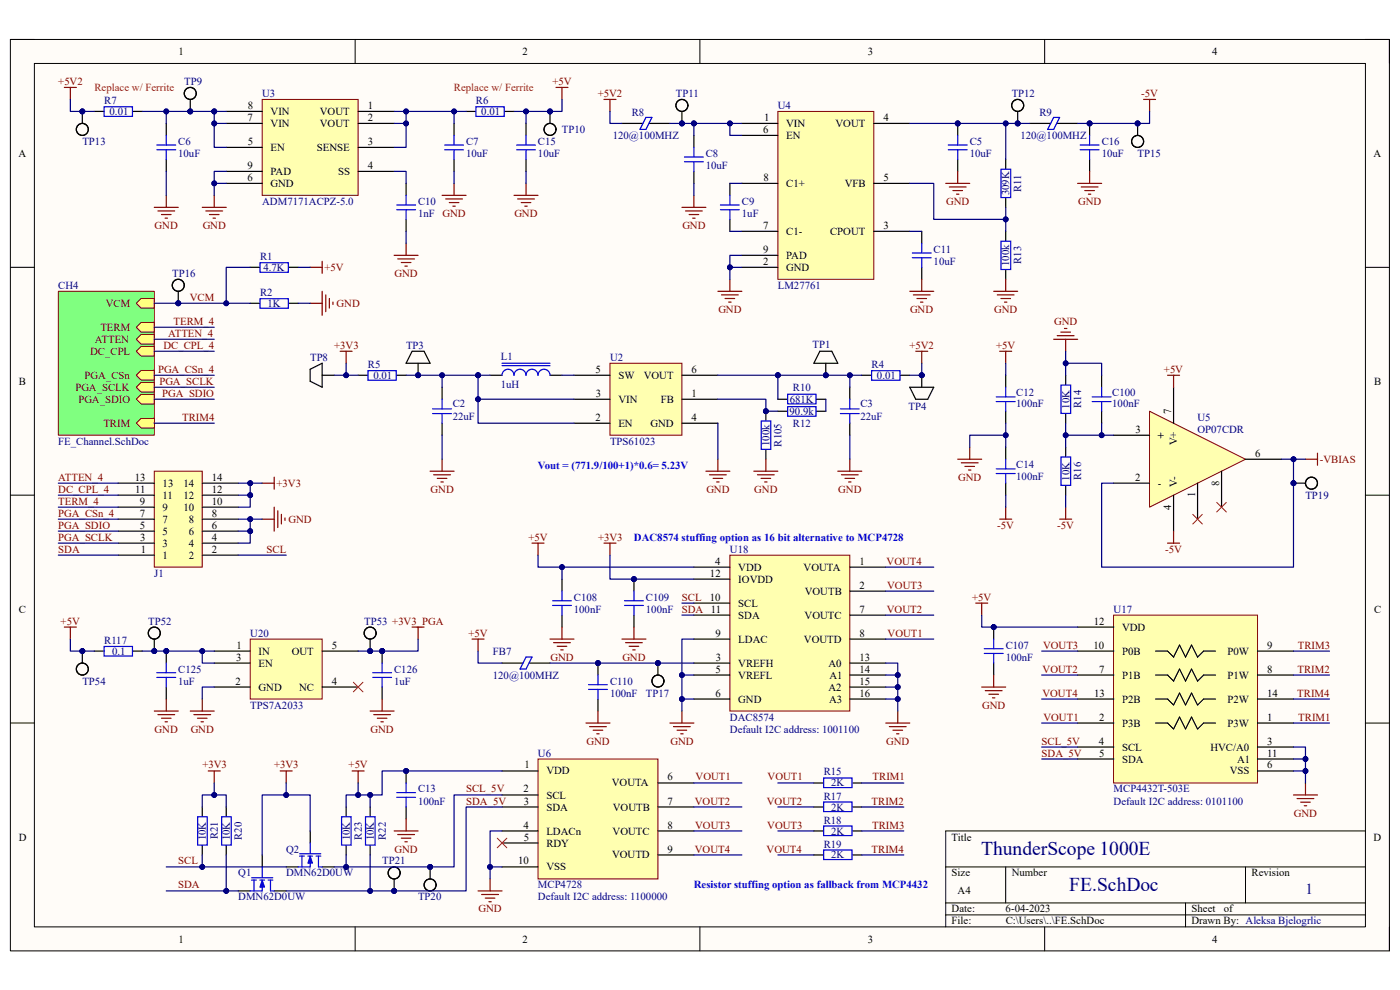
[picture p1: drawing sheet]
<svg xmlns="http://www.w3.org/2000/svg" width="297mm" height="210mm" viewBox="0 0 297 210" stroke-linecap="round" stroke-linejoin="round" font-family="sans-serif">
<defs><g id="words">
<g font-size="4.1" fill="#000080">
<text x="208.2" y="181.5">ThunderScope 1000E</text>
<text x="226.8" y="189.1">FE.SchDoc</text>
</g>
<text font-size="3.2" fill="#000080" x="276.9" y="189.6">1</text>
<g font-size="2.3">
<text x="37.9" y="11.7">1</text>
<text x="110.9" y="11.7">2</text>
<text x="184.1" y="11.7">3</text>
<text x="257.1" y="11.7">4</text>
<text x="52.6" y="23.1">8</text>
<text x="78" y="23.1">1</text>
<text x="52.5" y="25.7">7</text>
<text x="57.4" y="24.4">VIN</text>
<text x="57.4" y="26.9">VIN</text>
<text x="67.9" y="24.4">VOUT</text>
<text x="67.9" y="26.9">VOUT</text>
<text x="78" y="25.7">2</text>
<text x="161.9" y="28.2">6</text>
<text x="162.1" y="25.7">1</text>
<text x="166.8" y="26.9">VIN</text>
<text x="166.8" y="29.5">EN</text>
<text x="177.2" y="26.9">VOUT</text>
<text x="187.4" y="25.7">4</text>
<text x="3.9" y="33.3">A</text>
<text x="52.5" y="35.9">9</text>
<text x="52.6" y="30.7">5</text>
<text x="57.4" y="32">EN</text>
<text x="67.2" y="32">SENSE</text>
<text x="78" y="30.7">3</text>
<text x="78" y="35.9">4</text>
<text x="291.4" y="33.3">A</text>
<text x="52.5" y="38.4">6</text>
<text x="57.4" y="39.7">GND</text>
<text x="57.4" y="37.1">PAD</text>
<text x="71.8" y="37.1">SS</text>
<text x="162" y="38.4">8</text>
<text x="166.8" y="39.7">C1+</text>
<text x="179.2" y="39.7">VFB</text>
<text x="187.4" y="38.4">5</text>
<text x="161.9" y="48.6">7</text>
<text x="161.9" y="53.6">9</text>
<text x="166.8" y="49.8">C1-</text>
<text x="176.1" y="49.8">CPOUT</text>
<text x="187.4" y="48.6">3</text>
<text x="161.9" y="56.2">2</text>
<text x="166.8" y="57.4">GND</text>
<text x="166.8" y="54.9">PAD</text>
<text x="4" y="81.6">B</text>
<text x="126.4" y="79.1">5</text>
<text x="131.2" y="80.3">SW</text>
<text x="136.6" y="80.3">VOUT</text>
<text x="146.7" y="79.1">6</text>
<text x="291.5" y="81.6">B</text>
<text x="126.3" y="89.3">2</text>
<text x="126.4" y="84.2">3</text>
<text x="131.2" y="85.4">VIN</text>
<text x="140.2" y="85.4">FB</text>
<text x="146.7" y="89.3">4</text>
<text x="146.7" y="84.2">1</text>
<text x="248.5" y="87.8" transform="rotate(-90 248.5 87.8)">7</text>
<text x="131.2" y="90.6">EN</text>
<text x="138" y="90.6">GND</text>
<text x="240.9" y="91.8">3</text>
<text x="245.7" y="93.1">+</text>
<text x="249.7" y="94.5" transform="rotate(-90 249.7 94.5)">V+</text>
<text x="28.6" y="102">13</text>
<text x="45" y="102">14</text>
<text x="240.8" y="102">2</text>
<text x="266.3" y="96.9">6</text>
<text x="28.7" y="104.5">11</text>
<text x="29.6" y="107.1">9</text>
<text x="34.5" y="105.8">11</text>
<text x="34.5" y="103.3">13</text>
<text x="38.9" y="105.8">12</text>
<text x="38.9" y="103.3">14</text>
<text x="45" y="107.1">10</text>
<text x="45" y="104.5">12</text>
<text x="245.7" y="103.3">-</text>
<text x="249.7" y="103.3" transform="rotate(-90 249.7 103.3)">V-</text>
<text x="253.6" y="105.4" transform="rotate(-90 253.6 105.4)">1</text>
<text x="258.7" y="103" transform="rotate(-90 258.7 103)">8</text>
<text x="29.6" y="109.6">7</text>
<text x="29.7" y="112.1">5</text>
<text x="34.5" y="113.4">5</text>
<text x="34.5" y="110.9">7</text>
<text x="34.5" y="108.3">9</text>
<text x="38.9" y="108.3">10</text>
<text x="40" y="113.4">6</text>
<text x="40.1" y="110.9">8</text>
<text x="45" y="112.1">6</text>
<text x="45" y="109.6">8</text>
<text x="248.5" y="108.2" transform="rotate(-90 248.5 108.2)">4</text>
<text x="29.7" y="114.7">3</text>
<text x="29.8" y="117.3">1</text>
<text x="34.5" y="118.5">1</text>
<text x="34.5" y="116">3</text>
<text x="40" y="116">4</text>
<text x="40.1" y="118.5">2</text>
<text x="45" y="117.3">2</text>
<text x="45" y="114.7">4</text>
<text x="151.7" y="119.8">4</text>
<text x="182.3" y="119.8">1</text>
<text x="150.6" y="122.3">12</text>
<text x="156.6" y="121.1">VDD</text>
<text x="156.6" y="123.6">IOVDD</text>
<text x="170.5" y="121.1">VOUTA</text>
<text x="182.3" y="124.9">2</text>
<text x="4" y="130">C</text>
<text x="150.6" y="127.4">10</text>
<text x="156.6" y="128.7">SCL</text>
<text x="156.6" y="131.2">SDA</text>
<text x="170.7" y="131.2">VOUTC</text>
<text x="170.7" y="126.2">VOUTB</text>
<text x="182.3" y="130">7</text>
<text x="291.5" y="130">C</text>
<text x="50.2" y="137.6">1</text>
<text x="70.4" y="137.6">5</text>
<text x="151.8" y="135">9</text>
<text x="156.6" y="136.3">LDAC</text>
<text x="170.6" y="136.3">VOUTD</text>
<text x="182.3" y="135">8</text>
<text x="232" y="137.6">10</text>
<text x="232" y="132.5">12</text>
<text x="238" y="133.8">VDD</text>
<text x="268.8" y="137.6">9</text>
<text x="50.1" y="140.1">3</text>
<text x="54.9" y="138.9">IN</text>
<text x="54.9" y="141.4">EN</text>
<text x="61.9" y="138.9">OUT</text>
<text x="151.8" y="142.7">5</text>
<text x="151.8" y="140.1">3</text>
<text x="156.6" y="141.4">VREFH</text>
<text x="156.6" y="144">VREFL</text>
<text x="175.8" y="141.4">A0</text>
<text x="176" y="144">A1</text>
<text x="182.3" y="140.1">13</text>
<text x="182.3" y="142.7">14</text>
<text x="233.2" y="142.7">7</text>
<text x="238" y="138.9">P0B</text>
<text x="238" y="144">P1B</text>
<text x="260.4" y="138.9">P0W</text>
<text x="260.4" y="144">P1W</text>
<text x="268.8" y="142.7">8</text>
<text x="50" y="145.2">2</text>
<text x="54.9" y="146.5">GND</text>
<text x="63.5" y="146.5">NC</text>
<text x="70.4" y="145.2">4</text>
<text x="151.8" y="147.8">6</text>
<text x="156.6" y="149.1">GND</text>
<text x="175.8" y="146.5">A2</text>
<text x="175.9" y="149.1">A3</text>
<text x="182.3" y="145.2">15</text>
<text x="182.3" y="147.8">16</text>
<text x="232.1" y="147.8">13</text>
<text x="238" y="149.1">P2B</text>
<text x="260.4" y="149.1">P2W</text>
<text x="268.8" y="147.8">14</text>
<text x="233.2" y="152.9">2</text>
<text x="238" y="154.1">P3B</text>
<text x="260.4" y="154.1">P3W</text>
<text x="268.8" y="152.9">1</text>
<text x="233.1" y="157.9">4</text>
<text x="233.2" y="160.5">5</text>
<text x="238" y="159.2">SCL</text>
<text x="238" y="161.8">SDA</text>
<text x="256.8" y="159.2">HVC/A0</text>
<text x="262.5" y="161.8">A1</text>
<text x="268.8" y="157.9">3</text>
<text x="268.8" y="160.5">11</text>
<text x="111.3" y="163">1</text>
<text x="115.9" y="164.3">VDD</text>
<text x="129.8" y="166.8">VOUTA</text>
<text x="141.6" y="165.6">6</text>
<text x="260.9" y="164.3">VSS</text>
<text x="268.8" y="163">6</text>
<text x="111" y="168.1">2</text>
<text x="111.1" y="170.7">3</text>
<text x="115.9" y="169.4">SCL</text>
<text x="115.9" y="172">SDA</text>
<text x="130" y="172">VOUTB</text>
<text x="141.6" y="170.7">7</text>
<text x="4" y="178.3">D</text>
<text x="111" y="175.8">4</text>
<text x="111.1" y="178.3">5</text>
<text x="115.9" y="177">LDACn</text>
<text x="115.9" y="179.6">RDY</text>
<text x="130" y="177">VOUTC</text>
<text x="141.6" y="175.8">8</text>
<text x="201.9" y="178.3">Title</text>
<text x="291.4" y="178.3">D</text>
<text x="109.9" y="183.4">10</text>
<text x="115.9" y="184.7">VSS</text>
<text x="129.8" y="182.1">VOUTD</text>
<text x="141.6" y="180.8">9</text>
<text x="201.9" y="185.9">Size</text>
<text x="214.6" y="185.9">Number</text>
<text x="265.5" y="185.9">Revision</text>
<text x="203.2" y="189.7">A4</text>
<text x="201.9" y="193.5">Date:</text>
<text x="201.9" y="196.1">File:</text>
<text x="213.3" y="193.5">6-04-2023</text>
<text x="213.4" y="196.1">C:\Users\..\FE.SchDoc</text>
<text x="252.8" y="196.1">Drawn By: Aleksa Bjelogrlic</text>
<text x="252.8" y="193.5">Sheet</text>
<text x="259.6" y="193.5">of</text>
<text x="37.9" y="199.9">1</text>
<text x="110.9" y="199.9">2</text>
<text x="184.1" y="199.9">3</text>
<text x="257.1" y="199.9">4</text>
</g>
<g font-size="2.3" fill="#800000">
<text x="12.4" y="18">+5V2</text>
<text x="117.2" y="18">+5V</text>
<text x="126.8" y="20.6">+5V2</text>
<text x="242.1" y="20.6">-5V</text>
<text x="93.9" y="46">GND</text>
<text x="109.1" y="46">GND</text>
<text x="200.7" y="43.5">GND</text>
<text x="228.7" y="43.5">GND</text>
<text x="32.8" y="48.6">GND</text>
<text x="43" y="48.6">GND</text>
<text x="144.8" y="48.6">GND</text>
<text x="68.8" y="57.4">+5V</text>
<text x="83.7" y="58.7">GND</text>
<text x="22.4" y="65.1">VCM</text>
<text x="40.3" y="63.8">VCM</text>
<text x="71.4" y="65.1">GND</text>
<text x="21.3" y="70.2">TERM</text>
<text x="35.7" y="71.5">ATTEN_4</text>
<text x="36.8" y="68.9">TERM_4</text>
<text x="152.4" y="66.4">GND</text>
<text x="193.1" y="66.4">GND</text>
<text x="210.9" y="66.4">GND</text>
<text x="223.6" y="68.9">GND</text>
<text x="19.1" y="75.3">DC_CPL</text>
<text x="20.2" y="72.7">ATTEN</text>
<text x="34.7" y="74">DC_CPL_4</text>
<text x="70.9" y="74">+3V3</text>
<text x="193" y="74">+5V2</text>
<text x="211.3" y="74">+5V</text>
<text x="16" y="82.9">PGA_SCLK</text>
<text x="17.9" y="80.3">PGA_CSn</text>
<text x="33.5" y="79.1">PGA_CSn_4</text>
<text x="33.8" y="81.6">PGA_SCLK</text>
<text x="246.9" y="79.1">+5V</text>
<text x="16.6" y="85.4">PGA_SDIO</text>
<text x="34.4" y="84.2">PGA_SDIO</text>
<text x="38.7" y="89.3">TRIM4</text>
<text x="21.9" y="90.6">TRIM</text>
<text x="12.4" y="102">ATTEN_4</text>
<text x="203.3" y="102">GND</text>
<text x="280" y="98.2">-VBIAS</text>
<text x="12.4" y="104.5">DC_CPL_4</text>
<text x="12.4" y="107.1">TERM_4</text>
<text x="58.7" y="103.3">+3V3</text>
<text x="91.4" y="104.5">GND</text>
<text x="149.9" y="104.5">GND</text>
<text x="160" y="104.5">GND</text>
<text x="177.8" y="104.5">GND</text>
<text x="12.4" y="112.1">PGA_SDIO</text>
<text x="12.4" y="109.6">PGA_CSn_4</text>
<text x="61.2" y="110.9">GND</text>
<text x="211.6" y="112.1">-5V</text>
<text x="224.3" y="112.1">-5V</text>
<text x="12.4" y="117.3">SDA</text>
<text x="12.4" y="114.7">PGA_SCLK</text>
<text x="56.6" y="117.3">SCL</text>
<text x="112.1" y="114.7">+5V</text>
<text x="126.9" y="114.7">+3V3</text>
<text x="188.1" y="119.8">VOUT4</text>
<text x="247.2" y="117.3">-5V</text>
<text x="188.2" y="124.9">VOUT3</text>
<text x="144.7" y="127.4">SCL</text>
<text x="144.7" y="130">SDA 11</text>
<text x="188.1" y="130">VOUT2</text>
<text x="206.2" y="127.4">+5V</text>
<text x="12.9" y="132.5">+5V</text>
<text x="99.4" y="135">+5V</text>
<text x="188.3" y="135">VOUT1</text>
<text x="221.3" y="137.6">VOUT3</text>
<text x="275.3" y="137.6">TRIM3</text>
<text x="116.8" y="140.1">GND</text>
<text x="132" y="140.1">GND</text>
<text x="221.2" y="142.7">VOUT2</text>
<text x="275.3" y="142.7">TRIM2</text>
<text x="221.1" y="147.8">VOUT4</text>
<text x="275.2" y="147.8">TRIM4</text>
<text x="32.8" y="155.4">GND</text>
<text x="40.5" y="155.4">GND</text>
<text x="78.6" y="155.4">GND</text>
<text x="208.4" y="150.3">GND</text>
<text x="221.4" y="152.9">VOUT1</text>
<text x="275.4" y="152.9">TRIM1</text>
<text x="124.4" y="157.9">GND</text>
<text x="142.2" y="157.9">GND</text>
<text x="188" y="157.9">GND</text>
<text x="221" y="157.9">SCL_5V</text>
<text x="221" y="160.5">SDA_5V</text>
<text x="42.9" y="163">+3V3</text>
<text x="58.2" y="163">+3V3</text>
<text x="74" y="163">+5V</text>
<text x="147.6" y="165.6">VOUT1</text>
<text x="162.9" y="165.6">VOUT1</text>
<text x="185.1" y="165.6">TRIM1</text>
<text x="98.9" y="168.1">SCL_5V</text>
<text x="98.9" y="170.7">SDA_5V</text>
<text x="147.4" y="170.7">VOUT2</text>
<text x="162.7" y="170.7">VOUT2</text>
<text x="184.9" y="170.7">TRIM2</text>
<text x="274.5" y="173.2">GND</text>
<text x="147.5" y="175.8">VOUT3</text>
<text x="162.8" y="175.8">VOUT3</text>
<text x="185" y="175.8">TRIM3</text>
<text x="37.8" y="183.4">SCL</text>
<text x="83.7" y="180.8">GND</text>
<text x="147.4" y="180.8">VOUT4</text>
<text x="162.6" y="180.8">VOUT4</text>
<text x="184.9" y="180.8">TRIM4</text>
<text x="37.8" y="188.5">SDA</text>
<text x="101.5" y="193.5">GND</text>
</g>
<g font-size="2.3" fill="#f00">
<text x="20" y="19.3">Replace w/ Ferrite</text>
<text x="96.3" y="19.3">Replace w/ Ferrite</text>
</g>
<g font-size="2.3" fill="#000080">
<text x="22.1" y="22.1">R7</text>
<text x="39.1" y="18">TP9</text>
<text x="55.6" y="20.6">U3</text>
<text x="101" y="22.1">R6</text>
<text x="143.4" y="20.6">TP11</text>
<text x="165" y="23.1">U4</text>
<text x="214.6" y="20.6">TP12</text>
<text x="23.2" y="24.4">0.01</text>
<text x="102.1" y="24.4">0.01</text>
<text x="119.2" y="28.2">TP10</text>
<text x="130" y="29.5">120@100MHZ</text>
<text x="134" y="24.7">R8</text>
<text x="216.5" y="29.5">120@100MHZ</text>
<text x="220.5" y="24.7">R9</text>
<text x="17.5" y="30.7">TP13</text>
<text x="37.8" y="30.7">C6</text>
<text x="37.8" y="33.3">10uF</text>
<text x="98.9" y="30.7">C7</text>
<text x="98.9" y="33.3">10uF</text>
<text x="114.1" y="30.7">C15</text>
<text x="114.1" y="33.3">10uF</text>
<text x="149.7" y="33.3">C8</text>
<text x="149.7" y="35.9">10uF</text>
<text x="205.7" y="30.7">C5</text>
<text x="205.7" y="33.3">10uF</text>
<text x="233.7" y="30.7">C16</text>
<text x="233.7" y="33.3">10uF</text>
<text x="241.3" y="33.3">TP15</text>
<text x="214.1" y="41.4" transform="rotate(-90 214.1 41.4)">309K</text>
<text x="216.7" y="40.7" transform="rotate(-90 216.7 40.7)">R11</text>
<text x="55.6" y="43.5">ADM7171ACPZ-5.0</text>
<text x="88.7" y="43.5">C10</text>
<text x="88.7" y="46">1nF</text>
<text x="157.4" y="43.5">C9</text>
<text x="157.4" y="46">1uF</text>
<text x="198.1" y="53.6">C11</text>
<text x="36.5" y="58.7">TP16</text>
<text x="55.2" y="55.2">R1</text>
<text x="55.9" y="57.4">4.7K</text>
<text x="198.1" y="56.2">10uF</text>
<text x="214.1" y="56.5" transform="rotate(-90 214.1 56.5)">100k</text>
<text x="216.7" y="56" transform="rotate(-90 216.7 56)">R13</text>
<text x="12.4" y="61.3">CH4</text>
<text x="55.2" y="62.9">R2</text>
<text x="56.8" y="65.1">1K</text>
<text x="165" y="61.3">LM27761</text>
<text x="65.8" y="76.5">TP8</text>
<text x="86.1" y="74">TP3</text>
<text x="106.3" y="76.3">L1</text>
<text x="129.4" y="76.5">U2</text>
<text x="172.4" y="73.7">TP1</text>
<text x="78.1" y="78.1">R5</text>
<text x="79.2" y="80.3">0.01</text>
<text x="106.3" y="82.4">1uH</text>
<text x="168.2" y="82.9">R10</text>
<text x="184.9" y="78.1">R4</text>
<text x="186.1" y="80.3">0.01</text>
<text x="215.6" y="83.9">C12</text>
<text x="236" y="83.9">C100</text>
<text x="96.1" y="86.4">C2</text>
<text x="96.1" y="89">22uF</text>
<text x="167.5" y="88">90.9k</text>
<text x="167.6" y="85.4">681K</text>
<text x="182.5" y="86.4">C3</text>
<text x="182.5" y="89">22uF</text>
<text x="192.7" y="87">TP4</text>
<text x="215.6" y="86.4">100nF</text>
<text x="226.9" y="86.7" transform="rotate(-90 226.9 86.7)">10K</text>
<text x="229.4" y="86.6" transform="rotate(-90 229.4 86.6)">R14</text>
<text x="236" y="86.4">100nF</text>
<text x="254" y="89.3">U5</text>
<text x="12.4" y="94.4">FE_Channel.SchDoc</text>
<text x="129.4" y="94.4">TPS61023</text>
<text x="163.2" y="94.6" transform="rotate(-90 163.2 94.6)">100k</text>
<text x="165.8" y="94.7" transform="rotate(-90 165.8 94.7)">R105</text>
<text x="168.2" y="90.6">R12</text>
<text x="254" y="91.8">OP07CDR</text>
<text x="215.6" y="99.2">C14</text>
<text x="215.6" y="101.7">100nF</text>
<text x="226.9" y="101.9" transform="rotate(-90 226.9 101.9)">10K</text>
<text x="229.4" y="101.8" transform="rotate(-90 229.4 101.8)">R16</text>
<text x="276.9" y="105.8">TP19</text>
<text x="154.9" y="117.3">U18</text>
<text x="32.7" y="122.3">J1</text>
<text x="121.8" y="127.4">C108</text>
<text x="121.8" y="130">100nF</text>
<text x="137" y="127.4">C109</text>
<text x="137" y="130">100nF</text>
<text x="236.3" y="130">U17</text>
<text x="22.1" y="136.6">R117</text>
<text x="31.5" y="132.5">TP52</text>
<text x="53.1" y="135">U20</text>
<text x="77.3" y="132.5">TP53 +3V3_PGA</text>
<text x="213.4" y="137.6">C107</text>
<text x="23.8" y="138.9">0.1</text>
<text x="37.8" y="142.7">C125</text>
<text x="83.6" y="142.7">C126</text>
<text x="104.6" y="138.9">FB7</text>
<text x="104.6" y="144">120@100MHZ</text>
<text x="213.4" y="140.1">100nF</text>
<text x="17.5" y="145.2">TP54</text>
<text x="37.8" y="145.2">1uF</text>
<text x="83.6" y="145.2">1uF</text>
<text x="129.4" y="145.2">C110</text>
<text x="129.4" y="147.8">100nF</text>
<text x="137" y="147.8">TP17</text>
<text x="53.1" y="150.3">TPS7A2033</text>
<text x="154.9" y="152.9">DAC8574</text>
<text x="154.9" y="155.4">Default I2C address: 1001100</text>
<text x="114.1" y="160.5">U6</text>
<text x="174.8" y="164.5">R15</text>
<text x="176.3" y="166.8">2K</text>
<text x="88.7" y="168.1">C13</text>
<text x="88.7" y="170.7">100nF</text>
<text x="174.8" y="169.6">R17</text>
<text x="176.3" y="172">2K</text>
<text x="236.3" y="168.1">MCP4432T-503E</text>
<text x="236.3" y="170.7">Default I2C address: 0101100</text>
<text x="43.7" y="178.3" transform="rotate(-90 43.7 178.3)">10K</text>
<text x="46.2" y="178.1" transform="rotate(-90 46.2 178.1)">R21</text>
<text x="48.8" y="178.3" transform="rotate(-90 48.8 178.3)">10K</text>
<text x="51.3" y="178.1" transform="rotate(-90 51.3 178.1)">R20</text>
<text x="74.2" y="178.3" transform="rotate(-90 74.2 178.3)">10K</text>
<text x="76.8" y="178.1" transform="rotate(-90 76.8 178.1)">R23</text>
<text x="79.3" y="178.3" transform="rotate(-90 79.3 178.3)">10K</text>
<text x="81.8" y="178.1" transform="rotate(-90 81.8 178.1)">R22</text>
<text x="174.8" y="174.7">R18</text>
<text x="174.8" y="179.8">R19</text>
<text x="176.3" y="177">2K</text>
<text x="50.5" y="185.9">Q1</text>
<text x="60.7" y="180.8">Q2</text>
<text x="60.7" y="185.9">DMN62D0UW</text>
<text x="81.1" y="183.4">TP21</text>
<text x="176.3" y="182.1">2K</text>
<text x="50.5" y="191">DMN62D0UW</text>
<text x="88.7" y="191">TP20</text>
<text x="114.1" y="188.5">MCP4728</text>
<text x="114.1" y="191">Default I2C address: 1100000</text>
</g>
<g font-size="2.3" fill="#00f">
<text x="114.1" y="99.4">Vout = (771.9/100+1)*0.6= 5.23V</text>
<text x="134.5" y="114.7">DAC8574 stuffing option as 16 bit alternative to MCP4728</text>
<text x="147.2" y="188.5">Resistor stuffing option as fallback from MCP4432</text>
</g>
</g></defs>
<path d="M2.2 8.4h292.6v193.3h-292.6z" fill-rule="evenodd" fill="#fffcf8"/>
<path d="M2.2 8.4h292.6v193.3h-292.6z" fill="none" stroke="#000" stroke-width=".21"/>
<path d="M7.3 13.5h282.4v183.1h-282.4z" fill-rule="evenodd" fill="#fffcf8"/>
<g fill="none" stroke="#000" stroke-width=".21">
<path d="M2.2 8.4h5.1M7.3 13.5h282.4v183.1h-282.4zM75.3 8.4v5.1M148.5 8.4v5.1M221.6 8.4v5.1M289.7 8.4h5.1v5.1M2.2 56.7h5.1M289.7 56.7h5.1M2.2 105h5.1M289.7 105.1h5.1M2.2 153.4h5.1M289.7 153.4h5.1"/>
<path d="M289.7 176.3h-89.1v20.3M75.3 196.6v5.1M148.5 196.6v5.1M200.6 183.9h89.1M200.6 191.5h89.1M200.6 194.1h89.1M213.4 183.9v7.6M221.6 196.6v5.1M251.5 191.5v5.1M264.2 183.9v7.6M294.8 196.6v5.1"/>
</g>
<circle cx="86.2" cy="163.6" r=".51" fill="#000080"/>
<circle cx="86.2" cy="163.6" r=".51" fill="none" stroke="#000080" stroke-width=".21"/>
<path d="M86.2 163.6v2.5M86.2 171.2v2.5" fill="none" stroke="#000" stroke-width=".25"/>
<circle cx="86.2" cy="163.6" r=".51" fill="#000080"/>
<circle cx="86.2" cy="163.6" r=".51" fill="none" stroke="#000080" stroke-width=".21"/>
<path d="M84.2 169.1h4M84.2 168.1h4M86.2 166.1v2M86.2 169.1v2.1" fill="none" stroke="#00f" stroke-width=".25"/>
<g fill="none" stroke="#800000" stroke-width=".25">
<path d="M44.2 163.6h2.5M45.5 163.6v2.5M59.4 163.6h2.6M60.7 163.6v2.5M83.6 176.3h5.1M84.4 177h3.5M85.1 177.8h2.1M85.9 178.6h.5M86.2 173.7v2.6M101.4 189h5.1M102.2 189.8h3.5M102.9 190.5h2.1"/>
<path d="M103.7 191.3h.5M104 186.5v2.5"/>
</g>
<path d="M243.9 87.2l20.3 10.2-20.3 10.2z" fill="#ffffb0"/>
<path d="M243.9 87.2l20.3 10.2-20.3 10.2z" fill="none" stroke="#800000" stroke-width=".21"/>
<path d="M226.1 79.6v2M226.1 87.8v2M226.1 94.9v2M236.3 92.3h7.6M249 82.1v7.7M259.2 100v7.6M264.2 97.4h7.7M226.1 103v2.1M236.3 102.5h7.6M249 105.1v7.6M254.1 102.5v7.6" fill="none" stroke="#000" stroke-width=".25"/>
<path d="M253 109.1l2.1 2.1M255.1 109.1l-2.1 2.1M258.1 106.6l2.1 2M260.2 106.6l-2.1 2" fill="none" stroke="#f00" stroke-width=".21"/>
<path d="M225.1 81.7h2v6h-2zM225.1 97h2v6h-2z" fill="none" stroke="#00f" stroke-width=".25"/>
<path d="M277 97.4h2.5M279.5 96.1v2.6" fill="none" stroke="#800000" stroke-width=".25"/>
<path d="M114.1 161h25.5v25.5h-25.5z" fill-rule="evenodd" fill="#ffffb0"/>
<path d="M114.1 161h25.5v25.5h-25.5z" fill="none" stroke="#800000" stroke-width=".21"/>
<path d="M106.5 163.6h7.6M106.5 168.6h7.6M106.5 171.2h7.6M106.5 176.3h7.6M106.5 178.8h7.6M139.6 171.2h7.6M139.6 166.1h7.6M139.6 176.3h7.6M106.5 183.9h7.6M139.6 181.4h7.6" fill="none" stroke="#000" stroke-width=".25"/>
<path d="M105.5 177.8l2 2M107.5 177.8l-2 2" fill="none" stroke="#f00" stroke-width=".21"/>
<path d="M165 23.6h20.4v35.7h-20.4z" fill-rule="evenodd" fill="#ffffb0"/>
<path d="M165 23.6h20.4v35.7h-20.4z" fill="none" stroke="#800000" stroke-width=".21"/>
<g fill="none" stroke="#000" stroke-width=".25">
<path d="M147.2 28.7v2.6M147.2 36.4v2.5M154.8 38.9v2.5M157.4 26.2h7.6M157.4 28.7h7.6M157.4 38.9h7.6M185.4 26.2h7.6M185.4 38.9h7.6M213.4 33.8v2M154.8 46.5v2.6M157.4 56.7h7.6M157.4 49.1h7.6"/>
<path d="M157.4 54.2h7.6M185.4 49.1h7.6M195.5 49.1v2.5M195.5 56.7v2.6M213.4 42v2M213.4 49.1v2M213.4 57.3v2"/>
</g>
<g fill="none" stroke="#00f" stroke-width=".25">
<path d="M145.2 34.3h4M145.2 33.3h4M147.2 31.3v2M147.2 34.3v2.1M212.4 35.9h2v6h-2zM152.8 44.5h4M152.8 43.5h4M154.8 41.4v2.1M154.8 44.5v2M193.5 54.7h4M193.5 53.7h4M195.5 51.6v2.1"/>
<path d="M195.5 54.7v2M212.4 51.2h2v6h-2z"/>
</g>
<g fill="none" stroke="#800000" stroke-width=".25">
<path d="M128.1 21.1h2.6M129.4 21.1v2.5M144.7 44h5.1M145.4 44.8h3.6M146.2 45.5h2M147 46.3h.5M147.2 41.4v2.6M154.8 59.3v2.5M195.5 59.3v2.5M213.4 59.3v2.5M152.3 61.8h5.1M153.1 62.6h3.5"/>
<path d="M153.8 63.3h2.1M154.6 64.1h.5M193 61.8h5.1M193.8 62.6h3.5M194.5 63.3h2.1M195.3 64.1h.5M210.8 61.8h5.1M211.6 62.6h3.5M212.3 63.3h2.1M213.1 64.1h.5"/>
</g>
<circle cx="203.2" cy="26.2" r=".51" fill="#000080"/>
<circle cx="203.2" cy="26.2" r=".51" fill="none" stroke="#000080" stroke-width=".21"/>
<path d="M203.2 26.2v2.5M203.2 33.8v2.6" fill="none" stroke="#000" stroke-width=".25"/>
<circle cx="203.2" cy="26.2" r=".51" fill="#000080"/>
<circle cx="203.2" cy="26.2" r=".51" fill="none" stroke="#000080" stroke-width=".21"/>
<path d="M201.2 31.8h4M201.2 30.8h4M203.2 28.7v2.1M203.2 31.8v2M223.5 24.9h1.3l-1.3 2.6h-1.2z" fill="none" stroke="#00f" stroke-width=".25"/>
<path d="M200.6 38.9h5.1M201.4 39.7h3.6M203.2 36.4v2.5M242.6 21.1h2.6M243.9 21.1v2.5M202.2 40.4h2M202.9 41.2h.5" fill="none" stroke="#800000" stroke-width=".25"/>
<path d="M218.5 26.2h4.4M224.2 26.2h4.4" fill="none" stroke="#000" stroke-width=".25"/>
<path d="M55.6 21.1h20.4v20.3h-20.4z" fill-rule="evenodd" fill="#ffffb0"/>
<path d="M55.6 21.1h20.4v20.3h-20.4z" fill="none" stroke="#800000" stroke-width=".21"/>
<g fill="none" stroke="#000" stroke-width=".25">
<path d="M20 23.6h2M28.2 23.6h2M35.3 26.2v2.5M35.3 33.8v2.6M48 23.6h7.6M48 26.2h7.6M48 31.3h7.6M48 38.9h7.6M48 36.4h7.6M76 23.6h7.6M76 26.2h7.6M76 31.3h7.6"/>
<path d="M76 36.4h7.6M86.2 38.9v2.5M96.3 26.2v2.5M96.3 33.8v2.6M131.9 26.2h4.5M137.7 26.2h4.4M86.2 46.5v2.6"/>
</g>
<g fill="none" stroke="#800000" stroke-width=".25">
<path d="M13.6 18.5h2.6M14.9 18.5v2.6M118 18.5h2.5M119.2 18.5v2.6M96.3 38.9v2.5M32.7 44h5.1M33.5 44.8h3.6M34.3 45.5h2M35 46.3h.5M35.3 41.4v2.6M42.9 44h5.1M43.7 44.8h3.5"/>
<path d="M44.4 45.5h2.1M45.2 46.3h.5M45.5 41.4v2.6M83.6 54.2h5.1M84.4 54.9h3.5M85.1 55.7h2.1M85.9 56.5h.5M86.2 51.6v2.6M93.8 41.4h5.1M94.6 42.2h3.5M95.3 43h2.1M96.1 43.7h.5"/>
</g>
<g fill="none" stroke="#00f" stroke-width=".25">
<path d="M22.1 22.7h6v2h-6zM33.3 31.8h4M33.3 30.8h4M35.3 28.7v2.1M35.3 31.8v2M94.3 31.8h4M94.3 30.8h4M96.3 28.7v2.1M96.3 31.8v2M137 24.9h1.3l-1.3 2.6h-1.2zM84.2 44.5h4M84.2 43.5h4"/>
<path d="M86.2 41.4v2.1M86.2 44.5v2"/>
</g>
<circle cx="17.5" cy="23.6" r=".51" fill="#000080"/>
<circle cx="17.5" cy="23.6" r=".51" fill="none" stroke="#000080" stroke-width=".21"/>
<path d="M17.5 23.6v2.6" fill="none" stroke="#000" stroke-width=".25"/>
<circle cx="17.5" cy="23.6" r=".51" fill="#000080"/>
<circle cx="17.5" cy="23.6" r=".51" fill="none" stroke="#000080" stroke-width=".21"/>
<circle cx="17.5" cy="27.5" r="1.27" fill="none" stroke="#000" stroke-width=".25"/>
<circle cx="40.4" cy="23.6" r=".51" fill="#000080"/>
<circle cx="40.4" cy="23.6" r=".51" fill="none" stroke="#000080" stroke-width=".21"/>
<path d="M40.4 21.1v2.5" fill="none" stroke="#000" stroke-width=".25"/>
<circle cx="40.4" cy="23.6" r=".51" fill="#000080"/>
<circle cx="40.4" cy="23.6" r=".51" fill="none" stroke="#000080" stroke-width=".21"/>
<circle cx="40.4" cy="19.8" r="1.27" fill="none" stroke="#000" stroke-width=".25"/>
<circle cx="144.7" cy="26.2" r=".51" fill="#000080"/>
<circle cx="144.7" cy="26.2" r=".51" fill="none" stroke="#000080" stroke-width=".21"/>
<path d="M144.7 23.6v2.6" fill="none" stroke="#000" stroke-width=".25"/>
<circle cx="144.7" cy="26.2" r=".51" fill="#000080"/>
<circle cx="144.7" cy="26.2" r=".51" fill="none" stroke="#000080" stroke-width=".21"/>
<circle cx="144.7" cy="22.4" r="1.27" fill="none" stroke="#000" stroke-width=".25"/>
<circle cx="215.9" cy="26.2" r=".51" fill="#000080"/>
<circle cx="215.9" cy="26.2" r=".51" fill="none" stroke="#000080" stroke-width=".21"/>
<path d="M215.9 23.6v2.6" fill="none" stroke="#000" stroke-width=".25"/>
<circle cx="215.9" cy="26.2" r=".51" fill="#000080"/>
<circle cx="215.9" cy="26.2" r=".51" fill="none" stroke="#000080" stroke-width=".21"/>
<circle cx="215.9" cy="22.4" r="1.27" fill="none" stroke="#000" stroke-width=".25"/>
<circle cx="241.3" cy="26.2" r=".51" fill="#000080"/>
<circle cx="241.3" cy="26.2" r=".51" fill="none" stroke="#000080" stroke-width=".21"/>
<path d="M241.3 26.2v2.5" fill="none" stroke="#000" stroke-width=".25"/>
<circle cx="241.3" cy="26.2" r=".51" fill="#000080"/>
<circle cx="241.3" cy="26.2" r=".51" fill="none" stroke="#000080" stroke-width=".21"/>
<circle cx="241.3" cy="30" r="1.27" fill="none" stroke="#000" stroke-width=".25"/>
<circle cx="274.4" cy="102.5" r=".51" fill="#000080"/>
<circle cx="274.4" cy="102.5" r=".51" fill="none" stroke="#000080" stroke-width=".21"/>
<path d="M274.4 102.5h2.6" fill="none" stroke="#000" stroke-width=".25"/>
<circle cx="274.4" cy="102.5" r=".51" fill="#000080"/>
<circle cx="274.4" cy="102.5" r=".51" fill="none" stroke="#000080" stroke-width=".21"/>
<circle cx="278.2" cy="102.5" r="1.27" fill="none" stroke="#000" stroke-width=".25"/>
<circle cx="37.8" cy="64.3" r=".51" fill="#000080"/>
<circle cx="37.8" cy="64.3" r=".51" fill="none" stroke="#000080" stroke-width=".21"/>
<path d="M37.8 61.8v2.5" fill="none" stroke="#000" stroke-width=".25"/>
<circle cx="37.8" cy="64.3" r=".51" fill="#000080"/>
<circle cx="37.8" cy="64.3" r=".51" fill="none" stroke="#000080" stroke-width=".21"/>
<circle cx="37.8" cy="60.5" r="1.27" fill="none" stroke="#000" stroke-width=".25"/>
<circle cx="91.2" cy="183.9" r=".51" fill="#000080"/>
<circle cx="91.2" cy="183.9" r=".51" fill="none" stroke="#000080" stroke-width=".21"/>
<path d="M91.2 183.9v2.6" fill="none" stroke="#000" stroke-width=".25"/>
<circle cx="91.2" cy="183.9" r=".51" fill="#000080"/>
<circle cx="91.2" cy="183.9" r=".51" fill="none" stroke="#000080" stroke-width=".21"/>
<circle cx="91.2" cy="187.7" r="1.27" fill="none" stroke="#000" stroke-width=".25"/>
<circle cx="83.6" cy="189" r=".51" fill="#000080"/>
<circle cx="83.6" cy="189" r=".51" fill="none" stroke="#000080" stroke-width=".21"/>
<path d="M83.6 186.5v2.5" fill="none" stroke="#000" stroke-width=".25"/>
<circle cx="83.6" cy="189" r=".51" fill="#000080"/>
<circle cx="83.6" cy="189" r=".51" fill="none" stroke="#000080" stroke-width=".21"/>
<circle cx="83.6" cy="185.2" r="1.27" fill="none" stroke="#000" stroke-width=".25"/>
<circle cx="116.7" cy="23.6" r=".51" fill="#000080"/>
<circle cx="116.7" cy="23.6" r=".51" fill="none" stroke="#000080" stroke-width=".21"/>
<path d="M116.7 23.6v2.6" fill="none" stroke="#000" stroke-width=".25"/>
<circle cx="116.7" cy="23.6" r=".51" fill="#000080"/>
<circle cx="116.7" cy="23.6" r=".51" fill="none" stroke="#000080" stroke-width=".21"/>
<g fill="none" stroke="#000" stroke-width=".25">
<path d="M213.4 79.6v2.5M213.4 87.2v2.6M213.4 94.9v2.5M213.4 102.5v2.6"/>
<circle cx="116.7" cy="27.5" r="1.27"/>
</g>
<path d="M211.3 99.5h4.1M211.3 84.2h4.1M211.3 85.2h4.1M213.4 82.1v2.1M213.4 85.2v2M213.4 97.4v2.1M211.3 100.5h4.1M213.4 100.5v2" fill="none" stroke="#00f" stroke-width=".25"/>
<g fill="none" stroke="#800000" stroke-width=".25">
<path d="M212.1 74.5h2.5M213.4 74.5v2.6M247.7 79.6h2.5M249 79.6v2.5M203.2 97.4h5.1M203.9 98.2h3.6M204.7 98.9h2M205.5 99.7h.5M205.7 94.9v2.5M212.1 110.1h2.5M213.4 107.6v2.5M224.8 110.1h2.6"/>
<path d="M226.1 107.6v2.5M247.7 115.2h2.5M249 112.7v2.5M74.7 163.6h2.6M76 163.6v2.5"/>
</g>
<path d="M12.4 61.8h20.3v30.5h-20.3z" fill-rule="evenodd" fill="#80ff80"/>
<path d="M12.4 61.8h20.3v30.5h-20.3z" fill="none" stroke="#800000" stroke-width=".21"/>
<path d="M28.9 64.3l1-1h2.8v2.1h-2.8z" fill-rule="evenodd" fill="#ffff80"/>
<path d="M28.9 64.3l1-1h2.8v2.1h-2.8z" fill="none" stroke="#800000" stroke-width=".21"/>
<path d="M28.9 89.8l1-1h2.8v2h-2.8z" fill-rule="evenodd" fill="#ffff80"/>
<path d="M28.9 89.8l1-1h2.8v2h-2.8z" fill="none" stroke="#800000" stroke-width=".21"/>
<path d="M28.9 72l1-1h2.8v2h-2.8z" fill-rule="evenodd" fill="#ffff80"/>
<path d="M28.9 72l1-1h2.8v2h-2.8z" fill="none" stroke="#800000" stroke-width=".21"/>
<path d="M28.9 74.5l1-1h2.8v2h-2.8z" fill-rule="evenodd" fill="#ffff80"/>
<path d="M28.9 74.5l1-1h2.8v2h-2.8z" fill="none" stroke="#800000" stroke-width=".21"/>
<path d="M28.9 79.6l1-1h2.8v2h-2.8z" fill-rule="evenodd" fill="#ffff80"/>
<path d="M28.9 79.6l1-1h2.8v2h-2.8z" fill="none" stroke="#800000" stroke-width=".21"/>
<path d="M29.9 81.1h2.8v2.1h-2.8l-1-1.1z" fill-rule="evenodd" fill="#ffff80"/>
<path d="M29.9 81.1h2.8v2.1h-2.8l-1-1.1z" fill="none" stroke="#800000" stroke-width=".21"/>
<path d="M28.9 84.7l1-1h2.8v2h-2.8z" fill-rule="evenodd" fill="#ffff80"/>
<path d="M28.9 84.7l1-1h2.8v2h-2.8z" fill="none" stroke="#800000" stroke-width=".21"/>
<path d="M28.9 69.4l1-1h2.8v2h-2.8z" fill-rule="evenodd" fill="#ffff80"/>
<path d="M28.9 69.4l1-1h2.8v2h-2.8z" fill="none" stroke="#800000" stroke-width=".21"/>
<path d="M223.5 72h5.1M224.3 71.2h3.6M225.1 70.5h2M225.8 69.7h.5M226.1 72v2.5" fill="none" stroke="#800000" stroke-width=".25"/>
<path d="M233.7 79.6v2.5M233.7 87.2v2.6" fill="none" stroke="#000" stroke-width=".25"/>
<path d="M231.7 84.2h4M231.7 85.2h4M233.7 82.1v2.1M233.7 85.2v2" fill="none" stroke="#00f" stroke-width=".25"/>
<path d="M236.3 130.5h30.5v35.6h-30.5z" fill-rule="evenodd" fill="#ffffb0"/>
<path d="M236.3 130.5h30.5v35.6h-30.5z" fill="none" stroke="#800000" stroke-width=".21"/>
<g fill="none" stroke="#000" stroke-width=".25">
<path d="M228.6 133h7.7M228.6 138.1h7.7M245.2 138.1h2.5l1.3 1.3 1.2-2.6 1.3 2.6 1.3-2.6 1.3 2.6 1.2-1.3h2.6M266.8 138.1h7.6M228.6 158.5h7.7M228.6 143.2h7.7M228.6 148.3h7.7M228.6 153.4h7.7M245.2 143.2h2.5l1.3 1.3 1.2-2.6 1.3 2.6 1.3-2.6 1.3 2.6 1.2-1.3h2.6M245.2 148.3h2.5l1.3 1.3 1.2-2.6 1.3 2.6 1.3-2.6 1.3 2.6 1.2-1.3h2.6M245.2 153.4h2.5l1.3 1.3 1.2-2.6 1.3 2.6 1.3-2.6 1.3 2.6 1.2-1.3h2.6M266.8 158.5h7.6"/>
<path d="M266.8 143.2h7.6M266.8 148.3h7.6M266.8 153.4h7.6M172.7 166.1h2M172.7 171.2h2M172.7 176.3h2M180.8 166.1h2M180.8 171.2h2M180.8 176.3h2M228.6 161h7.7M266.8 161h7.6M266.8 163.6h7.6"/>
<path d="M172.7 181.4h2M180.8 181.4h2"/>
</g>
<path d="M174.7 165h6v2.1h-6zM174.7 170.1h6v2.1h-6zM174.7 175.2h6v2.1h-6zM174.7 180.3h6v2h-6z" fill="none" stroke="#00f" stroke-width=".25"/>
<path d="M274.4 168.6h5.1M275.2 169.4h3.5M275.9 170.2h2.1M276.7 170.9h.5M277 166.1v2.5" fill="none" stroke="#800000" stroke-width=".25"/>
<circle cx="210.8" cy="133" r=".51" fill="#000080"/>
<circle cx="210.8" cy="133" r=".51" fill="none" stroke="#000080" stroke-width=".21"/>
<path d="M210.8 133v2.6M210.8 140.7v2.5" fill="none" stroke="#000" stroke-width=".25"/>
<circle cx="210.8" cy="133" r=".51" fill="#000080"/>
<circle cx="210.8" cy="133" r=".51" fill="none" stroke="#000080" stroke-width=".21"/>
<path d="M208.8 138.6h4M208.8 137.6h4M210.8 135.6v2M210.8 138.6v2.1" fill="none" stroke="#00f" stroke-width=".25"/>
<path d="M207 127.9h2.5M208.3 127.9v2.6M208.3 145.8h5.1M209 146.5h3.6M209.8 147.3h2M210.6 148h.5M210.8 143.2v2.6" fill="none" stroke="#800000" stroke-width=".25"/>
<path d="M154.8 117.8h25.5v33h-25.5z" fill-rule="evenodd" fill="#ffffb0"/>
<path d="M154.8 117.8h25.5v33h-25.5z" fill="none" stroke="#800000" stroke-width=".21"/>
<g fill="none" stroke="#000" stroke-width=".25">
<path d="M147.2 120.3h7.6M147.2 127.9h7.6M147.2 130.5h7.6M147.2 135.6h7.6M147.2 122.9h7.6M180.3 120.3h7.6M180.3 130.5h7.6M180.3 135.6h7.6M180.3 125.4h7.6M106.5 140.7h4.5M112.2 140.7h4.5M147.2 148.3h7.6"/>
<path d="M147.2 140.7h7.6M147.2 143.2h7.6M180.3 148.3h7.6M180.3 140.7h7.6M180.3 143.2h7.6M180.3 145.8h7.6"/>
</g>
<path d="M128.1 115.2h2.6M129.4 115.2v2.6M142.1 153.4h5.1M142.9 154.1h3.5M143.6 154.9h2.1M144.4 155.7h.5M144.7 150.8v2.6M187.9 153.4h5.1M188.7 154.1h3.5M189.4 154.9h2.1M190.2 155.7h.5M190.5 150.8v2.6" fill="none" stroke="#800000" stroke-width=".25"/>
<path d="M111.6 139.4h1.3l-1.3 2.5h-1.3z" fill="none" stroke="#00f" stroke-width=".25"/>
<circle cx="126.9" cy="140.7" r=".51" fill="#000080"/>
<circle cx="126.9" cy="140.7" r=".51" fill="none" stroke="#000080" stroke-width=".21"/>
<path d="M126.9 140.7v2.5M126.9 148.3v2.5" fill="none" stroke="#000" stroke-width=".25"/>
<circle cx="126.9" cy="140.7" r=".51" fill="#000080"/>
<circle cx="126.9" cy="140.7" r=".51" fill="none" stroke="#000080" stroke-width=".21"/>
<path d="M124.9 146.3h4M124.9 145.2h4M126.9 143.2v2M126.9 146.3v2" fill="none" stroke="#00f" stroke-width=".25"/>
<path d="M124.3 153.4h5.1M125.1 154.1h3.5M125.8 154.9h2.1M126.6 155.7h.5M126.9 150.8v2.6" fill="none" stroke="#800000" stroke-width=".25"/>
<circle cx="134.5" cy="122.9" r=".51" fill="#000080"/>
<circle cx="134.5" cy="122.9" r=".51" fill="none" stroke="#000080" stroke-width=".21"/>
<path d="M134.5 122.9v2.5M134.5 130.5v2.5" fill="none" stroke="#000" stroke-width=".25"/>
<circle cx="134.5" cy="122.9" r=".51" fill="#000080"/>
<circle cx="134.5" cy="122.9" r=".51" fill="none" stroke="#000080" stroke-width=".21"/>
<path d="M117.2 128.4h4M117.2 127.4h4M119.2 125.4v2M119.2 128.4v2.1M132.5 128.4h4M132.5 127.4h4M134.5 125.4v2M134.5 128.4v2.1" fill="none" stroke="#00f" stroke-width=".25"/>
<g fill="none" stroke="#800000" stroke-width=".25">
<path d="M112.9 115.2h2.5M114.1 115.2v2.6M100.1 135.6h2.6M101.4 135.6v2.5M116.7 135.6h5.1M117.4 136.3h3.6M118.2 137.1h2M119 137.9h.5M119.2 133v2.6M131.9 135.6h5.1M132.7 136.3h3.6M133.5 137.1h2"/>
<path d="M134.2 137.9h.5M134.5 133v2.6"/>
</g>
<path d="M119.2 122.9v2.5M119.2 130.5v2.5" fill="none" stroke="#000" stroke-width=".25"/>
<circle cx="139.6" cy="140.7" r=".51" fill="#000080"/>
<circle cx="139.6" cy="140.7" r=".51" fill="none" stroke="#000080" stroke-width=".21"/>
<path d="M139.6 140.7v2.5" fill="none" stroke="#000" stroke-width=".25"/>
<circle cx="139.6" cy="140.7" r=".51" fill="#000080"/>
<circle cx="139.6" cy="140.7" r=".51" fill="none" stroke="#000080" stroke-width=".21"/>
<g fill="none" stroke="#000" stroke-width=".25">
<path d="M42.9 171.2v2M42.9 179.4v2M48 171.2v2M48 179.4v2M73.4 171.2v2M73.4 179.4v2M78.5 171.2v2M78.5 179.4v2M50.5 189h2.6M55.6 181.4v2.5M58.2 189h2.5"/>
<circle cx="139.6" cy="144.5" r="1.27"/>
</g>
<path d="M41.9 173.3h2.1v6h-2.1zM47 173.3h2.1v6h-2.1zM72.5 173.3h2v6h-2zM77.5 173.3h2.1v6h-2.1zM53.4 186.2h4.5M53.4 186.7h1M53.9 186.7v2.3M55.1 186.7h1M55.6 183.9v2.3M55.6 186.7v2.3h-2.5M56.9 186.7h1M57.4 186.7v2.3" fill="none" stroke="#00f" stroke-width=".25"/>
<path d="M55.6 186.7l.5 1.5h-1z" fill="#00f"/>
<path d="M55.6 186.7l.5 1.5h-1z" fill="none" stroke="#00f" stroke-width=".21"/>
<path d="M65.8 178.8v2.3M57.4 189h.8M63.6 181.1h4.5M63.6 181.6h1M64.1 181.6v2.3M65.3 181.6h1M65.8 181.6v2.3h-2.5M67.1 181.6h1M67.6 181.6v2.3" fill="none" stroke="#00f" stroke-width=".25"/>
<path d="M65.8 176.3v2.5M60.7 183.9h2.6M68.3 183.9h2.6" fill="none" stroke="#000" stroke-width=".25"/>
<path d="M65.8 181.6l.5 1.5h-1z" fill="#00f"/>
<path d="M65.8 181.6l.5 1.5h-1z" fill="none" stroke="#00f" stroke-width=".21"/>
<path d="M67.6 183.9h.7" fill="none" stroke="#00f" stroke-width=".25"/>
<path d="M53.1 135.6h15.2v12.7h-15.2z" fill-rule="evenodd" fill="#ffffb0"/>
<path d="M53.1 135.6h15.2v12.7h-15.2z" fill="none" stroke="#800000" stroke-width=".21"/>
<path d="M45.5 138.1h7.6M68.3 138.1h7.7M45.5 145.7h7.6M45.5 140.7h7.6M68.3 145.7h7.7" fill="none" stroke="#000" stroke-width=".25"/>
<circle cx="35.3" cy="138.1" r=".51" fill="#000080"/>
<circle cx="35.3" cy="138.1" r=".51" fill="none" stroke="#000080" stroke-width=".21"/>
<path d="M35.3 138.1v2.6M35.3 145.7v2.6" fill="none" stroke="#000" stroke-width=".25"/>
<circle cx="35.3" cy="138.1" r=".51" fill="#000080"/>
<circle cx="35.3" cy="138.1" r=".51" fill="none" stroke="#000080" stroke-width=".21"/>
<path d="M33.3 143.7h4M33.3 142.7h4M35.3 140.7v2M35.3 143.7v2" fill="none" stroke="#00f" stroke-width=".25"/>
<path d="M32.7 150.8h5.1M33.5 151.6h3.6M34.3 152.4h2M35 153.1h.5M35.3 148.3v2.5M40.4 150.8h5.1M41.1 151.6h3.6M41.9 152.4h2M42.7 153.1h.5M42.9 148.3v2.5" fill="none" stroke="#800000" stroke-width=".25"/>
<path d="M75 144.7l2 2.1M77 144.7l-2 2.1" fill="none" stroke="#f00" stroke-width=".21"/>
<circle cx="81.1" cy="138.1" r=".51" fill="#000080"/>
<circle cx="81.1" cy="138.1" r=".51" fill="none" stroke="#000080" stroke-width=".21"/>
<path d="M81.1 138.1v2.6M81.1 145.7v2.6" fill="none" stroke="#000" stroke-width=".25"/>
<circle cx="81.1" cy="138.1" r=".51" fill="#000080"/>
<circle cx="81.1" cy="138.1" r=".51" fill="none" stroke="#000080" stroke-width=".21"/>
<path d="M22.1 137.1h6v2.1h-6zM79.1 143.7h4M79.1 142.7h4M81.1 140.7v2M81.1 143.7v2" fill="none" stroke="#00f" stroke-width=".25"/>
<path d="M78.5 150.8h5.1M79.3 151.6h3.5M80.1 152.4h2M80.8 153.1h.5M81.1 148.3v2.5" fill="none" stroke="#800000" stroke-width=".25"/>
<path d="M20 138.1h2M28.2 138.1h2" fill="none" stroke="#000" stroke-width=".25"/>
<circle cx="17.5" cy="138.1" r=".51" fill="#000080"/>
<circle cx="17.5" cy="138.1" r=".51" fill="none" stroke="#000080" stroke-width=".21"/>
<path d="M17.5 138.1v2.6" fill="none" stroke="#000" stroke-width=".25"/>
<circle cx="17.5" cy="138.1" r=".51" fill="#000080"/>
<circle cx="17.5" cy="138.1" r=".51" fill="none" stroke="#000080" stroke-width=".21"/>
<circle cx="17.5" cy="141.9" r="1.27" fill="none" stroke="#000" stroke-width=".25"/>
<circle cx="32.7" cy="138.1" r=".51" fill="#000080"/>
<circle cx="32.7" cy="138.1" r=".51" fill="none" stroke="#000080" stroke-width=".21"/>
<path d="M32.7 135.6v2.5" fill="none" stroke="#000" stroke-width=".25"/>
<circle cx="32.7" cy="138.1" r=".51" fill="#000080"/>
<circle cx="32.7" cy="138.1" r=".51" fill="none" stroke="#000080" stroke-width=".21"/>
<circle cx="32.7" cy="134.3" r="1.27" fill="none" stroke="#000" stroke-width=".25"/>
<circle cx="78.5" cy="138.1" r=".51" fill="#000080"/>
<circle cx="78.5" cy="138.1" r=".51" fill="none" stroke="#000080" stroke-width=".21"/>
<path d="M78.5 135.6v2.5" fill="none" stroke="#000" stroke-width=".25"/>
<circle cx="78.5" cy="138.1" r=".51" fill="#000080"/>
<circle cx="78.5" cy="138.1" r=".51" fill="none" stroke="#000080" stroke-width=".21"/>
<g fill="none" stroke="#000" stroke-width=".25">
<path d="M182.8 79.6h2M191 79.6h2M93.8 82.1v2.6M93.8 89.8v2.5M180.3 82.1v2.6M180.3 89.8v2.5"/>
<circle cx="78.5" cy="134.3" r="1.27"/>
</g>
<g fill="none" stroke="#800000" stroke-width=".25">
<path d="M194.3 74.5h2.5M195.5 74.5v2.6M91.2 100h5.1M93.8 97.4v2.6M177.7 100h5.1M180.3 97.4v2.6M92 100.7h3.6M92.8 101.5h2M93.5 102.2h.5M178.5 100.7h3.6M179.3 101.5h2M180 102.2h.5"/>
<path d="M13.7 133h2.5M14.9 133v2.6M87.4 133h2.6M88.7 133v2.6"/>
</g>
<path d="M184.9 78.6h6v2.1h-6zM91.8 87.7h4M91.8 86.7h4M93.8 84.7v2M93.8 87.7v2.1M178.3 87.7h4M178.3 86.7h4M180.3 84.7v2M180.3 87.7v2.1" fill="none" stroke="#00f" stroke-width=".25"/>
<circle cx="175.2" cy="79.6" r=".51" fill="#000080"/>
<circle cx="175.2" cy="79.6" r=".51" fill="none" stroke="#000080" stroke-width=".21"/>
<path d="M175.2 77.1v2.5" fill="none" stroke="#000" stroke-width=".25"/>
<circle cx="175.2" cy="79.6" r=".51" fill="#000080"/>
<circle cx="175.2" cy="79.6" r=".51" fill="none" stroke="#000080" stroke-width=".21"/>
<path d="M173.9 74.5h2.6l1.2 2.6h-5z" fill="none" stroke="#000" stroke-width=".25"/>
<circle cx="195.5" cy="79.6" r=".51" fill="#000080"/>
<circle cx="195.5" cy="79.6" r=".51" fill="none" stroke="#000080" stroke-width=".21"/>
<path d="M195.5 79.6v2.5" fill="none" stroke="#000" stroke-width=".25"/>
<circle cx="195.5" cy="79.6" r=".51" fill="#000080"/>
<circle cx="195.5" cy="79.6" r=".51" fill="none" stroke="#000080" stroke-width=".21"/>
<path d="M193 82.1h5.1l-1.3 2.6h-2.5z" fill="none" stroke="#000" stroke-width=".25"/>
<path d="M129.4 77.1h15.3v15.2h-15.3z" fill-rule="evenodd" fill="#ffffb0"/>
<path d="M129.4 77.1h15.3v15.2h-15.3z" fill="none" stroke="#800000" stroke-width=".21"/>
<path d="M104 79.6h2.5M116.7 79.6h2.5M121.8 79.6h7.6M144.7 79.6h7.6M121.8 84.7h7.6M121.8 89.8h7.6M144.7 84.7h7.6M144.7 89.8h7.6" fill="none" stroke="#000" stroke-width=".25"/>
<path d="M149.8 100h5M152.3 97.4v2.6M150.5 100.7h3.6M151.3 101.5h2M152 102.2h.6" fill="none" stroke="#800000" stroke-width=".25"/>
<path d="M106.5 79.6a1.27 1.27 0 0 1 1.3-1.3 1.27 1.27 0 0 1 1.3 1.3 1.27 1.27 0 0 1 1.2-1.3 1.27 1.27 0 0 1 1.3 1.3 1.27 1.27 0 0 1 1.3-1.3 1.27 1.27 0 0 1 1.2 1.3 1.27 1.27 0 0 1 1.3-1.3 1.27 1.27 0 0 1 1.3 1.3M106.5 77.6h10.2M106.5 77.1h10.2" fill="none" stroke="#00f" stroke-width=".25"/>
<circle cx="88.7" cy="79.6" r=".51" fill="#000080"/>
<circle cx="88.7" cy="79.6" r=".51" fill="none" stroke="#000080" stroke-width=".21"/>
<path d="M88.7 77.1v2.5" fill="none" stroke="#000" stroke-width=".25"/>
<circle cx="88.7" cy="79.6" r=".51" fill="#000080"/>
<circle cx="88.7" cy="79.6" r=".51" fill="none" stroke="#000080" stroke-width=".21"/>
<path d="M65.8 78.3l2.5-1.2v5l-2.5-1.2zM68.3 79.6h2.6M76 79.6h2M84.2 79.6h2M87.4 74.5h2.6l1.2 2.6h-5z" fill="none" stroke="#000" stroke-width=".25"/>
<path d="M72.2 74.5h2.5M73.4 74.5v2.6" fill="none" stroke="#800000" stroke-width=".25"/>
<path d="M78.1 78.6h6v2.1h-6z" fill="none" stroke="#00f" stroke-width=".25"/>
<circle cx="162.5" cy="87.2" r=".51" fill="#000080"/>
<circle cx="162.5" cy="87.2" r=".51" fill="none" stroke="#000080" stroke-width=".21"/>
<path d="M162.5 87.2v2" fill="none" stroke="#000" stroke-width=".25"/>
<circle cx="162.5" cy="87.2" r=".51" fill="#000080"/>
<circle cx="162.5" cy="87.2" r=".51" fill="none" stroke="#000080" stroke-width=".21"/>
<path d="M53.1 56.7h2M61.3 56.7h2M53.1 64.3h2M61.3 64.3h2M162.5 95.4v2M165 87.2h2M165 84.7h2M173.2 87.2h2M173.2 84.7h2" fill="none" stroke="#000" stroke-width=".25"/>
<path d="M55.2 55.7h6v2.1h-6zM55.2 63.4h6v2h-6zM161.5 89.3h2v6h-2zM167.1 86.3h6v2h-6zM167.1 83.6h6v2.1h-6z" fill="none" stroke="#00f" stroke-width=".25"/>
<g fill="none" stroke="#800000" stroke-width=".25">
<path d="M65.8 56.7h2.5M68.3 55.4v2.6M65.8 64.3h2.5M68.3 61.8v5.1M69.1 62.6v3.5M69.9 63.3v2.1M70.6 64.1v.5M159.9 100h5.1M162.5 97.4v2.6M55.6 102.5h2.6M55.6 110.1h2.6M58.2 101.2v2.6"/>
<path d="M58.2 107.6v5.1M58.9 108.4v3.5M59.7 109.1v2.1M60.5 109.9v.5M160.7 100.7h3.6M161.5 101.5h2M162.2 102.2h.5"/>
</g>
<path d="M32.7 100h10.2v20.3h-10.2z" fill-rule="evenodd" fill="#ffffb0"/>
<path d="M32.7 100h10.2v20.3h-10.2z" fill="none" stroke="#800000" stroke-width=".21"/>
<g fill="none" stroke="#000" stroke-width=".25">
<path d="M25.1 117.8h7.6M25.1 115.2h7.6M25.1 112.7h7.6M25.1 110.1h7.6M25.1 107.6h7.6M25.1 105h7.6M25.1 102.5h7.6M42.9 117.8h7.6M42.9 115.2h7.6M42.9 112.7h7.6M42.9 110.1h7.6M42.9 107.6h7.6"/>
<path d="M42.9 105h7.6M42.9 102.5h7.6"/>
</g>
<circle cx="231.2" cy="26.2" r=".51" fill="#000080"/>
<circle cx="231.2" cy="26.2" r=".51" fill="none" stroke="#000080" stroke-width=".21"/>
<path d="M231.2 26.2v2.5M231.2 33.8v2.6" fill="none" stroke="#000" stroke-width=".25"/>
<circle cx="231.2" cy="26.2" r=".51" fill="#000080"/>
<circle cx="231.2" cy="26.2" r=".51" fill="none" stroke="#000080" stroke-width=".21"/>
<path d="M101 22.7h6v2h-6zM109.6 31.8h4M109.6 30.8h4M111.6 28.7v2.1M111.6 31.8v2M229.2 31.8h4M229.2 30.8h4M231.2 28.7v2.1M231.2 31.8v2" fill="none" stroke="#00f" stroke-width=".25"/>
<path d="M111.6 38.9v2.5M228.6 38.9h5.1M229.4 39.7h3.5M231.2 36.4v2.5M109.1 41.4h5M109.8 42.2h3.6M110.6 43h2M111.3 43.7h.5M230.1 40.4h2.1M230.9 41.2h.5" fill="none" stroke="#800000" stroke-width=".25"/>
<path d="M98.9 23.6h2M107.1 23.6h2M111.6 26.2v2.5M111.6 33.8v2.6" fill="none" stroke="#000" stroke-width=".25"/>
<path d="M226.1 74.5v5.1" fill="none" stroke="#000080" stroke-width=".25"/>
<circle cx="226.1" cy="77.1" r=".51" fill="#000080"/>
<circle cx="226.1" cy="77.1" r=".51" fill="none" stroke="#000080" stroke-width=".21"/>
<path d="M45.5 168.6h-2.6v2.6" fill="none" stroke="#000080" stroke-width=".25"/>
<circle cx="45.5" cy="168.6" r=".51" fill="#000080"/>
<circle cx="45.5" cy="168.6" r=".51" fill="none" stroke="#000080" stroke-width=".21"/>
<path d="M45.5 166.1v2.5h2.5v2.6" fill="none" stroke="#000080" stroke-width=".25"/>
<circle cx="45.5" cy="168.6" r=".51" fill="#000080"/>
<circle cx="45.5" cy="168.6" r=".51" fill="none" stroke="#000080" stroke-width=".21"/>
<path d="M76 168.6h-2.6v2.6" fill="none" stroke="#000080" stroke-width=".25"/>
<circle cx="76" cy="168.6" r=".51" fill="#000080"/>
<circle cx="76" cy="168.6" r=".51" fill="none" stroke="#000080" stroke-width=".21"/>
<path d="M106.5 183.9h-2.5v2.6" fill="none" stroke="#000080" stroke-width=".25"/>
<circle cx="104" cy="183.9" r=".51" fill="#000080"/>
<circle cx="104" cy="183.9" r=".51" fill="none" stroke="#000080" stroke-width=".21"/>
<path d="M226.1 92.3h10.2" fill="none" stroke="#000080" stroke-width=".25"/>
<circle cx="226.1" cy="92.3" r=".51" fill="#000080"/>
<circle cx="226.1" cy="92.3" r=".51" fill="none" stroke="#000080" stroke-width=".21"/>
<circle cx="233.7" cy="92.3" r=".51" fill="#000080"/>
<circle cx="233.7" cy="92.3" r=".51" fill="none" stroke="#000080" stroke-width=".21"/>
<path d="M271.9 97.4h2.5v22.9h-40.7v-17.8h2.6" fill="none" stroke="#000080" stroke-width=".25"/>
<circle cx="274.4" cy="97.4" r=".51" fill="#000080"/>
<circle cx="274.4" cy="97.4" r=".51" fill="none" stroke="#000080" stroke-width=".21"/>
<circle cx="274.4" cy="102.5" r=".51" fill="#000080"/>
<circle cx="274.4" cy="102.5" r=".51" fill="none" stroke="#000080" stroke-width=".21"/>
<path d="M226.1 105.1v2.5M106.5 176.3h-2.5v7.6" fill="none" stroke="#000080" stroke-width=".25"/>
<circle cx="104" cy="183.9" r=".51" fill="#000080"/>
<circle cx="104" cy="183.9" r=".51" fill="none" stroke="#000080" stroke-width=".21"/>
<path d="M226.1 89.8v5.1" fill="none" stroke="#000080" stroke-width=".25"/>
<circle cx="226.1" cy="92.3" r=".51" fill="#000080"/>
<circle cx="226.1" cy="92.3" r=".51" fill="none" stroke="#000080" stroke-width=".21"/>
<path d="M157.4 54.2h-2.6v2.5h2.6" fill="none" stroke="#000080" stroke-width=".25"/>
<circle cx="154.8" cy="56.7" r=".51" fill="#000080"/>
<circle cx="154.8" cy="56.7" r=".51" fill="none" stroke="#000080" stroke-width=".21"/>
<path d="M154.8 38.9h2.6M193 38.9h5.1v7.6h15.3v2.6M154.8 49.1h2.6M193 49.1h2.5" fill="none" stroke="#000080" stroke-width=".25"/>
<circle cx="213.4" cy="46.5" r=".51" fill="#000080"/>
<circle cx="213.4" cy="46.5" r=".51" fill="none" stroke="#000080" stroke-width=".21"/>
<path d="M147.2 26.2v2.5M147.2 38.9v2.5" fill="none" stroke="#000080" stroke-width=".25"/>
<circle cx="147.2" cy="26.2" r=".51" fill="#000080"/>
<circle cx="147.2" cy="26.2" r=".51" fill="none" stroke="#000080" stroke-width=".21"/>
<path d="M154.8 56.7v2.6" fill="none" stroke="#000080" stroke-width=".25"/>
<circle cx="154.8" cy="56.7" r=".51" fill="#000080"/>
<circle cx="154.8" cy="56.7" r=".51" fill="none" stroke="#000080" stroke-width=".21"/>
<path d="M213.4 44v2.5" fill="none" stroke="#000080" stroke-width=".25"/>
<circle cx="213.4" cy="46.5" r=".51" fill="#000080"/>
<circle cx="213.4" cy="46.5" r=".51" fill="none" stroke="#000080" stroke-width=".21"/>
<path d="M213.4 26.2v7.6" fill="none" stroke="#000080" stroke-width=".25"/>
<circle cx="213.4" cy="26.2" r=".51" fill="#000080"/>
<circle cx="213.4" cy="26.2" r=".51" fill="none" stroke="#000080" stroke-width=".21"/>
<path d="M193 26.2h25.5" fill="none" stroke="#000080" stroke-width=".25"/>
<circle cx="203.2" cy="26.2" r=".51" fill="#000080"/>
<circle cx="203.2" cy="26.2" r=".51" fill="none" stroke="#000080" stroke-width=".21"/>
<circle cx="213.4" cy="26.2" r=".51" fill="#000080"/>
<circle cx="213.4" cy="26.2" r=".51" fill="none" stroke="#000080" stroke-width=".21"/>
<circle cx="215.9" cy="26.2" r=".51" fill="#000080"/>
<circle cx="215.9" cy="26.2" r=".51" fill="none" stroke="#000080" stroke-width=".21"/>
<path d="M45.5 23.6v2.6h2.5" fill="none" stroke="#000080" stroke-width=".25"/>
<circle cx="45.5" cy="26.2" r=".51" fill="#000080"/>
<circle cx="45.5" cy="26.2" r=".51" fill="none" stroke="#000080" stroke-width=".21"/>
<circle cx="45.5" cy="23.6" r=".51" fill="#000080"/>
<circle cx="45.5" cy="23.6" r=".51" fill="none" stroke="#000080" stroke-width=".21"/>
<path d="M83.6 23.6h2.6v2.6h-2.6M86.2 49.1v2.5" fill="none" stroke="#000080" stroke-width=".25"/>
<circle cx="86.2" cy="26.2" r=".51" fill="#000080"/>
<circle cx="86.2" cy="26.2" r=".51" fill="none" stroke="#000080" stroke-width=".21"/>
<circle cx="86.2" cy="23.6" r=".51" fill="#000080"/>
<circle cx="86.2" cy="23.6" r=".51" fill="none" stroke="#000080" stroke-width=".21"/>
<path d="M96.3 36.4v2.5M76 166.1v2.5h2.5v2.6" fill="none" stroke="#000080" stroke-width=".25"/>
<circle cx="76" cy="168.6" r=".51" fill="#000080"/>
<circle cx="76" cy="168.6" r=".51" fill="none" stroke="#000080" stroke-width=".21"/>
<circle cx="78.5" cy="168.6" r=".51" fill="#000080"/>
<circle cx="78.5" cy="168.6" r=".51" fill="none" stroke="#000080" stroke-width=".21"/>
<path d="M129.4 23.6v2.6h2.5M147.2 26.2h10.2" fill="none" stroke="#000080" stroke-width=".25"/>
<circle cx="154.8" cy="26.2" r=".51" fill="#000080"/>
<circle cx="154.8" cy="26.2" r=".51" fill="none" stroke="#000080" stroke-width=".21"/>
<circle cx="147.2" cy="26.2" r=".51" fill="#000080"/>
<circle cx="147.2" cy="26.2" r=".51" fill="none" stroke="#000080" stroke-width=".21"/>
<path d="M45.5 23.6h2.5" fill="none" stroke="#000080" stroke-width=".25"/>
<circle cx="45.5" cy="23.6" r=".51" fill="#000080"/>
<circle cx="45.5" cy="23.6" r=".51" fill="none" stroke="#000080" stroke-width=".21"/>
<path d="M14.9 21.1v2.5h5.1" fill="none" stroke="#000080" stroke-width=".25"/>
<circle cx="17.5" cy="23.6" r=".51" fill="#000080"/>
<circle cx="17.5" cy="23.6" r=".51" fill="none" stroke="#000080" stroke-width=".21"/>
<path d="M35.3 23.6v2.6M35.3 36.4v5" fill="none" stroke="#000080" stroke-width=".25"/>
<circle cx="35.3" cy="23.6" r=".51" fill="#000080"/>
<circle cx="35.3" cy="23.6" r=".51" fill="none" stroke="#000080" stroke-width=".21"/>
<path d="M142.1 26.2h5.1" fill="none" stroke="#000080" stroke-width=".25"/>
<circle cx="147.2" cy="26.2" r=".51" fill="#000080"/>
<circle cx="147.2" cy="26.2" r=".51" fill="none" stroke="#000080" stroke-width=".21"/>
<circle cx="144.7" cy="26.2" r=".51" fill="#000080"/>
<circle cx="144.7" cy="26.2" r=".51" fill="none" stroke="#000080" stroke-width=".21"/>
<path d="M213.4 77.1v2.5M213.4 92.3h-7.7v2.6M213.4 105.1v2.5" fill="none" stroke="#000080" stroke-width=".25"/>
<circle cx="213.4" cy="92.3" r=".51" fill="#000080"/>
<circle cx="213.4" cy="92.3" r=".51" fill="none" stroke="#000080" stroke-width=".21"/>
<path d="M45.5 26.2v5.1h2.5" fill="none" stroke="#000080" stroke-width=".25"/>
<circle cx="45.5" cy="26.2" r=".51" fill="#000080"/>
<circle cx="45.5" cy="26.2" r=".51" fill="none" stroke="#000080" stroke-width=".21"/>
<path d="M45.5 38.9h2.5" fill="none" stroke="#000080" stroke-width=".25"/>
<circle cx="45.5" cy="38.9" r=".51" fill="#000080"/>
<circle cx="45.5" cy="38.9" r=".51" fill="none" stroke="#000080" stroke-width=".21"/>
<path d="M154.8 26.2v2.5h2.6" fill="none" stroke="#000080" stroke-width=".25"/>
<circle cx="154.8" cy="26.2" r=".51" fill="#000080"/>
<circle cx="154.8" cy="26.2" r=".51" fill="none" stroke="#000080" stroke-width=".21"/>
<path d="M83.6 36.4h2.6v2.5M32.7 79.6h12.8M32.7 72h12.8M32.7 74.5h12.8M32.7 69.4h12.8M32.7 82.1h12.8M32.7 84.7h12.8M32.7 89.8h12.8M213.4 89.8v5.1" fill="none" stroke="#000080" stroke-width=".25"/>
<circle cx="213.4" cy="92.3" r=".51" fill="#000080"/>
<circle cx="213.4" cy="92.3" r=".51" fill="none" stroke="#000080" stroke-width=".21"/>
<path d="M226.1 77.1h7.6v2.5" fill="none" stroke="#000080" stroke-width=".25"/>
<circle cx="226.1" cy="77.1" r=".51" fill="#000080"/>
<circle cx="226.1" cy="77.1" r=".51" fill="none" stroke="#000080" stroke-width=".21"/>
<path d="M233.7 89.8v2.5" fill="none" stroke="#000080" stroke-width=".25"/>
<circle cx="233.7" cy="92.3" r=".51" fill="#000080"/>
<circle cx="233.7" cy="92.3" r=".51" fill="none" stroke="#000080" stroke-width=".21"/>
<path d="M106.5 163.6h-25.4v5h-2.6" fill="none" stroke="#000080" stroke-width=".25"/>
<circle cx="86.2" cy="163.6" r=".51" fill="#000080"/>
<circle cx="86.2" cy="163.6" r=".51" fill="none" stroke="#000080" stroke-width=".21"/>
<circle cx="78.5" cy="168.6" r=".51" fill="#000080"/>
<circle cx="78.5" cy="168.6" r=".51" fill="none" stroke="#000080" stroke-width=".21"/>
<path d="M73.4 181.4v2.5" fill="none" stroke="#000080" stroke-width=".25"/>
<circle cx="73.4" cy="183.9" r=".51" fill="#000080"/>
<circle cx="73.4" cy="183.9" r=".51" fill="none" stroke="#000080" stroke-width=".21"/>
<path d="M42.9 181.4v2.5" fill="none" stroke="#000080" stroke-width=".25"/>
<circle cx="42.9" cy="183.9" r=".51" fill="#000080"/>
<circle cx="42.9" cy="183.9" r=".51" fill="none" stroke="#000080" stroke-width=".21"/>
<path d="M60.7 166.1v2.5" fill="none" stroke="#000080" stroke-width=".25"/>
<circle cx="60.7" cy="168.6" r=".51" fill="#000080"/>
<circle cx="60.7" cy="168.6" r=".51" fill="none" stroke="#000080" stroke-width=".21"/>
<path d="M48 181.4v7.6h-12.7" fill="none" stroke="#000080" stroke-width=".25"/>
<circle cx="48" cy="189" r=".51" fill="#000080"/>
<circle cx="48" cy="189" r=".51" fill="none" stroke="#000080" stroke-width=".21"/>
<path d="M48 189h2.5" fill="none" stroke="#000080" stroke-width=".25"/>
<circle cx="48" cy="189" r=".51" fill="#000080"/>
<circle cx="48" cy="189" r=".51" fill="none" stroke="#000080" stroke-width=".21"/>
<path d="M106.5 171.2h-7.6v17.8h-20.4v-7.6" fill="none" stroke="#000080" stroke-width=".25"/>
<circle cx="83.6" cy="189" r=".51" fill="#000080"/>
<circle cx="83.6" cy="189" r=".51" fill="none" stroke="#000080" stroke-width=".21"/>
<circle cx="78.5" cy="189" r=".51" fill="#000080"/>
<circle cx="78.5" cy="189" r=".51" fill="none" stroke="#000080" stroke-width=".21"/>
<path d="M60.7 189h17.8" fill="none" stroke="#000080" stroke-width=".25"/>
<circle cx="78.5" cy="189" r=".51" fill="#000080"/>
<circle cx="78.5" cy="189" r=".51" fill="none" stroke="#000080" stroke-width=".21"/>
<path d="M274.4 97.4h2.6" fill="none" stroke="#000080" stroke-width=".25"/>
<circle cx="274.4" cy="97.4" r=".51" fill="#000080"/>
<circle cx="274.4" cy="97.4" r=".51" fill="none" stroke="#000080" stroke-width=".21"/>
<path d="M106.5 168.6h-10.2v15.3h-25.4" fill="none" stroke="#000080" stroke-width=".25"/>
<circle cx="73.4" cy="183.9" r=".51" fill="#000080"/>
<circle cx="73.4" cy="183.9" r=".51" fill="none" stroke="#000080" stroke-width=".21"/>
<circle cx="91.2" cy="183.9" r=".51" fill="#000080"/>
<circle cx="91.2" cy="183.9" r=".51" fill="none" stroke="#000080" stroke-width=".21"/>
<path d="M65.8 176.3v-7.7h-10.2v12.8" fill="none" stroke="#000080" stroke-width=".25"/>
<circle cx="60.7" cy="168.6" r=".51" fill="#000080"/>
<circle cx="60.7" cy="168.6" r=".51" fill="none" stroke="#000080" stroke-width=".21"/>
<path d="M48 36.4h-2.5v5" fill="none" stroke="#000080" stroke-width=".25"/>
<circle cx="45.5" cy="38.9" r=".51" fill="#000080"/>
<circle cx="45.5" cy="38.9" r=".51" fill="none" stroke="#000080" stroke-width=".21"/>
<path d="M274.4 143.2h7.6M165 171.2h7.7M165 166.1h7.7M165 176.3h7.7M182.8 176.3h8.9M182.8 171.2h8.9M182.8 166.1h8.9M274.4 163.6h2.6v2.5M165 181.4h7.7M182.8 181.4h8.9" fill="none" stroke="#000080" stroke-width=".25"/>
<circle cx="277" cy="163.6" r=".51" fill="#000080"/>
<circle cx="277" cy="163.6" r=".51" fill="none" stroke="#000080" stroke-width=".21"/>
<path d="M274.4 158.5h2.6v5.1" fill="none" stroke="#000080" stroke-width=".25"/>
<circle cx="277" cy="161" r=".51" fill="#000080"/>
<circle cx="277" cy="161" r=".51" fill="none" stroke="#000080" stroke-width=".21"/>
<circle cx="277" cy="163.6" r=".51" fill="#000080"/>
<circle cx="277" cy="163.6" r=".51" fill="none" stroke="#000080" stroke-width=".21"/>
<path d="M274.4 161h2.6" fill="none" stroke="#000080" stroke-width=".25"/>
<circle cx="277" cy="161" r=".51" fill="#000080"/>
<circle cx="277" cy="161" r=".51" fill="none" stroke="#000080" stroke-width=".21"/>
<path d="M208.3 130.5v2.5h20.3M221 158.5h7.6M221 161h7.6" fill="none" stroke="#000080" stroke-width=".25"/>
<circle cx="210.8" cy="133" r=".51" fill="#000080"/>
<circle cx="210.8" cy="133" r=".51" fill="none" stroke="#000080" stroke-width=".21"/>
<path d="M147.2 148.3h-2.5v2.5M221 143.2h7.6M147.2 171.2h10.2M147.2 166.1h10.2M147.2 176.3h10.2M147.2 181.4h10.2" fill="none" stroke="#000080" stroke-width=".25"/>
<circle cx="144.7" cy="148.3" r=".51" fill="#000080"/>
<circle cx="144.7" cy="148.3" r=".51" fill="none" stroke="#000080" stroke-width=".21"/>
<path d="M147.2 135.6h-2.5v12.7" fill="none" stroke="#000080" stroke-width=".25"/>
<circle cx="144.7" cy="143.2" r=".51" fill="#000080"/>
<circle cx="144.7" cy="143.2" r=".51" fill="none" stroke="#000080" stroke-width=".21"/>
<circle cx="144.7" cy="148.3" r=".51" fill="#000080"/>
<circle cx="144.7" cy="148.3" r=".51" fill="none" stroke="#000080" stroke-width=".21"/>
<path d="M35.3 183.9h25.4" fill="none" stroke="#000080" stroke-width=".25"/>
<circle cx="42.9" cy="183.9" r=".51" fill="#000080"/>
<circle cx="42.9" cy="183.9" r=".51" fill="none" stroke="#000080" stroke-width=".21"/>
<path d="M144.7 127.9h2.5M144.7 130.5h2.5M144.7 143.2h2.5" fill="none" stroke="#000080" stroke-width=".25"/>
<circle cx="144.7" cy="143.2" r=".51" fill="#000080"/>
<circle cx="144.7" cy="143.2" r=".51" fill="none" stroke="#000080" stroke-width=".21"/>
<path d="M187.9 143.2h2.6" fill="none" stroke="#000080" stroke-width=".25"/>
<circle cx="190.5" cy="143.2" r=".51" fill="#000080"/>
<circle cx="190.5" cy="143.2" r=".51" fill="none" stroke="#000080" stroke-width=".21"/>
<path d="M187.9 145.8h2.6" fill="none" stroke="#000080" stroke-width=".25"/>
<circle cx="190.5" cy="145.8" r=".51" fill="#000080"/>
<circle cx="190.5" cy="145.8" r=".51" fill="none" stroke="#000080" stroke-width=".21"/>
<path d="M187.9 148.3h2.6" fill="none" stroke="#000080" stroke-width=".25"/>
<circle cx="190.5" cy="148.3" r=".51" fill="#000080"/>
<circle cx="190.5" cy="148.3" r=".51" fill="none" stroke="#000080" stroke-width=".21"/>
<path d="M187.9 140.7h2.6v10.1" fill="none" stroke="#000080" stroke-width=".25"/>
<circle cx="190.5" cy="143.2" r=".51" fill="#000080"/>
<circle cx="190.5" cy="143.2" r=".51" fill="none" stroke="#000080" stroke-width=".21"/>
<circle cx="190.5" cy="145.8" r=".51" fill="#000080"/>
<circle cx="190.5" cy="145.8" r=".51" fill="none" stroke="#000080" stroke-width=".21"/>
<circle cx="190.5" cy="148.3" r=".51" fill="#000080"/>
<circle cx="190.5" cy="148.3" r=".51" fill="none" stroke="#000080" stroke-width=".21"/>
<path d="M116.7 140.7h30.5" fill="none" stroke="#000080" stroke-width=".25"/>
<circle cx="126.9" cy="140.7" r=".51" fill="#000080"/>
<circle cx="126.9" cy="140.7" r=".51" fill="none" stroke="#000080" stroke-width=".21"/>
<circle cx="139.6" cy="140.7" r=".51" fill="#000080"/>
<circle cx="139.6" cy="140.7" r=".51" fill="none" stroke="#000080" stroke-width=".21"/>
<path d="M129.4 117.8v5.1h17.8" fill="none" stroke="#000080" stroke-width=".25"/>
<circle cx="134.5" cy="122.9" r=".51" fill="#000080"/>
<circle cx="134.5" cy="122.9" r=".51" fill="none" stroke="#000080" stroke-width=".21"/>
<path d="M101.4 138.1v2.6h5.1M147.2 120.3h-28v2.6" fill="none" stroke="#000080" stroke-width=".25"/>
<circle cx="119.2" cy="120.3" r=".51" fill="#000080"/>
<circle cx="119.2" cy="120.3" r=".51" fill="none" stroke="#000080" stroke-width=".21"/>
<path d="M114.1 117.8v2.5h5.1" fill="none" stroke="#000080" stroke-width=".25"/>
<circle cx="119.2" cy="120.3" r=".51" fill="#000080"/>
<circle cx="119.2" cy="120.3" r=".51" fill="none" stroke="#000080" stroke-width=".21"/>
<path d="M86.2 26.2v5.1h-2.6" fill="none" stroke="#000080" stroke-width=".25"/>
<circle cx="86.2" cy="26.2" r=".51" fill="#000080"/>
<circle cx="86.2" cy="26.2" r=".51" fill="none" stroke="#000080" stroke-width=".21"/>
<path d="M76 138.1h5.1M187.9 120.3h10.2M187.9 125.4h10.2M187.9 130.5h10.2M187.9 135.6h10.2M221 138.1h7.6M274.4 138.1h7.6M45.5 145.7h-2.6v2.6M221 153.4h7.6M221 148.3h7.6M274.4 153.4h7.6M274.4 148.3h7.6" fill="none" stroke="#000080" stroke-width=".25"/>
<circle cx="81.1" cy="138.1" r=".51" fill="#000080"/>
<circle cx="81.1" cy="138.1" r=".51" fill="none" stroke="#000080" stroke-width=".21"/>
<circle cx="78.5" cy="138.1" r=".51" fill="#000080"/>
<circle cx="78.5" cy="138.1" r=".51" fill="none" stroke="#000080" stroke-width=".21"/>
<path d="M88.7 135.6v2.5h-7.6" fill="none" stroke="#000080" stroke-width=".25"/>
<circle cx="81.1" cy="138.1" r=".51" fill="#000080"/>
<circle cx="81.1" cy="138.1" r=".51" fill="none" stroke="#000080" stroke-width=".21"/>
<path d="M14.9 135.6v2.5h5.1" fill="none" stroke="#000080" stroke-width=".25"/>
<circle cx="17.5" cy="138.1" r=".51" fill="#000080"/>
<circle cx="17.5" cy="138.1" r=".51" fill="none" stroke="#000080" stroke-width=".21"/>
<path d="M42.9 138.1v2.6h2.6" fill="none" stroke="#000080" stroke-width=".25"/>
<circle cx="42.9" cy="138.1" r=".51" fill="#000080"/>
<circle cx="42.9" cy="138.1" r=".51" fill="none" stroke="#000080" stroke-width=".21"/>
<path d="M195.5 77.1v2.5h-2.5M93.8 92.3v5.1M180.3 92.3v5.1" fill="none" stroke="#000080" stroke-width=".25"/>
<circle cx="195.5" cy="79.6" r=".51" fill="#000080"/>
<circle cx="195.5" cy="79.6" r=".51" fill="none" stroke="#000080" stroke-width=".21"/>
<path d="M101.4 79.6h2.6" fill="none" stroke="#000080" stroke-width=".25"/>
<circle cx="101.4" cy="79.6" r=".51" fill="#000080"/>
<circle cx="101.4" cy="79.6" r=".51" fill="none" stroke="#000080" stroke-width=".21"/>
<path d="M73.4 77.1v2.5M119.2 79.6h2.6M152.3 89.8v7.6" fill="none" stroke="#000080" stroke-width=".25"/>
<circle cx="73.4" cy="79.6" r=".51" fill="#000080"/>
<circle cx="73.4" cy="79.6" r=".51" fill="none" stroke="#000080" stroke-width=".21"/>
<path d="M180.3 79.6v2.5" fill="none" stroke="#000080" stroke-width=".25"/>
<circle cx="180.3" cy="79.6" r=".51" fill="#000080"/>
<circle cx="180.3" cy="79.6" r=".51" fill="none" stroke="#000080" stroke-width=".21"/>
<path d="M165 79.6v5.1M175.2 84.7v2.5" fill="none" stroke="#000080" stroke-width=".25"/>
<circle cx="165" cy="79.6" r=".51" fill="#000080"/>
<circle cx="165" cy="79.6" r=".51" fill="none" stroke="#000080" stroke-width=".21"/>
<path d="M152.3 79.6h12.7" fill="none" stroke="#000080" stroke-width=".25"/>
<circle cx="165" cy="79.6" r=".51" fill="#000080"/>
<circle cx="165" cy="79.6" r=".51" fill="none" stroke="#000080" stroke-width=".21"/>
<path d="M152.3 84.7h10.2v2.5h2.5" fill="none" stroke="#000080" stroke-width=".25"/>
<circle cx="162.5" cy="87.2" r=".51" fill="#000080"/>
<circle cx="162.5" cy="87.2" r=".51" fill="none" stroke="#000080" stroke-width=".21"/>
<path d="M165 79.6h17.8" fill="none" stroke="#000080" stroke-width=".25"/>
<circle cx="180.3" cy="79.6" r=".51" fill="#000080"/>
<circle cx="180.3" cy="79.6" r=".51" fill="none" stroke="#000080" stroke-width=".21"/>
<circle cx="175.2" cy="79.6" r=".51" fill="#000080"/>
<circle cx="175.2" cy="79.6" r=".51" fill="none" stroke="#000080" stroke-width=".21"/>
<circle cx="165" cy="79.6" r=".51" fill="#000080"/>
<circle cx="165" cy="79.6" r=".51" fill="none" stroke="#000080" stroke-width=".21"/>
<path d="M53.1 56.7h-5.1v7.6h-15.3M63.3 56.7h2.5M63.3 64.3h2.5" fill="none" stroke="#000080" stroke-width=".25"/>
<circle cx="37.8" cy="64.3" r=".51" fill="#000080"/>
<circle cx="37.8" cy="64.3" r=".51" fill="none" stroke="#000080" stroke-width=".21"/>
<circle cx="48" cy="64.3" r=".51" fill="#000080"/>
<circle cx="48" cy="64.3" r=".51" fill="none" stroke="#000080" stroke-width=".21"/>
<path d="M48 64.3h5.1" fill="none" stroke="#000080" stroke-width=".25"/>
<circle cx="48" cy="64.3" r=".51" fill="#000080"/>
<circle cx="48" cy="64.3" r=".51" fill="none" stroke="#000080" stroke-width=".21"/>
<path d="M12.4 105h12.7M12.4 107.6h12.7M12.4 102.5h12.7M12.4 112.7h12.7M12.4 115.2h12.7M12.4 110.1h12.7M50.5 105h2.6" fill="none" stroke="#000080" stroke-width=".25"/>
<circle cx="53.1" cy="105" r=".51" fill="#000080"/>
<circle cx="53.1" cy="105" r=".51" fill="none" stroke="#000080" stroke-width=".21"/>
<path d="M50.5 112.7h2.6" fill="none" stroke="#000080" stroke-width=".25"/>
<circle cx="53.1" cy="112.7" r=".51" fill="#000080"/>
<circle cx="53.1" cy="112.7" r=".51" fill="none" stroke="#000080" stroke-width=".21"/>
<path d="M101.4 84.7v5.1h20.4M12.4 117.8h12.7M50.5 117.8h10.2" fill="none" stroke="#000080" stroke-width=".25"/>
<circle cx="101.4" cy="84.7" r=".51" fill="#000080"/>
<circle cx="101.4" cy="84.7" r=".51" fill="none" stroke="#000080" stroke-width=".21"/>
<path d="M53.1 110.1v5.1h-2.6" fill="none" stroke="#000080" stroke-width=".25"/>
<circle cx="53.1" cy="110.1" r=".51" fill="#000080"/>
<circle cx="53.1" cy="110.1" r=".51" fill="none" stroke="#000080" stroke-width=".21"/>
<circle cx="53.1" cy="112.7" r=".51" fill="#000080"/>
<circle cx="53.1" cy="112.7" r=".51" fill="none" stroke="#000080" stroke-width=".21"/>
<path d="M50.5 110.1h5.1" fill="none" stroke="#000080" stroke-width=".25"/>
<circle cx="53.1" cy="110.1" r=".51" fill="#000080"/>
<circle cx="53.1" cy="110.1" r=".51" fill="none" stroke="#000080" stroke-width=".21"/>
<path d="M53.1 102.5v5.1h-2.6" fill="none" stroke="#000080" stroke-width=".25"/>
<circle cx="53.1" cy="105" r=".51" fill="#000080"/>
<circle cx="53.1" cy="105" r=".51" fill="none" stroke="#000080" stroke-width=".21"/>
<circle cx="53.1" cy="102.5" r=".51" fill="#000080"/>
<circle cx="53.1" cy="102.5" r=".51" fill="none" stroke="#000080" stroke-width=".21"/>
<path d="M50.5 102.5h5.1" fill="none" stroke="#000080" stroke-width=".25"/>
<circle cx="53.1" cy="102.5" r=".51" fill="#000080"/>
<circle cx="53.1" cy="102.5" r=".51" fill="none" stroke="#000080" stroke-width=".21"/>
<path d="M30.2 138.1h15.3" fill="none" stroke="#000080" stroke-width=".25"/>
<circle cx="32.7" cy="138.1" r=".51" fill="#000080"/>
<circle cx="32.7" cy="138.1" r=".51" fill="none" stroke="#000080" stroke-width=".21"/>
<circle cx="35.3" cy="138.1" r=".51" fill="#000080"/>
<circle cx="35.3" cy="138.1" r=".51" fill="none" stroke="#000080" stroke-width=".21"/>
<circle cx="42.9" cy="138.1" r=".51" fill="#000080"/>
<circle cx="42.9" cy="138.1" r=".51" fill="none" stroke="#000080" stroke-width=".21"/>
<path d="M70.9 79.6h5.1" fill="none" stroke="#000080" stroke-width=".25"/>
<circle cx="73.4" cy="79.6" r=".51" fill="#000080"/>
<circle cx="73.4" cy="79.6" r=".51" fill="none" stroke="#000080" stroke-width=".21"/>
<path d="M101.4 79.6v5.1h20.4" fill="none" stroke="#000080" stroke-width=".25"/>
<circle cx="101.4" cy="79.6" r=".51" fill="#000080"/>
<circle cx="101.4" cy="79.6" r=".51" fill="none" stroke="#000080" stroke-width=".21"/>
<circle cx="101.4" cy="84.7" r=".51" fill="#000080"/>
<circle cx="101.4" cy="84.7" r=".51" fill="none" stroke="#000080" stroke-width=".21"/>
<path d="M93.8 79.6v2.5" fill="none" stroke="#000080" stroke-width=".25"/>
<circle cx="93.8" cy="79.6" r=".51" fill="#000080"/>
<circle cx="93.8" cy="79.6" r=".51" fill="none" stroke="#000080" stroke-width=".21"/>
<path d="M86.2 79.6h15.2" fill="none" stroke="#000080" stroke-width=".25"/>
<circle cx="88.7" cy="79.6" r=".51" fill="#000080"/>
<circle cx="88.7" cy="79.6" r=".51" fill="none" stroke="#000080" stroke-width=".21"/>
<circle cx="93.8" cy="79.6" r=".51" fill="#000080"/>
<circle cx="93.8" cy="79.6" r=".51" fill="none" stroke="#000080" stroke-width=".21"/>
<circle cx="101.4" cy="79.6" r=".51" fill="#000080"/>
<circle cx="101.4" cy="79.6" r=".51" fill="none" stroke="#000080" stroke-width=".21"/>
<path d="M243.9 23.6v2.6h-15.3" fill="none" stroke="#000080" stroke-width=".25"/>
<circle cx="241.3" cy="26.2" r=".51" fill="#000080"/>
<circle cx="241.3" cy="26.2" r=".51" fill="none" stroke="#000080" stroke-width=".21"/>
<circle cx="231.2" cy="26.2" r=".51" fill="#000080"/>
<circle cx="231.2" cy="26.2" r=".51" fill="none" stroke="#000080" stroke-width=".21"/>
<path d="M111.6 23.6v2.6M111.6 36.4v2.5" fill="none" stroke="#000080" stroke-width=".25"/>
<circle cx="111.6" cy="23.6" r=".51" fill="#000080"/>
<circle cx="111.6" cy="23.6" r=".51" fill="none" stroke="#000080" stroke-width=".21"/>
<path d="M30.2 23.6h15.3" fill="none" stroke="#000080" stroke-width=".25"/>
<circle cx="35.3" cy="23.6" r=".51" fill="#000080"/>
<circle cx="35.3" cy="23.6" r=".51" fill="none" stroke="#000080" stroke-width=".21"/>
<circle cx="40.4" cy="23.6" r=".51" fill="#000080"/>
<circle cx="40.4" cy="23.6" r=".51" fill="none" stroke="#000080" stroke-width=".21"/>
<circle cx="45.5" cy="23.6" r=".51" fill="#000080"/>
<circle cx="45.5" cy="23.6" r=".51" fill="none" stroke="#000080" stroke-width=".21"/>
<path d="M86.2 23.6h12.7" fill="none" stroke="#000080" stroke-width=".25"/>
<circle cx="86.2" cy="23.6" r=".51" fill="#000080"/>
<circle cx="86.2" cy="23.6" r=".51" fill="none" stroke="#000080" stroke-width=".21"/>
<circle cx="96.3" cy="23.6" r=".51" fill="#000080"/>
<circle cx="96.3" cy="23.6" r=".51" fill="none" stroke="#000080" stroke-width=".21"/>
<path d="M96.3 23.6v2.6" fill="none" stroke="#000080" stroke-width=".25"/>
<circle cx="96.3" cy="23.6" r=".51" fill="#000080"/>
<circle cx="96.3" cy="23.6" r=".51" fill="none" stroke="#000080" stroke-width=".21"/>
<path d="M119.2 21.1v2.5h-10.1" fill="none" stroke="#000080" stroke-width=".25"/>
<circle cx="116.7" cy="23.6" r=".51" fill="#000080"/>
<circle cx="116.7" cy="23.6" r=".51" fill="none" stroke="#000080" stroke-width=".21"/>
<circle cx="111.6" cy="23.6" r=".51" fill="#000080"/>
<circle cx="111.6" cy="23.6" r=".51" fill="none" stroke="#000080" stroke-width=".21"/>
<use href="#words"/>
</svg>
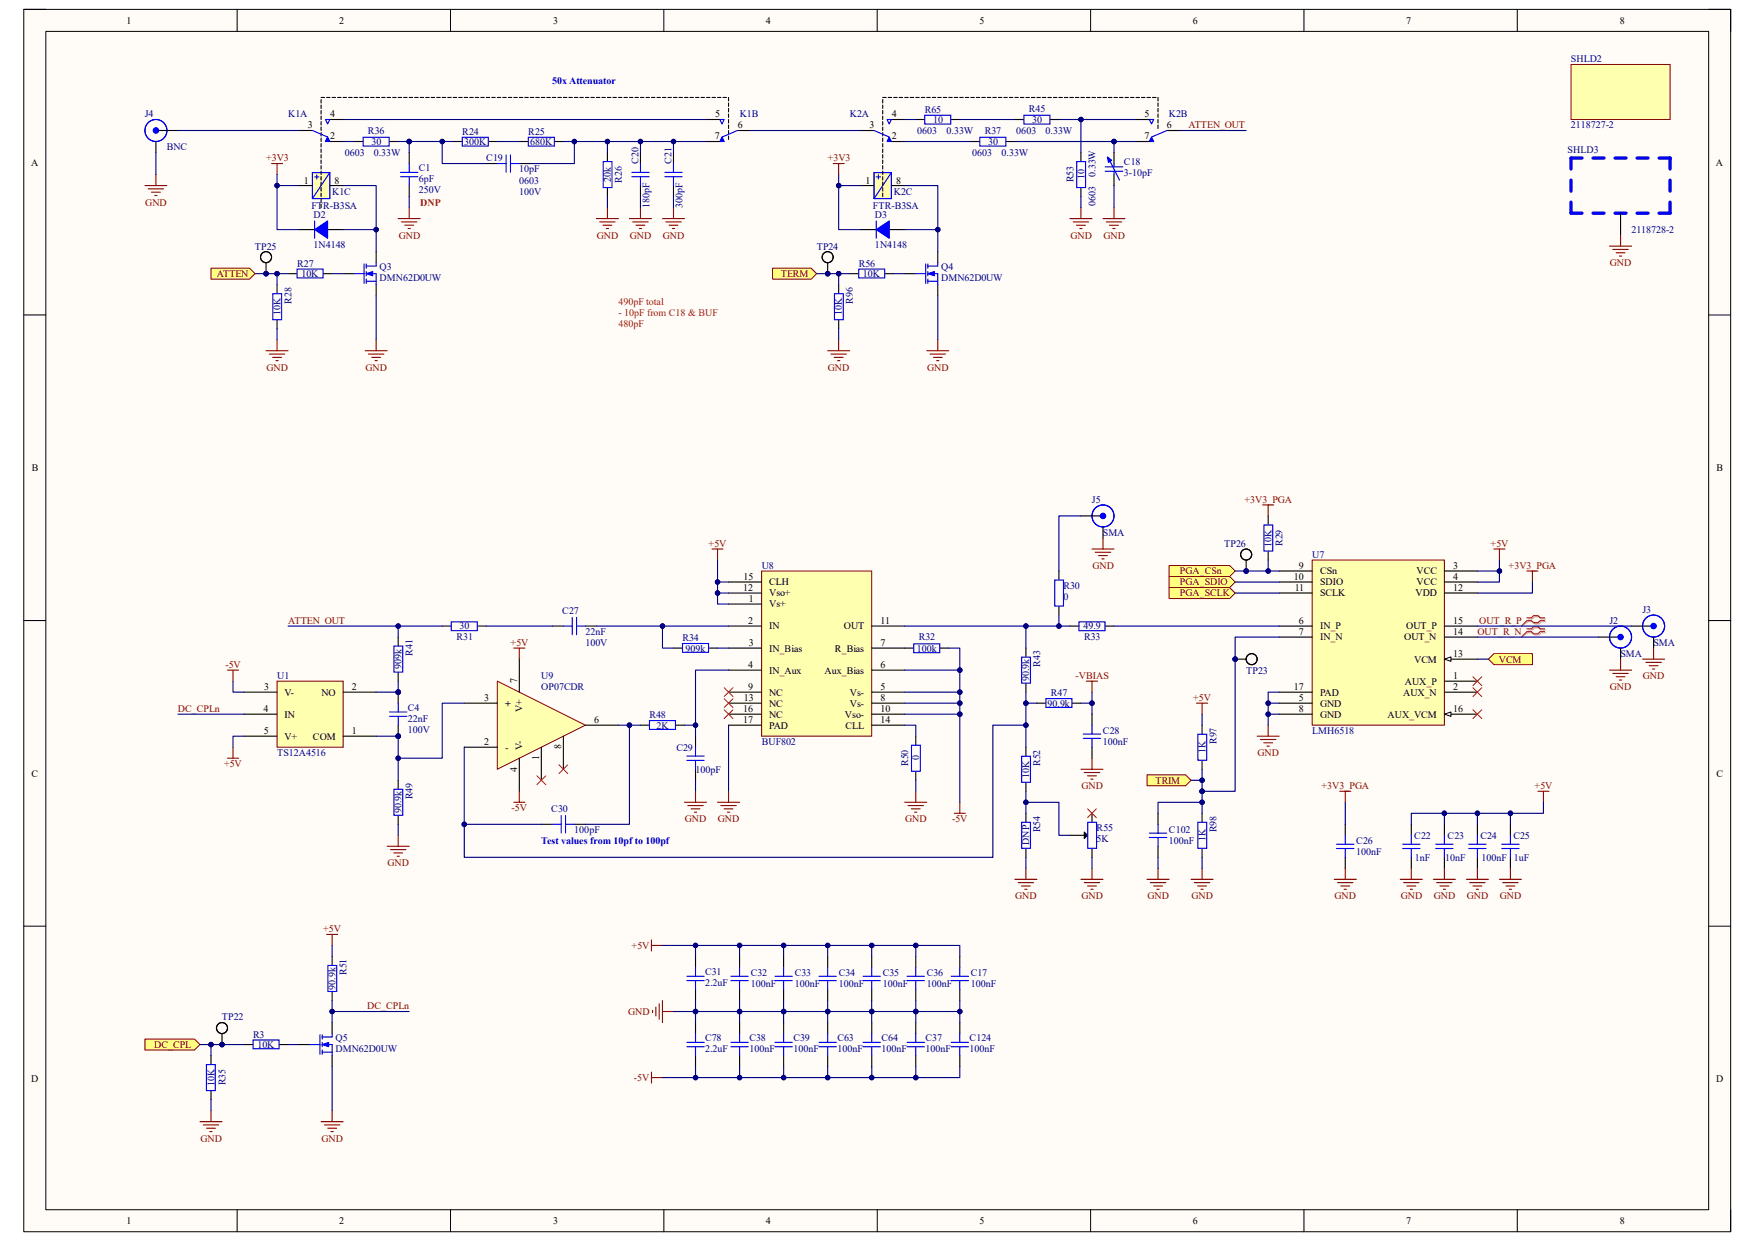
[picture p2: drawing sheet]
<svg xmlns="http://www.w3.org/2000/svg" width="297mm" height="210mm" viewBox="0 0 297 210" stroke-linecap="round" stroke-linejoin="round" font-family="sans-serif">
<defs><g id="words">
<g font-size="1.7">
<text x="21.4" y="4">1</text>
<text x="57.4" y="4">2</text>
<text x="93.6" y="4">3</text>
<text x="129.6" y="4">4</text>
<text x="165.8" y="4">5</text>
<text x="201.8" y="4">6</text>
<text x="238" y="4">7</text>
<text x="274.1" y="4">8</text>
<text x="52.1" y="21.7">3</text>
<text x="55.9" y="23.6">2</text>
<text x="55.9" y="19.9">4</text>
<text x="121" y="23.6">7</text>
<text x="121" y="19.9">5</text>
<text x="124.8" y="21.7">6</text>
<text x="147.2" y="21.7">3</text>
<text x="150.9" y="23.6">2</text>
<text x="150.9" y="19.9">4</text>
<text x="193.7" y="23.6">7</text>
<text x="193.7" y="19.9">5</text>
<text x="197.5" y="21.7">6</text>
<text x="5.3" y="28">A</text>
<text x="290.4" y="28">A</text>
<text x="51.4" y="31.1">1</text>
<text x="56.6" y="31.1">8</text>
<text x="146.5" y="31.1">1</text>
<text x="151.6" y="31.1">8</text>
<text x="5.4" y="79.8">B</text>
<text x="290.5" y="79.8">B</text>
<text x="125.8" y="100">12</text>
<text x="125.8" y="98.1">15</text>
<text x="126.7" y="101.9">1</text>
<text x="130.2" y="100.9">Vso+</text>
<text x="130.2" y="99.1">CLH</text>
<text x="218.9" y="98.1">10</text>
<text x="219.1" y="100">11</text>
<text x="219.8" y="96.3">9</text>
<text x="223.4" y="97.2">CSn</text>
<text x="223.4" y="99.1">SDIO</text>
<text x="223.4" y="100.9">SCLK</text>
<text x="239.6" y="100.9">VDD</text>
<text x="239.7" y="97.2">VCC</text>
<text x="239.7" y="99.1">VCC</text>
<text x="245.9" y="100">12</text>
<text x="245.9" y="96.3">3</text>
<text x="245.9" y="98.1">4</text>
<text x="126.6" y="105.6">2</text>
<text x="130.2" y="102.8">Vs+</text>
<text x="130.2" y="106.5">IN</text>
<text x="142.8" y="106.5">OUT</text>
<text x="149" y="105.6">11</text>
<text x="219.8" y="105.6">6</text>
<text x="219.8" y="107.4">7</text>
<text x="223.4" y="106.5">IN_P</text>
<text x="238" y="106.5">OUT_P</text>
<text x="245.9" y="107.4">14</text>
<text x="245.9" y="105.6">15</text>
<text x="126.6" y="113.1">4</text>
<text x="126.7" y="109.3">3</text>
<text x="130.2" y="110.3">IN_Bias</text>
<text x="141.3" y="110.3">R_Bias</text>
<text x="149" y="113.1">6</text>
<text x="149" y="109.3">7</text>
<text x="223.4" y="108.4">IN_N</text>
<text x="237.6" y="108.4">OUT_N</text>
<text x="239.3" y="112.1">VCM</text>
<text x="245.9" y="111.2">13</text>
<text x="44.7" y="116.8">3</text>
<text x="48.2" y="117.7">V-</text>
<text x="54.4" y="117.7">NO</text>
<text x="59.6" y="116.8">2</text>
<text x="82" y="118.7">3</text>
<text x="85.5" y="119.6">+</text>
<text x="87.5" y="115.7" transform="rotate(-90 87.5 115.7)">7</text>
<text x="125.9" y="118.7">13</text>
<text x="126.6" y="116.8">9</text>
<text x="130.2" y="114">IN_Aux</text>
<text x="130.2" y="117.7">NC</text>
<text x="130.2" y="119.6">NC</text>
<text x="139.5" y="114">Aux_Bias</text>
<text x="143.8" y="117.7">Vs-</text>
<text x="143.8" y="119.6">Vs-</text>
<text x="149" y="116.8">5</text>
<text x="149" y="118.7">8</text>
<text x="219" y="116.8">17</text>
<text x="219.8" y="118.7">5</text>
<text x="223.4" y="119.6">GND</text>
<text x="223.4" y="117.7">PAD</text>
<text x="237.4" y="117.7">AUX_N</text>
<text x="237.7" y="115.9">AUX_P</text>
<text x="245.9" y="114.9">1</text>
<text x="245.9" y="116.8">2</text>
<text x="44.6" y="120.5">4</text>
<text x="44.7" y="124.2">5</text>
<text x="48.2" y="125.2">V+</text>
<text x="48.2" y="121.5">IN</text>
<text x="53" y="125.2">COM</text>
<text x="59.6" y="124.2">1</text>
<text x="88.4" y="120.6" transform="rotate(-90 88.4 120.6)">V+</text>
<text x="100.5" y="122.4">6</text>
<text x="125.8" y="120.5">16</text>
<text x="125.8" y="122.4">17</text>
<text x="130.2" y="121.5">NC</text>
<text x="130.2" y="123.3">PAD</text>
<text x="143" y="121.5">Vso-</text>
<text x="143.1" y="123.3">CLL</text>
<text x="149" y="120.5">10</text>
<text x="149" y="122.4">14</text>
<text x="219.8" y="120.5">8</text>
<text x="223.4" y="121.5">GND</text>
<text x="234.8" y="121.5">AUX_VCM</text>
<text x="245.9" y="120.5">16</text>
<text x="5.3" y="131.4">C</text>
<text x="81.9" y="126.1">2</text>
<text x="85.5" y="127">-</text>
<text x="87.5" y="130.6" transform="rotate(-90 87.5 130.6)">4</text>
<text x="88.4" y="127" transform="rotate(-90 88.4 127)">V-</text>
<text x="91.2" y="128.6" transform="rotate(-90 91.2 128.6)">1</text>
<text x="95" y="126.8" transform="rotate(-90 95 126.8)">8</text>
<text x="290.5" y="131.4">C</text>
<text x="5.3" y="183.2">D</text>
<text x="290.4" y="183.2">D</text>
<text x="21.4" y="207.2">1</text>
<text x="57.4" y="207.2">2</text>
<text x="93.6" y="207.2">3</text>
<text x="129.6" y="207.2">4</text>
<text x="165.8" y="207.2">5</text>
<text x="201.8" y="207.2">6</text>
<text x="238" y="207.2">7</text>
<text x="274.1" y="207.2">8</text>
</g>
<g font-size="1.7" fill="#000080">
<text x="265.9" y="10.5">SHLD2</text>
<text x="24.5" y="19.9">J4</text>
<text x="48.8" y="19.9">K1A</text>
<text x="62.3" y="22.6">R36</text>
<text x="78.2" y="22.9">R24</text>
<text x="89.4" y="22.9">R25</text>
<text x="125.2" y="19.9">K1B</text>
<text x="143.8" y="19.9">K2A</text>
<text x="155.2" y="22.6">0603</text>
<text x="156.5" y="19.1">R65</text>
<text x="157.9" y="20.8">10</text>
<text x="160.2" y="22.6">0.33W</text>
<text x="166.7" y="22.6">R37</text>
<text x="172" y="22.6">0603</text>
<text x="174.1" y="18.9">R45</text>
<text x="174.7" y="20.8">30</text>
<text x="177" y="22.6">0.33W</text>
<text x="197.8" y="19.9">K2B</text>
<text x="265.9" y="21.7">2118727-2</text>
<text x="28.2" y="25.4">BNC</text>
<text x="58.3" y="26.4">0603</text>
<text x="62.9" y="24.5">30</text>
<text x="63.2" y="26.4">0.33W</text>
<text x="70.9" y="29">C1</text>
<text x="78.6" y="24.5">300K</text>
<text x="82.3" y="27.3">C19</text>
<text x="87.9" y="29.2">10pF</text>
<text x="89.7" y="24.5">680K</text>
<text x="108" y="27.7" transform="rotate(-90 108 27.7)">C20</text>
<text x="113.6" y="27.7" transform="rotate(-90 113.6 27.7)">C21</text>
<text x="164.5" y="26.4">0603</text>
<text x="167.2" y="24.5">30</text>
<text x="169.5" y="26.4">0.33W</text>
<text x="185.4" y="29.9" transform="rotate(-90 185.4 29.9)">0.33W</text>
<text x="190.2" y="27.9">C18</text>
<text x="190.2" y="29.8">3-10pF</text>
<text x="265.3" y="25.8">SHLD3</text>
<text x="52.7" y="35.3">FTR-B3SA</text>
<text x="56.2" y="32.9">K1C</text>
<text x="70.9" y="32.7">250V</text>
<text x="70.9" y="30.9">6pF</text>
<text x="87.9" y="31.1">0603</text>
<text x="87.9" y="32.9">100V</text>
<text x="103.4" y="30.8" transform="rotate(-90 103.4 30.8)">20k</text>
<text x="105.2" y="30.9" transform="rotate(-90 105.2 30.9)">R26</text>
<text x="109.9" y="35.1" transform="rotate(-90 109.9 35.1)">180pF</text>
<text x="115.5" y="35.1" transform="rotate(-90 115.5 35.1)">300pF</text>
<text x="147.7" y="35.3">FTR-B3SA</text>
<text x="151.3" y="32.9">K2C</text>
<text x="181.6" y="30.9" transform="rotate(-90 181.6 30.9)">R53</text>
<text x="183.5" y="30.4" transform="rotate(-90 183.5 30.4)">10</text>
<text x="185.4" y="34.9" transform="rotate(-90 185.4 34.9)">0603</text>
<text x="53" y="36.9">D2</text>
<text x="148.1" y="36.9">D3</text>
<text x="276.1" y="39.5">2118728-2</text>
<text x="43.1" y="42.2">TP25</text>
<text x="50.3" y="45.2">R27</text>
<text x="51" y="46.9">10K</text>
<text x="53" y="42">1N4148</text>
<text x="64.2" y="45.8">Q3</text>
<text x="64.2" y="47.6">DMN62D0UW</text>
<text x="138.2" y="42.2">TP24</text>
<text x="145.3" y="45.2">R56</text>
<text x="146" y="46.9">10K</text>
<text x="148.1" y="42">1N4148</text>
<text x="159.3" y="45.8">Q4</text>
<text x="159.3" y="47.6">DMN62D0UW</text>
<text x="47.5" y="53.3" transform="rotate(-90 47.5 53.3)">10K</text>
<text x="49.3" y="51.4" transform="rotate(-90 49.3 51.4)">R28</text>
<text x="142.5" y="53.3" transform="rotate(-90 142.5 53.3)">10K</text>
<text x="144.4" y="51.4" transform="rotate(-90 144.4 51.4)">R96</text>
<text x="184.8" y="85.1">J5</text>
<text x="186.6" y="90.7">SMA</text>
<text x="207.2" y="92.5">TP26</text>
<text x="215.2" y="92.5" transform="rotate(-90 215.2 92.5)">10K</text>
<text x="217" y="92.4" transform="rotate(-90 217 92.4)">R29</text>
<text x="222.1" y="94.4">U7</text>
<text x="128.9" y="96.3">U8</text>
<text x="180" y="99.7">R30</text>
<text x="180" y="101.5">0</text>
<text x="77.8" y="106.5">30</text>
<text x="95.2" y="103.9">C27</text>
<text x="99.1" y="107.4">22nF</text>
<text x="183.3" y="106.5">49.9</text>
<text x="272.4" y="105.6">J2</text>
<text x="278" y="103.7">J3</text>
<text x="67.9" y="113.2" transform="rotate(-90 67.9 113.2)">909k</text>
<text x="69.8" y="111" transform="rotate(-90 69.8 111)">R41</text>
<text x="77.3" y="108.4">R31</text>
<text x="99.1" y="109.3">100V</text>
<text x="115.5" y="108.5">R34</text>
<text x="116" y="110.3">909k</text>
<text x="155.2" y="110.3">100k</text>
<text x="155.5" y="108.4">R32</text>
<text x="176.1" y="112.9" transform="rotate(-90 176.1 112.9)">R43</text>
<text x="183.5" y="108.4">R33</text>
<text x="274.2" y="111.2">SMA</text>
<text x="279.8" y="109.3">SMA</text>
<text x="46.9" y="114.9">U1</text>
<text x="91.6" y="114.9">U9</text>
<text x="91.6" y="116.8">OP07CDR</text>
<text x="174.2" y="115.3" transform="rotate(-90 174.2 115.3)">90.9k</text>
<text x="177.3" y="119.6">90.9k</text>
<text x="177.8" y="117.7">R47</text>
<text x="210.9" y="114">TP23</text>
<text x="69" y="124">100V</text>
<text x="69" y="120.3">C4</text>
<text x="69" y="122.2">22nF</text>
<text x="109.9" y="121.6">R48</text>
<text x="111.1" y="123.3">2K</text>
<text x="186.6" y="124.2">C28</text>
<text x="205.9" y="125.9" transform="rotate(-90 205.9 125.9)">R97</text>
<text x="222.1" y="124.2">LMH6518</text>
<text x="46.9" y="128">TS12A4516</text>
<text x="114.5" y="127">C29</text>
<text x="117.7" y="130.8">100pF</text>
<text x="128.9" y="126.1">BUF802</text>
<text x="153.7" y="129.7" transform="rotate(-90 153.7 129.7)">R50</text>
<text x="155.5" y="128.7" transform="rotate(-90 155.5 128.7)">0</text>
<text x="174.2" y="131.6" transform="rotate(-90 174.2 131.6)">10K</text>
<text x="176.1" y="129.7" transform="rotate(-90 176.1 129.7)">R52</text>
<text x="186.6" y="126.1">100nF</text>
<text x="204" y="127.5" transform="rotate(-90 204 127.5)">1K</text>
<text x="67.9" y="137.7" transform="rotate(-90 67.9 137.7)">90.9k</text>
<text x="69.8" y="135.3" transform="rotate(-90 69.8 135.3)">R49</text>
<text x="93.3" y="137.5">C30</text>
<text x="97.2" y="141">100pF</text>
<text x="174.2" y="143" transform="rotate(-90 174.2 143)">DNP</text>
<text x="176.1" y="140.9" transform="rotate(-90 176.1 140.9)">R54</text>
<text x="185.6" y="140.7">R55</text>
<text x="185.6" y="142.5">5K</text>
<text x="197.8" y="141">C102</text>
<text x="197.8" y="142.9">100nF</text>
<text x="204" y="142.4" transform="rotate(-90 204 142.4)">1K</text>
<text x="205.9" y="140.8" transform="rotate(-90 205.9 140.8)">R98</text>
<text x="229.5" y="142.9">C26</text>
<text x="239.4" y="141.9">C22</text>
<text x="245" y="141.9">C23</text>
<text x="250.5" y="141.9">C24</text>
<text x="256.1" y="141.9">C25</text>
<text x="229.5" y="144.7">100nF</text>
<text x="239.4" y="145.7">1nF</text>
<text x="244.6" y="145.7">10nF</text>
<text x="250.7" y="145.7">100nF 1uF</text>
<text x="56.8" y="167.5" transform="rotate(-90 56.8 167.5)">90.9k</text>
<text x="58.6" y="165" transform="rotate(-90 58.6 165)">R51</text>
<text x="119.3" y="165.1">C31</text>
<text x="119.3" y="166.9">2.2uF</text>
<text x="127" y="165.2">C32</text>
<text x="127" y="167.1">100nF</text>
<text x="134.5" y="165.2">C33</text>
<text x="134.5" y="167.1">100nF</text>
<text x="141.9" y="165.2">C34</text>
<text x="141.9" y="167.1">100nF</text>
<text x="149.4" y="165.2">C35</text>
<text x="149.4" y="167.1">100nF</text>
<text x="156.8" y="165.2">C36</text>
<text x="156.8" y="167.1">100nF</text>
<text x="164.3" y="165.2">C17</text>
<text x="164.3" y="167.1">100nF</text>
<text x="37.5" y="172.7">TP22</text>
<text x="42.8" y="175.6">R3</text>
<text x="43.6" y="177.3">10K</text>
<text x="56.8" y="176.2">Q5</text>
<text x="56.8" y="178.1">DMN62D0UW</text>
<text x="119.3" y="176.2">C78</text>
<text x="119.3" y="178.1">2.2uF</text>
<text x="126.8" y="176.2">C38</text>
<text x="126.8" y="178.1">100nF</text>
<text x="134.3" y="176.2">C39</text>
<text x="134.3" y="178.1">100nF</text>
<text x="141.7" y="176.2">C63</text>
<text x="141.7" y="178.1">100nF</text>
<text x="149.2" y="176.2">C64</text>
<text x="149.2" y="178.1">100nF</text>
<text x="156.6" y="176.2">C37</text>
<text x="156.6" y="178.1">100nF</text>
<text x="164.1" y="176.2">C124</text>
<text x="164.1" y="178.1">100nF</text>
<text x="36.3" y="183.8" transform="rotate(-90 36.3 183.8)">10K</text>
<text x="38.1" y="183.7" transform="rotate(-90 38.1 183.7)">R35</text>
</g>
<g font-size="1.7" fill="#00f">
<text x="93.5" y="14.3">50x Attenuator</text>
<text x="91.6" y="142.9">Test values from 10pf to 100pf</text>
</g>
<g font-size="1.7" fill="#800000">
<text x="201.1" y="21.7">ATTEN_OUT</text>
<text x="45" y="27.3">+3V3</text>
<text x="140.1" y="27.3">+3V3</text>
<text x="24.6" y="34.8">GND</text>
<text x="67.5" y="40.4">GND</text>
<text x="101" y="40.4">GND</text>
<text x="106.6" y="40.4">GND</text>
<text x="112.2" y="40.4">GND</text>
<text x="181.1" y="40.4">GND</text>
<text x="186.7" y="40.4">GND</text>
<text x="36.7" y="46.9">ATTEN</text>
<text x="132.2" y="46.9">TERM</text>
<text x="272.5" y="45">GND</text>
<text x="45.1" y="62.7">GND</text>
<text x="61.8" y="62.7">GND</text>
<text x="140.1" y="62.7">GND</text>
<text x="156.9" y="62.7">GND</text>
<text x="210.6" y="85.1">+3V3_PGA</text>
<text x="119.9" y="92.5">+5V</text>
<text x="252.3" y="92.5">+5V</text>
<text x="184.9" y="96.3">GND</text>
<text x="199.7" y="97.2">PGA_CSn</text>
<text x="199.7" y="100.9">PGA_SCLK</text>
<text x="199.7" y="99.1">PGA_SDIO</text>
<text x="255.3" y="96.3">+3V3_PGA</text>
<text x="48.8" y="105.6">ATTEN_OUT</text>
<text x="250" y="107.4">OUT_R_N</text>
<text x="250.3" y="105.6">OUT_R_P</text>
<text x="38.1" y="113.1">-5V</text>
<text x="86.4" y="109.3">+5V</text>
<text x="253.7" y="112.1">VCM</text>
<text x="182" y="114.9">-VBIAS</text>
<text x="201.9" y="118.7">+5V</text>
<text x="272.5" y="116.8">GND</text>
<text x="278" y="114.9">GND</text>
<text x="30.1" y="120.5">DC_CPLn</text>
<text x="37.9" y="129.8">+5V</text>
<text x="212.8" y="128">GND</text>
<text x="86.6" y="137.3">-5V</text>
<text x="183" y="133.6">GND</text>
<text x="195.5" y="132.6">TRIM</text>
<text x="223.6" y="133.6">+3V3_PGA</text>
<text x="259.7" y="133.6">+5V</text>
<text x="115.9" y="139.1">GND</text>
<text x="121.5" y="139.1">GND</text>
<text x="153.2" y="139.1">GND</text>
<text x="161.1" y="139.1">-5V</text>
<text x="65.6" y="146.6">GND</text>
<text x="171.8" y="152.2">GND</text>
<text x="183" y="152.2">GND</text>
<text x="194.2" y="152.2">GND</text>
<text x="201.6" y="152.2">GND</text>
<text x="225.8" y="152.2">GND</text>
<text x="237.1" y="152.2">GND</text>
<text x="242.7" y="152.2">GND</text>
<text x="248.2" y="152.2">GND</text>
<text x="253.8" y="152.2">GND</text>
<text x="54.7" y="157.8">+5V</text>
<text x="106.9" y="160.6">+5V</text>
<text x="62.1" y="170.8">DC_CPLn</text>
<text x="106.3" y="171.7">GND</text>
<text x="26.1" y="177.3">DC_CPL</text>
<text x="107.3" y="182.9">-5V</text>
<text x="33.9" y="193.2">GND</text>
<text x="54.4" y="193.2">GND</text>
</g>
<g font-size="1.7" fill="#f00">
<text x="71.1" y="34.8">DNP</text>
<text x="104.6" y="51.6">490pF total</text>
<text x="104.6" y="53.4">- 10pF from C18 &amp; BUF</text>
<text x="104.6" y="55.3">480pF</text>
</g>
</g></defs>
<path d="M4 1.6h288.9v206.8h-288.9z" fill-rule="evenodd" fill="#fffcf8"/>
<path d="M4 1.6h288.9v206.8h-288.9z" fill="none" stroke="#000" stroke-width=".17"/>
<path d="M7.8 5.3h281.4v199.4h-281.4z" fill-rule="evenodd" fill="#fffcf8"/>
<g fill="none" stroke="#000" stroke-width=".17">
<path d="M4 1.6h3.7M7.8 5.3h281.4v199.4h-281.4zM40.1 1.6v3.7M76.2 1.6v3.7M112.3 1.6v3.7M148.5 1.6v3.7M184.6 1.6v3.7M220.7 1.6v3.7M256.8 1.6v3.7M289.2 1.6h3.7v3.7M4 53.3h3.7M289.2 53.3h3.7"/>
<path d="M4 105h3.8M289.2 105h3.7M4 156.7h3.8M289.2 156.7h3.7M40.1 204.7v3.7M76.2 204.7v3.7M112.4 204.7v3.7M148.5 204.7v3.7M184.6 204.7v3.7M220.7 204.7v3.7M256.8 204.7v3.7M292.9 204.7v3.7"/>
</g>
<path d="M265.9 30.5v1.8M265.9 34.2v1.9h1.8M267.7 26.7h-1.8v1.9M269.6 36.1h1.9M269.6 26.7h1.9M273.3 36.1h1.9M273.3 26.7h1.9M277.1 36.1h1.8M277.1 26.7h1.8M280.8 26.7h1.8v1.9M282.6 34.2v1.9h-1.8M282.6 30.5v1.8" fill="none" stroke="#00f" stroke-width=".56"/>
<path d="M274.3 36.1v3.7" fill="none" stroke="#000" stroke-width=".19"/>
<path d="M274.3 39.8v1.9M272.4 41.7h3.7M273 42.2h2.6M273.5 42.8h1.5M274.1 43.3h.3" fill="none" stroke="#800000" stroke-width=".19"/>
<path d="M265.9 10.9h16.7v9.3h-16.7z" fill-rule="evenodd" fill="#ffffb0"/>
<path d="M265.9 10.9h16.7v9.3h-16.7z" fill="none" stroke="#800000" stroke-width=".17"/>
<path d="M52.9 29.2h2.9v4.4h-2.9z" fill-rule="evenodd" fill="#ffffb0"/>
<path d="M52.9 29.2h2.9v4.4h-2.9z" fill="none" stroke="#800000" stroke-width=".17"/>
<path d="M53.2 29.9h.8M53.6 29.6v.7M55.8 29.2l-2.9 4.4M55.8 29.2h-2.9v4.4M55.8 29.2v4.4h-2.9" fill="none" stroke="#00f" stroke-width=".19"/>
<path d="M50.6 31.4h2.2M50.6 38.9h2.8M55.3 38.9h2.8M55.9 31.4h2.2" fill="none" stroke="#000" stroke-width=".19"/>
<path d="M46 27.7h1.8M46.9 27.7v1.8" fill="none" stroke="#800000" stroke-width=".19"/>
<path d="M53.2 38.9l2.2-1.5v2.9z" fill="#00f"/>
<path d="M53.2 38.9l2.2-1.5v2.9zM53.2 37.4v2.9M59.9 46.3h1.7M61.6 44.7v3.3M62 45h1.7M62 46.3h1.7v1.9M62 47.6h1.7M62 44.7v.7M62 45.9v.8M62 47.2v.8" fill="none" stroke="#00f" stroke-width=".19"/>
<path d="M58.1 46.3h1.8M63.7 42.6v1.8M63.7 48.2v1.8" fill="none" stroke="#000" stroke-width=".19"/>
<path d="M62 46.3l1.1-.4v.8z" fill="#00f"/>
<path d="M62 46.3l1.1-.4v.8z" fill="none" stroke="#00f" stroke-width=".17"/>
<path d="M46.2 49.7h1.5v4.4h-1.5zM63.7 44.4v.6" fill="none" stroke="#00f" stroke-width=".19"/>
<path d="M45 59.4h3.7M45.6 59.9h2.6M46.9 57.5v1.9M61.8 59.4h3.7M62.4 59.9h2.6M63.7 57.5v1.9M46.1 60.5h1.5M46.7 61h.4M62.9 60.5h1.5M63.5 61h.3" fill="none" stroke="#800000" stroke-width=".19"/>
<path d="M46.9 48.2v1.4M46.9 54.2v1.4" fill="none" stroke="#000" stroke-width=".19"/>
<path d="M35.7 45.4h6.5l1 .9-1 .9h-6.5z" fill-rule="evenodd" fill="#ffff80"/>
<path d="M35.7 45.4h6.5l1 .9-1 .9h-6.5z" fill="none" stroke="#800000" stroke-width=".17"/>
<g fill="none" stroke="#000" stroke-width=".19">
<path d="M54.3 16.8v.6M54.3 17.8v.6M54.3 18.7v.6M54.3 19.6v.6M54.3 16.5h.6M55.3 16.5h.6M56.2 16.5h.6M57.1 16.5h.6M58.1 16.5h.6M59 16.5h.6M59.9 16.5h.6M60.9 16.5h.5"/>
<path d="M61.8 16.5h.6M62.7 16.5h.6M63.7 16.5h.5M64.6 16.5h.6M65.5 16.5h.6M66.5 16.5h.5M67.4 16.5h.6M68.3 16.5h.6M69.3 16.5h.5M70.2 16.5h.6M71.1 16.5h.6M72 16.5h.6"/>
<path d="M73 16.5h.6M73.9 16.5h.6M74.8 16.5h.6M75.8 16.5h.6M76.7 16.5h.6M77.6 16.5h.6M78.6 16.5h.6M79.5 16.5h.6M80.4 16.5h.6M81.4 16.5h.5M82.3 16.5h.6M83.2 16.5h.6"/>
<path d="M84.2 16.5h.5M85.1 16.5h.6M86 16.5h.6M87 16.5h.5M87.9 16.5h.6M88.8 16.5h.6M89.8 16.5h.5M90.7 16.5h.6M91.6 16.5h.6M92.5 16.5h.6M93.5 16.5h.6M94.4 16.5h.6"/>
<path d="M95.3 16.5h.6M96.3 16.5h.6M97.2 16.5h.6M98.1 16.5h.6M99.1 16.5h.6M100 16.5h.6M100.9 16.5h.6M101.9 16.5h.5M102.8 16.5h.6M103.7 16.5h.6M104.7 16.5h.5M105.6 16.5h.6"/>
<path d="M106.5 16.5h.6M107.5 16.5h.5M108.4 16.5h.6M109.3 16.5h.6M110.3 16.5h.5M111.2 16.5h.6M112.1 16.5h.6M113 16.5h.6M114 16.5h.6M114.9 16.5h.6M115.8 16.5h.6M116.8 16.5h.6"/>
<path d="M117.7 16.5h.6M118.6 16.5h.6M119.6 16.5h.6M120.5 16.5h.6M121.4 16.5h.6M122.4 16.5h.5M123.3 16.5v.6M123.3 17.4v.6M123.3 18.4v.5M123.3 19.3v.6M50.6 22.1h2.2M54.3 20.6v.6"/>
<path d="M54.3 21.5v.6M54.3 22.4v.6M54.3 23.4v.5M54.3 24.3v.6M54.3 25.2v.6M54.3 26.2v.5M54.3 27.1v.6M54.3 28v.6M54.3 29v.5M54.3 29.9v.6M54.3 30.8v.6M54.3 31.8v.5"/>
<path d="M54.3 32.7v.6M54.3 33.6v.6M54.3 34.5v.6M76.7 23.9h1.5M82.3 27.7h1.9M82.7 23.9h1.5M87.9 24h1.5M87.9 27.7h1.9M93.9 24h1.4M102.8 25.8v1.5M102.8 31.8v1.5M108.4 25.8v1.9"/>
<path d="M108.4 31.4v1.9M114 25.8v1.9M114 31.4v1.9M123.3 20.2v.6M123.3 21.2v.5M123.3 22.1v.6M123.3 23v.6"/>
</g>
<g fill="none" stroke="#00f" stroke-width=".19">
<path d="M52.9 22.1l2.5 1.1M78.2 23.2h4.4v1.5h-4.4zM84.2 27.7h1.5M85.7 26.2v2.9M86.4 27.7h1.5M86.4 26.2v2.9M89.4 23.2h4.4v1.5h-4.4zM102.1 27.3h1.5v4.4h-1.5zM106.9 29.9h3M106.9 29.2h3M108.4 27.7v1.5M108.4 29.9v1.5"/>
<path d="M112.5 29.9h2.9M112.5 29.2h2.9M114 27.7v1.5M114 29.9v1.5"/>
</g>
<path d="M100.9 37h3.8M101.5 37.6h2.6M102 38.1h1.5M102.6 38.7h.4M102.8 35.1v1.9M106.5 37h3.8M107.1 37.6h2.6M107.6 38.1h1.5M108.2 38.7h.4M108.4 35.1v1.9" fill="none" stroke="#800000" stroke-width=".19"/>
<path d="M55.4 23.2l.4 .7h-.7z" fill="#00f"/>
<path d="M55.1 20.2h.7l-.4 .8zM55.4 23.2l.4 .7h-.7zM121.8 20.2h.8l-.4 .8zM124.8 22.1l-2.6 1.1" fill="none" stroke="#00f" stroke-width=".19"/>
<path d="M55.9 23.9h2.2M55.9 20.2h2.2M124.8 22.1h2.2" fill="none" stroke="#000" stroke-width=".19"/>
<path d="M122.2 23.2l.4 .8h-.8z" fill="#00f"/>
<g fill="none" stroke="#00f" stroke-width=".19">
<path d="M122.2 23.2l.4 .8h-.8zM50.3 45.5h4.4v1.5h-4.4z"/>
<circle cx="26.4" cy="22.1" r="1.86"/>
</g>
<path d="M26.4 22.1h3.7M26.4 23.9v1.9M119.6 20.2h2.2M119.6 24h2.2M48.7 46.3h1.5M54.7 46.3h1.5" fill="none" stroke="#000" stroke-width=".19"/>
<path d="M24.5 31.4h3.7M25.1 32h2.6M25.6 32.5h1.5M26.2 33.1h.4M26.4 29.5v1.9" fill="none" stroke="#800000" stroke-width=".19"/>
<circle cx="26.4" cy="22.1" r=".47" fill="#00f"/>
<circle cx="26.4" cy="22.1" r=".47" fill="none" stroke="#00f" stroke-width=".17"/>
<circle cx="45" cy="46.3" r=".37" fill="#000080"/>
<circle cx="45" cy="46.3" r=".37" fill="none" stroke="#000080" stroke-width=".17"/>
<path d="M45 44.4v1.9" fill="none" stroke="#000" stroke-width=".19"/>
<circle cx="45" cy="46.3" r=".37" fill="#000080"/>
<circle cx="45" cy="46.3" r=".37" fill="none" stroke="#000080" stroke-width=".17"/>
<circle cx="45" cy="43.5" r=".93" fill="none" stroke="#000" stroke-width=".19"/>
<path d="M65.5 143.2h3.8M66.1 143.8h2.6M66.6 144.3h1.5M67.2 144.9h.4M67.4 141.4v1.8" fill="none" stroke="#800000" stroke-width=".19"/>
<path d="M84.2 115.3l14.9 7.4-14.9 7.5z" fill="#ffffb0"/>
<path d="M84.2 115.3l14.9 7.4-14.9 7.5z" fill="none" stroke="#800000" stroke-width=".17"/>
<g fill="none" stroke="#000" stroke-width=".19">
<path d="M67.4 107.8v1.5M67.4 113.8v1.5M74.8 105.9h1.5M78.6 119h5.6M80.8 105.9h1.5M87.9 111.5v5.6M93.5 105.9h1.8M99.1 105.9h1.8M173.6 109.7v1.4M173.6 115.7v1.4M175.5 119h1.5M181.5 119h1.4"/>
<path d="M67.4 132v1.5M67.4 138v1.5M78.6 126.4h5.6M87.9 128.3v5.6M91.6 126.4v5.6M91.6 139.5h1.9M95.3 124.6v5.6M97.2 139.5h1.9M99.1 122.7h5.6M108.4 122.7h1.5M114.4 122.7h1.4M173.6 126.4v1.5"/>
<path d="M173.6 132.4v1.5M173.6 137.6v1.5M184.8 120.9v1.8M184.8 126.4v1.9M173.6 143.6v1.5M125.2 161.9v1.8M125.2 167.4v1.9M132.6 161.9v1.8M132.6 167.4v1.9M140.1 161.9v1.8M140.1 167.4v1.9M147.5 161.9v1.8"/>
<path d="M147.5 167.4v1.9M155 161.9v1.8M155 167.4v1.9"/>
</g>
<path d="M90.9 131.3l1.5 1.5M92.4 131.3l-1.5 1.5M94.6 129.4l1.5 1.5M96.1 129.4l-1.5 1.5" fill="none" stroke="#f00" stroke-width=".17"/>
<g fill="none" stroke="#00f" stroke-width=".19">
<path d="M66.7 109.3h1.5v4.4h-1.5zM76.4 105.2h4.4v1.5h-4.4zM95.3 105.9h1.5M96.8 104.5v2.9M97.6 105.9h1.5M97.6 104.5v2.9M172.9 111.2h1.5v4.4h-1.5zM177 118.2h4.4v1.5h-4.4zM66.7 133.6h1.5v4.4h-1.5zM93.5 139.5h1.5M95 138v3M95.7 139.5h1.5"/>
<path d="M95.7 138v3M109.9 121.9h4.4v1.5h-4.4zM172.9 128h1.5v4.4h-1.5zM172.9 139.2h1.5v4.4h-1.5zM183.3 124.2h3M183.3 125h3M184.8 122.7v1.5M184.8 125v1.4M123.7 165.2h2.9M123.7 166h2.9M125.2 163.7v1.5M125.2 166v1.4"/>
<path d="M131.1 165.2h3M131.1 166h3M132.6 163.7v1.5M132.6 166v1.4M138.6 165.2h2.9M138.6 166h2.9M140.1 163.7v1.5M140.1 166v1.4M146.1 165.2h2.9M146.1 166h2.9M147.5 163.7v1.5M147.5 166v1.4"/>
<path d="M153.5 165.2h2.9M153.5 166h2.9M155 163.7v1.5M155 166v1.4"/>
</g>
<g fill="none" stroke="#800000" stroke-width=".19">
<path d="M87 109.7h1.8M87.9 109.7v1.8M183.9 115.3h1.8M184.8 115.3v1.8M87 135.8h1.8M87.9 133.9v1.9M182.9 130.2h3.8M183.5 130.7h2.6M184.1 131.3h1.4M184.6 131.9h.4M184.8 128.3v1.9M171.8 148.8h3.7"/>
<path d="M172.3 149.4h2.6M172.9 149.9h1.5M173.4 150.5h.4M173.6 146.9v1.9"/>
</g>
<path d="M128.9 96.6h18.6v28h-18.6z" fill-rule="evenodd" fill="#ffffb0"/>
<path d="M128.9 96.6h18.6v28h-18.6z" fill="none" stroke="#800000" stroke-width=".17"/>
<g fill="none" stroke="#000" stroke-width=".19">
<path d="M123.3 98.5h5.6M114 109.7h1.4M120 109.7h1.4M123.3 102.2h5.6M123.3 105.9h5.6M123.3 109.7h5.6M123.3 113.4h5.6M123.3 117.1h5.6M123.3 119h5.6M123.3 100.4h5.6M147.5 105.9h5.6M147.5 109.7h7.1"/>
<path d="M147.5 113.4h5.6M147.5 117.1h5.6M147.5 119h5.6M159.1 109.7h1.5M181.1 105.9h1.4M187.1 105.9h1.4M117.7 124.6v1.8M117.7 130.2v1.8M123.3 120.9h5.6M123.3 122.7h5.6M147.5 120.9h5.6M147.5 122.7h5.6"/>
<path d="M155 124.6v1.5M155 130.6v1.4M184.8 137.6v1.5M181.1 141.4h3M184.8 143.6v1.5M117.7 161.9v1.8M117.7 167.4v1.9M125.2 173v1.9M125.2 178.6v1.9M132.6 173v1.9M132.6 178.6v1.9M140.1 173v1.9"/>
<path d="M140.1 178.6v1.9M147.5 173v1.9M147.5 178.6v1.9"/>
</g>
<path d="M122.6 116.4l1.4 1.5M122.6 118.3l1.4 1.4M124 116.4l-1.4 1.5M124 118.3l-1.4 1.4M122.6 120.1l1.4 1.5M124 120.1l-1.4 1.5M184.1 136.9l1.4 1.5M185.5 136.9l-1.4 1.5" fill="none" stroke="#f00" stroke-width=".17"/>
<g fill="none" stroke="#800000" stroke-width=".19">
<path d="M120.5 92.9h1.9M121.4 92.9v1.9M115.8 135.8h3.8M116.4 136.3h2.6M117 136.9h1.5M117.5 137.4h.4M117.7 133.9v1.9M121.4 135.8h3.8M122 136.3h2.6M122.6 136.9h1.4M123.1 137.4h.4M123.3 133.9v1.9"/>
<path d="M153.1 135.8h3.7M153.7 136.3h2.6M154.2 136.9h1.5M154.8 137.4h.4M155 133.9v1.9M161.5 137.6h1.9M162.4 135.8v1.8M110.3 159.1v1.8M110.3 160h1.8M182.9 148.8h3.8M183.5 149.4h2.6M184.1 149.9h1.4"/>
<path d="M184.6 150.5h.4M184.8 146.9v1.9M110.3 181.4v1.9M110.3 182.4h1.8"/>
</g>
<g fill="none" stroke="#00f" stroke-width=".19">
<path d="M115.5 108.9h4.4v1.5h-4.4zM154.6 109h4.4v1.5h-4.4zM182.6 105.2h4.4v1.5h-4.4zM116.2 128.7h3M116.2 127.9h3M117.7 126.4v1.5M117.7 128.7v1.5M154.3 126.1h1.5v4.4h-1.5zM184.1 139.2h1.5v4.4h-1.5zM116.2 166h3M116.2 165.2h3M117.7 163.7v1.5"/>
<path d="M117.7 166v1.4M123.7 177.1h2.9M123.7 176.4h2.9M125.2 174.9v1.5M125.2 177.1v1.5M131.1 177.1h3M131.1 176.4h3M132.6 174.9v1.5M132.6 177.1v1.5M138.6 177.1h2.9M138.6 176.4h2.9M140.1 174.9v1.5"/>
<path d="M140.1 177.1v1.5M146.1 177.1h2.9M146.1 176.4h2.9M147.5 174.9v1.5M147.5 177.1v1.5"/>
</g>
<path d="M183.5 140.8l.6 .6-.6 .5z" fill="#000"/>
<path d="M183.5 140.8l.6 .6-.6 .5z" fill="none" stroke="#000" stroke-width=".17"/>
<path d="M222.1 94.8h22.3v27.9h-22.3z" fill-rule="evenodd" fill="#ffffb0"/>
<path d="M222.1 94.8h22.3v27.9h-22.3z" fill="none" stroke="#800000" stroke-width=".17"/>
<path d="M216.5 96.6h5.6M216.5 98.5h5.6M216.5 100.4h5.6M244.4 100.4h5.6M244.4 111.5h5.6" fill="none" stroke="#000" stroke-width=".19"/>
<path d="M244.4 111.5l1.2-.3v.7z" fill="#f8fcff"/>
<path d="M244.4 111.5l1.2-.3v.7z" fill="none" stroke="#000" stroke-width=".17"/>
<path d="M244.4 107.8h5.6M244.4 105.9h5.6M244.4 115.3h5.6M244.4 117.1h5.6M244.4 120.9h5.6" fill="none" stroke="#000" stroke-width=".19"/>
<path d="M244.4 120.9l1.2-.4v.7z" fill="#f8fcff"/>
<path d="M244.4 120.9l1.2-.4v.7z" fill="none" stroke="#000" stroke-width=".17"/>
<path d="M244.4 96.6h5.6M244.4 98.5h5.6M216.5 119h5.6M216.5 117.1h5.6M216.5 105.9h5.6M216.5 107.8h5.6M216.5 120.9h5.6" fill="none" stroke="#000" stroke-width=".19"/>
<path d="M197.8 95.7h10.3l.9 .9-.9 1h-10.3z" fill-rule="evenodd" fill="#ffff80"/>
<path d="M197.8 95.7h10.3l.9 .9-.9 1h-10.3z" fill="none" stroke="#800000" stroke-width=".17"/>
<path d="M214.6 87.3v1.5M214.6 93.3v1.5" fill="none" stroke="#000" stroke-width=".19"/>
<path d="M213.9 88.8h1.5v4.4h-1.5z" fill="none" stroke="#00f" stroke-width=".19"/>
<path d="M197.8 99.4h10.3l.9 1-.9 .9h-10.3z" fill-rule="evenodd" fill="#ffff80"/>
<path d="M197.8 99.4h10.3l.9 1-.9 .9h-10.3z" fill="none" stroke="#800000" stroke-width=".17"/>
<path d="M197.8 97.6h10.3l.9 .9-.9 .9h-10.3z" fill-rule="evenodd" fill="#ffff80"/>
<path d="M197.8 97.6h10.3l.9 .9-.9 .9h-10.3z" fill="none" stroke="#800000" stroke-width=".17"/>
<path d="M212.8 124.6h3.7M213.3 125.1h2.6M213.9 125.7h1.5M214.4 126.3h.4M214.6 122.7v1.9" fill="none" stroke="#800000" stroke-width=".19"/>
<path d="M251.9 111.5l.9-.9h6.5v1.9h-6.5z" fill-rule="evenodd" fill="#ffff80"/>
<path d="M251.9 111.5l.9-.9h6.5v1.9h-6.5z" fill="none" stroke="#800000" stroke-width=".17"/>
<path d="M249.3 114.5l1.5 1.5M249.3 116.4l1.5 1.5M250.8 114.5l-1.5 1.5M250.8 116.4l-1.5 1.5M249.3 120.1l1.5 1.5M250.8 120.1l-1.5 1.5" fill="none" stroke="#f00" stroke-width=".17"/>
<circle cx="274.3" cy="107.8" r="1.86" fill="none" stroke="#00f" stroke-width=".19"/>
<path d="M270.5 107.8h3.8M274.3 109.7v1.8" fill="none" stroke="#000" stroke-width=".19"/>
<circle cx="274.3" cy="107.8" r=".47" fill="#00f"/>
<circle cx="274.3" cy="107.8" r=".47" fill="none" stroke="#00f" stroke-width=".17"/>
<path d="M272.4 113.4h3.7M273 114h2.6M273.5 114.5h1.5M274.1 115.1h.3M274.3 111.5v1.9" fill="none" stroke="#800000" stroke-width=".19"/>
<circle cx="279.8" cy="105.9" r="1.86" fill="none" stroke="#00f" stroke-width=".19"/>
<path d="M276.1 105.9h3.7M279.8 107.8v1.9" fill="none" stroke="#000" stroke-width=".19"/>
<circle cx="279.8" cy="105.9" r=".47" fill="#00f"/>
<circle cx="279.8" cy="105.9" r=".47" fill="none" stroke="#00f" stroke-width=".17"/>
<path d="M278 111.5h3.7M278.5 112.1h2.7M279.1 112.7h1.5M279.7 113.2h.3M279.8 109.7v1.8" fill="none" stroke="#800000" stroke-width=".19"/>
<path d="M258.6 104.7h.7l.4-.3h.8l.3 .3h.8M258.6 105.2h.7l.4 .4h.8l.3-.4h.8" fill="none" stroke="#d0a19e" stroke-width=".19"/>
<path d="M258.6 105.2l-1.1 .7" fill="none" stroke="#d0a19e" stroke-width=".17"/>
<path d="M258.4 104.6h.8l.3-.4h.8l.4 .4h.7M258.4 105h.8l.3 .4h.8l.4-.4h.7" fill="none" stroke="#f00" stroke-width=".19"/>
<path d="M258.4 105l-.9 .9" fill="none" stroke="#f00" stroke-width=".17"/>
<circle cx="210.9" cy="96.6" r=".37" fill="#000080"/>
<circle cx="210.9" cy="96.6" r=".37" fill="none" stroke="#000080" stroke-width=".17"/>
<path d="M210.9 94.8v1.8" fill="none" stroke="#000" stroke-width=".19"/>
<circle cx="210.9" cy="96.6" r=".37" fill="#000080"/>
<circle cx="210.9" cy="96.6" r=".37" fill="none" stroke="#000080" stroke-width=".17"/>
<g fill="none" stroke="#000" stroke-width=".19">
<path d="M227.7 139.5v1.9M238.8 139.5v1.9M244.4 139.5v1.9M250 139.5v1.9M255.6 139.5v1.9M227.7 145.1v1.8M238.8 145.1v1.8M244.4 145.1v1.8M250 145.1v1.8M255.6 145.1v1.8"/>
<circle cx="210.9" cy="93.8" r=".93"/>
</g>
<g fill="none" stroke="#00f" stroke-width=".19">
<path d="M226.2 143.6h2.9M226.2 142.9h2.9M227.7 141.4v1.5M227.7 143.6v1.5M237.4 143.6h2.9M237.4 142.9h2.9M238.8 141.4v1.5M238.8 143.6v1.5M243 143.6h2.9M243 142.9h2.9M244.4 141.4v1.5M244.4 143.6v1.5"/>
<path d="M248.6 143.6h2.9M248.6 142.9h2.9M250 141.4v1.5M250 143.6v1.5M254.1 143.6h3M254.1 142.9h3M255.6 141.4v1.5M255.6 143.6v1.5"/>
</g>
<g fill="none" stroke="#800000" stroke-width=".19">
<path d="M252.8 92.9h1.9M253.8 92.9v1.9M260.3 133.9h1.8M261.2 133.9v1.9M225.8 148.8h3.7M226.4 149.4h2.6M226.9 149.9h1.5M227.5 150.5h.3M227.7 146.9v1.9M237 148.8h3.7M237.5 149.4h2.6M238.1 149.9h1.5"/>
<path d="M238.7 150.5h.3M238.8 146.9v1.9M242.6 148.8h3.7M243.1 149.4h2.6M243.7 149.9h1.5M244.3 150.5h.3M244.4 146.9v1.9M248.2 148.8h3.7M248.7 149.4h2.6M249.3 149.9h1.5M249.8 150.5h.4M250 146.9v1.9"/>
<path d="M253.8 148.8h3.7M254.3 149.4h2.6M254.9 149.9h1.5M255.4 150.5h.4M255.6 146.9v1.9M110.4 171v.4M111 170.4v1.5M111.6 169.9v2.6M112.1 169.3v3.7M112.1 171.2h1.9"/>
</g>
<path d="M258.6 106.6h.7l.4-.4h.8l.3 .4h.8M258.6 107.1h.7l.4 .3h.8l.3-.3h.8" fill="none" stroke="#d0a19e" stroke-width=".19"/>
<path d="M258.6 107.1l-1.1 .7" fill="none" stroke="#d0a19e" stroke-width=".17"/>
<path d="M258.4 106.4h.8l.3-.4h.8l.4 .4h.7M258.4 106.9h.8l.3 .4h.8l.4-.4h.7" fill="none" stroke="#f00" stroke-width=".19"/>
<path d="M258.4 106.9l-.9 .9" fill="none" stroke="#f00" stroke-width=".17"/>
<path d="M130.8 45.4h6.5l.9 .9-.9 .9h-6.5z" fill-rule="evenodd" fill="#ffff80"/>
<path d="M130.8 45.4h6.5l.9 .9-.9 .9h-6.5z" fill="none" stroke="#800000" stroke-width=".17"/>
<path d="M186.7 37h3.7M187.2 37.6h2.6M187.8 38.1h1.5M188.3 38.7h.4M188.5 35.1v1.9" fill="none" stroke="#800000" stroke-width=".19"/>
<path d="M188.5 25.8v1.9M188.5 29.5v1.9" fill="none" stroke="#000" stroke-width=".19"/>
<path d="M187.8 27.1l1.7 3.4" fill="none" stroke="#00f" stroke-width=".19"/>
<path d="M187.4 26.6l.8 .5-.6 .4z" fill="#00f"/>
<path d="M187 28.2h3M187 29h3M187.4 26.6l.8 .5-.6 .4zM188.5 27.7v.5M188.5 29v.5" fill="none" stroke="#00f" stroke-width=".19"/>
<path d="M147.9 29.2h3v4.4h-3z" fill-rule="evenodd" fill="#ffffb0"/>
<path d="M147.9 29.2h3v4.4h-3z" fill="none" stroke="#800000" stroke-width=".17"/>
<path d="M148.3 29.9h.7M148.7 29.6v.7M150.9 29.2l-3 4.4M150.9 29.2h-3v4.4M150.9 29.2v4.4h-3" fill="none" stroke="#00f" stroke-width=".19"/>
<path d="M145.7 31.4h2.2M145.7 38.9h2.8M150.3 38.9h2.8M150.9 31.4h2.2" fill="none" stroke="#000" stroke-width=".19"/>
<path d="M141 27.7h1.9M141.9 27.7v1.8" fill="none" stroke="#800000" stroke-width=".19"/>
<path d="M148.3 38.9l2.2-1.5v2.9z" fill="#00f"/>
<path d="M148.3 38.9l2.2-1.5v2.9zM148.3 37.4v2.9M155 46.3h1.7M156.7 44.7v3.3M157 45h1.7M157 46.3h1.7v1.9M157 47.6h1.7M157 44.7v.7M157 45.9v.8M157 47.2v.8" fill="none" stroke="#00f" stroke-width=".19"/>
<path d="M153.1 46.3h1.9M158.7 42.6v1.8M158.7 48.2v1.8" fill="none" stroke="#000" stroke-width=".19"/>
<path d="M157 46.3l1.1-.4v.8z" fill="#00f"/>
<path d="M157 46.3l1.1-.4v.8z" fill="none" stroke="#00f" stroke-width=".17"/>
<path d="M147.9 22.1l2.6 1.1M141.2 49.7h1.5v4.4h-1.5zM158.7 44.4v.6" fill="none" stroke="#00f" stroke-width=".19"/>
<path d="M140.1 59.4h3.7M140.6 59.9h2.6M141.9 57.5v1.9M156.8 59.4h3.8M157.4 59.9h2.6M158.7 57.5v1.9M141.2 60.5h1.5M141.7 61h.4M158 60.5h1.5M158.5 61h.4" fill="none" stroke="#800000" stroke-width=".19"/>
<g fill="none" stroke="#000" stroke-width=".19">
<path d="M149.4 16.8v.6M149.4 17.8v.6M149.4 18.7v.6M149.4 19.6v.6M149.4 16.5h.6M150.3 16.5h.6M151.3 16.5h.5M152.2 16.5h.6M153.1 16.5h.6M154 16.5h.6M155 16.5h.6M155.9 16.5h.6"/>
<path d="M156.8 16.5h.6M157.8 16.5h.6M158.7 16.5h.6M159.6 16.5h.6M160.6 16.5h.6M161.5 16.5h.6M162.4 16.5h.6M163.4 16.5h.5M164.3 16.5h.6M165.2 16.5h.6M166.2 16.5h.5M167.1 16.5h.6"/>
<path d="M168 16.5h.6M169 16.5h.5M169.9 16.5h.6M170.8 16.5h.6M171.8 16.5h.5M172.7 16.5h.6M173.6 16.5h.6M174.6 16.5h.5M175.5 16.5h.6M176.4 16.5h.6M177.3 16.5h.6M178.3 16.5h.6"/>
<path d="M179.2 16.5h.6M180.1 16.5h.6M181.1 16.5h.6M182 16.5h.6M182.9 16.5h.6M183.9 16.5h.6M184.8 16.5h.6M185.7 16.5h.6M186.7 16.5h.6M187.6 16.5h.6M188.5 16.5h.6M189.5 16.5h.5"/>
<path d="M190.4 16.5h.6M191.3 16.5h.6M192.3 16.5h.5M193.2 16.5h.6M194.1 16.5h.6M195.1 16.5h.5M196 16.5v.6M196 17.4v.6M196 18.4v.5M196 19.3v.6M145.7 22.1h2.2M149.4 20.6v.6"/>
<path d="M149.4 21.5v.6M149.4 22.4v.6M149.4 23.4v.6M149.4 24.3v.6M149.4 25.2v.6M149.4 26.2v.5M149.4 27.1v.6M149.4 28v.6M149.4 29v.5M149.4 29.9v.6M149.4 30.8v.6M149.4 31.8v.5"/>
<path d="M149.4 32.7v.6M196 20.2v.6M196 21.2v.5M141.9 48.2v1.4M141.9 54.2v1.4"/>
</g>
<path d="M150.5 23.2l.4 .8h-.8z" fill="#00f"/>
<path d="M150.1 20.2h.8l-.4 .8zM150.5 23.2l.4 .8h-.8zM194.5 20.2h.8l-.4 .8zM197.5 22.1l-2.6 1.1" fill="none" stroke="#00f" stroke-width=".19"/>
<path d="M150.9 24h2.2M150.9 20.2h2.2M197.5 22.1h2.2" fill="none" stroke="#000" stroke-width=".19"/>
<path d="M194.9 23.2l.4 .8h-.8z" fill="#00f"/>
<path d="M194.9 23.2l.4 .8h-.8zM145.3 45.5h4.4v1.5h-4.4z" fill="none" stroke="#00f" stroke-width=".19"/>
<path d="M192.3 20.2h2.2M192.3 24h2.2M143.8 46.3h1.5M149.8 46.3h1.5" fill="none" stroke="#000" stroke-width=".19"/>
<circle cx="140.1" cy="46.3" r=".37" fill="#000080"/>
<circle cx="140.1" cy="46.3" r=".37" fill="none" stroke="#000080" stroke-width=".17"/>
<path d="M140.1 44.4v1.9" fill="none" stroke="#000" stroke-width=".19"/>
<circle cx="140.1" cy="46.3" r=".37" fill="#000080"/>
<circle cx="140.1" cy="46.3" r=".37" fill="none" stroke="#000080" stroke-width=".17"/>
<g fill="none" stroke="#000" stroke-width=".19">
<path d="M171.8 20.2h1.4M177.7 20.2h1.5M182.9 25.8v1.5M182.9 31.8v1.5M203.4 122.7v1.5M203.4 128.7v1.5M203.4 137.6v1.5M203.4 143.6v1.5"/>
<circle cx="140.1" cy="43.5" r=".93"/>
</g>
<path d="M173.3 19.5h4.4v1.5h-4.4zM182.2 27.3h1.5v4.4h-1.5zM202.7 124.2h1.5v4.5h-1.5zM202.7 139.2h1.5v4.4h-1.5z" fill="none" stroke="#00f" stroke-width=".19"/>
<path d="M181.1 37h3.7M181.6 37.6h2.6M182.2 38.1h1.5M182.8 38.7h.3M182.9 35.1v1.9M201.6 148.8h3.7M202.1 149.4h2.6M202.7 149.9h1.5M203.3 150.5h.3M203.4 146.9v1.9" fill="none" stroke="#800000" stroke-width=".19"/>
<path d="M194.1 131.1h6.5l1 .9-1 1h-6.5z" fill-rule="evenodd" fill="#ffff80"/>
<path d="M194.1 131.1h6.5l1 .9-1 1h-6.5z" fill="none" stroke="#800000" stroke-width=".17"/>
<path d="M202.5 119h1.9M203.4 119v1.9" fill="none" stroke="#800000" stroke-width=".19"/>
<circle cx="209" cy="111.5" r=".37" fill="#000080"/>
<circle cx="209" cy="111.5" r=".37" fill="none" stroke="#000080" stroke-width=".17"/>
<path d="M209 111.5h1.9" fill="none" stroke="#000" stroke-width=".19"/>
<circle cx="209" cy="111.5" r=".37" fill="#000080"/>
<circle cx="209" cy="111.5" r=".37" fill="none" stroke="#000080" stroke-width=".17"/>
<g fill="none" stroke="#000" stroke-width=".19">
<path d="M196 137.6v1.9M196 143.2v1.9M56.2 161.9v1.4M56.2 167.8v1.5"/>
<circle cx="211.8" cy="111.5" r=".93"/>
</g>
<path d="M196 139.5v1.5M194.5 141h3M194.5 141.7h3M196 141.7v1.5M55.5 163.4h1.5v4.4h-1.5z" fill="none" stroke="#00f" stroke-width=".19"/>
<path d="M194.1 148.8h3.7M194.7 149.4h2.6M195.2 149.9h1.5M195.8 150.5h.4M196 146.9v1.9" fill="none" stroke="#800000" stroke-width=".19"/>
<circle cx="37.6" cy="176.8" r=".37" fill="#000080"/>
<circle cx="37.6" cy="176.8" r=".37" fill="none" stroke="#000080" stroke-width=".17"/>
<path d="M37.6 174.9v1.9" fill="none" stroke="#000" stroke-width=".19"/>
<circle cx="37.6" cy="176.8" r=".37" fill="#000080"/>
<circle cx="37.6" cy="176.8" r=".37" fill="none" stroke="#000080" stroke-width=".17"/>
<g fill="none" stroke="#000" stroke-width=".19">
<path d="M35.7 178.6v1.5M35.7 184.6v1.5"/>
<circle cx="37.6" cy="174" r=".93"/>
</g>
<path d="M34.9 180.2h1.5v4.4h-1.5z" fill="none" stroke="#00f" stroke-width=".19"/>
<path d="M33.8 189.8h3.8M34.4 190.4h2.6M35 190.9h1.4M35.5 191.5h.4M35.7 187.9v1.9" fill="none" stroke="#800000" stroke-width=".19"/>
<path d="M24.5 175.8h8.4l.9 1-.9 .9h-8.4z" fill-rule="evenodd" fill="#ffff80"/>
<path d="M24.5 175.8h8.4l.9 1-.9 .9h-8.4z" fill="none" stroke="#800000" stroke-width=".17"/>
<path d="M182.9 87.3h3.8M186.7 89.2v1.8M117.7 173v1.9M117.7 178.6v1.9M155 173v1.9M155 178.6v1.9M162.4 161.9v1.8M162.4 167.4v1.9M162.4 173v1.9M162.4 178.6v1.9" fill="none" stroke="#000" stroke-width=".19"/>
<g fill="none" stroke="#00f" stroke-width=".19">
<path d="M116.2 176.4h3M116.2 177.1h3M117.7 174.9v1.5M117.7 177.1v1.5M153.5 176.4h3M153.5 177.1h3M155 174.9v1.5M155 177.1v1.5M161 166h2.9M161 165.2h2.9M161 176.4h2.9M161 177.1h2.9"/>
<path d="M162.4 163.7v1.5M162.4 166v1.4M162.4 174.9v1.5M162.4 177.1v1.5"/>
<circle cx="186.7" cy="87.3" r="1.86"/>
</g>
<path d="M213.7 85.4h1.9M214.6 85.4v1.9M258.4 96.6h1.9M259.3 96.6v1.9M226.7 133.9h1.9M227.7 133.9v1.9" fill="none" stroke="#800000" stroke-width=".19"/>
<circle cx="186.7" cy="87.3" r=".47" fill="#00f"/>
<circle cx="186.7" cy="87.3" r=".47" fill="none" stroke="#00f" stroke-width=".17"/>
<g fill="none" stroke="#800000" stroke-width=".19">
<path d="M67.4 37h3.7M67.9 37.6h2.7M68.5 38.1h1.5M69.1 38.7h.3M69.3 35.1v1.9M112.1 37h3.7M112.7 37.6h2.6M113.2 38.1h1.5M113.8 38.7h.4M114 35.1v1.9M184.8 92.9h3.7M185.4 93.5h2.6"/>
<path d="M185.9 94h1.5M186.5 94.6h.3M186.7 91v1.9"/>
</g>
<path d="M69.3 25.8v1.9M69.3 31.4v1.9M179.2 96.6v1.5M179.2 102.6v1.5" fill="none" stroke="#000" stroke-width=".19"/>
<path d="M67.8 29.9h2.9M67.8 29.2h2.9M69.3 27.7v1.5M69.3 29.9v1.5M178.5 98.2h1.5v4.4h-1.5z" fill="none" stroke="#00f" stroke-width=".19"/>
<path d="M46.9 115.3h11.2v11.1h-11.2z" fill-rule="evenodd" fill="#ffffb0"/>
<path d="M46.9 115.3h11.2v11.1h-11.2z" fill="none" stroke="#800000" stroke-width=".17"/>
<path d="M41.3 117.1h5.6M58.1 117.1h5.6M41.3 124.6h5.6M41.3 120.9h5.6M58.1 124.6h5.6" fill="none" stroke="#000" stroke-width=".19"/>
<circle cx="67.4" cy="117.1" r=".37" fill="#000080"/>
<circle cx="67.4" cy="117.1" r=".37" fill="none" stroke="#000080" stroke-width=".17"/>
<circle cx="67.4" cy="124.6" r=".37" fill="#000080"/>
<circle cx="67.4" cy="124.6" r=".37" fill="none" stroke="#000080" stroke-width=".17"/>
<path d="M67.4 117.1v1.9" fill="none" stroke="#000" stroke-width=".19"/>
<circle cx="67.4" cy="117.1" r=".37" fill="#000080"/>
<circle cx="67.4" cy="117.1" r=".37" fill="none" stroke="#000080" stroke-width=".17"/>
<path d="M67.4 122.7v1.9" fill="none" stroke="#000" stroke-width=".19"/>
<circle cx="67.4" cy="124.6" r=".37" fill="#000080"/>
<circle cx="67.4" cy="124.6" r=".37" fill="none" stroke="#000080" stroke-width=".17"/>
<path d="M67.4 119v1.5M65.9 120.5h3M65.9 121.2h3M67.4 121.2v1.5M52.5 176.8h1.7M54.2 175.1v3.3M54.5 175.5h1.7M54.5 176.8h1.7v1.8M54.5 178.1h1.7M54.5 175.1v.8M54.5 176.4v.7M54.5 177.7v.7" fill="none" stroke="#00f" stroke-width=".19"/>
<path d="M38.5 113.4h1.9M39.4 113.4v1.9M38.5 128.3h1.9M39.4 126.4v1.9" fill="none" stroke="#800000" stroke-width=".19"/>
<path d="M50.6 176.8h1.9M56.2 173v1.9M56.2 178.6v1.9" fill="none" stroke="#000" stroke-width=".19"/>
<path d="M54.5 176.8l1.1-.4v.7z" fill="#00f"/>
<path d="M54.5 176.8l1.1-.4v.7z" fill="none" stroke="#00f" stroke-width=".17"/>
<path d="M156.5 19.5h4.4v1.5h-4.4zM61.5 23.2h4.4v1.5h-4.4zM165.8 23.2h4.4v1.5h-4.4zM42.8 176h4.4v1.5h-4.4zM56.2 174.9v.6" fill="none" stroke="#00f" stroke-width=".19"/>
<path d="M55.3 158.1h1.8M56.2 158.1v1.9M54.3 189.8h3.8M54.9 190.4h2.6M55.5 190.9h1.5M56 191.5h.4M56.2 187.9v1.9" fill="none" stroke="#800000" stroke-width=".19"/>
<path d="M59.9 23.9h1.5M65.9 23.9h1.5M155 20.2h1.4M161 20.2h1.4M164.3 24h1.5M170.3 24h1.5M41.3 176.8h1.5M47.3 176.8h1.5" fill="none" stroke="#000" stroke-width=".19"/>
<path d="M43.2 46.3h3.7" fill="none" stroke="#000080" stroke-width=".19"/>
<circle cx="46.9" cy="46.3" r=".37" fill="#000080"/>
<circle cx="46.9" cy="46.3" r=".37" fill="none" stroke="#000080" stroke-width=".17"/>
<circle cx="45" cy="46.3" r=".37" fill="#000080"/>
<circle cx="45" cy="46.3" r=".37" fill="none" stroke="#000080" stroke-width=".17"/>
<path d="M48.7 46.3h-1.8v1.9" fill="none" stroke="#000080" stroke-width=".19"/>
<circle cx="46.9" cy="46.3" r=".37" fill="#000080"/>
<circle cx="46.9" cy="46.3" r=".37" fill="none" stroke="#000080" stroke-width=".17"/>
<path d="M46.9 31.4v7.5h3.7" fill="none" stroke="#000080" stroke-width=".19"/>
<circle cx="46.9" cy="31.4" r=".37" fill="#000080"/>
<circle cx="46.9" cy="31.4" r=".37" fill="none" stroke="#000080" stroke-width=".17"/>
<path d="M46.9 29.5v1.9h3.7" fill="none" stroke="#000080" stroke-width=".19"/>
<circle cx="46.9" cy="31.4" r=".37" fill="#000080"/>
<circle cx="46.9" cy="31.4" r=".37" fill="none" stroke="#000080" stroke-width=".17"/>
<path d="M58.1 38.9h5.6M56.2 46.3h1.9" fill="none" stroke="#000080" stroke-width=".19"/>
<circle cx="63.7" cy="38.9" r=".37" fill="#000080"/>
<circle cx="63.7" cy="38.9" r=".37" fill="none" stroke="#000080" stroke-width=".17"/>
<path d="M74.8 23.9v3.8h7.5" fill="none" stroke="#000080" stroke-width=".19"/>
<circle cx="74.8" cy="23.9" r=".37" fill="#000080"/>
<circle cx="74.8" cy="23.9" r=".37" fill="none" stroke="#000080" stroke-width=".17"/>
<path d="M26.4 25.8v3.7M84.2 24h3.7M102.8 33.3v1.8M46.9 55.6v1.9M63.7 50v7.5M184.8 119v1.9" fill="none" stroke="#000080" stroke-width=".19"/>
<circle cx="184.8" cy="119" r=".37" fill="#000080"/>
<circle cx="184.8" cy="119" r=".37" fill="none" stroke="#000080" stroke-width=".17"/>
<path d="M104.7 122.7h1.8v16.8h-7.4" fill="none" stroke="#000080" stroke-width=".19"/>
<circle cx="106.5" cy="122.7" r=".37" fill="#000080"/>
<circle cx="106.5" cy="122.7" r=".37" fill="none" stroke="#000080" stroke-width=".17"/>
<path d="M173.6 119h1.9" fill="none" stroke="#000080" stroke-width=".19"/>
<circle cx="173.6" cy="119" r=".37" fill="#000080"/>
<circle cx="173.6" cy="119" r=".37" fill="none" stroke="#000080" stroke-width=".17"/>
<path d="M117.7 160v1.9" fill="none" stroke="#000080" stroke-width=".19"/>
<circle cx="117.7" cy="160" r=".37" fill="#000080"/>
<circle cx="117.7" cy="160" r=".37" fill="none" stroke="#000080" stroke-width=".17"/>
<path d="M132.6 160v1.9" fill="none" stroke="#000080" stroke-width=".19"/>
<circle cx="132.6" cy="160" r=".37" fill="#000080"/>
<circle cx="132.6" cy="160" r=".37" fill="none" stroke="#000080" stroke-width=".17"/>
<path d="M140.1 160v1.9" fill="none" stroke="#000080" stroke-width=".19"/>
<circle cx="140.1" cy="160" r=".37" fill="#000080"/>
<circle cx="140.1" cy="160" r=".37" fill="none" stroke="#000080" stroke-width=".17"/>
<path d="M67.4 139.5v1.9M147.5 160v1.9" fill="none" stroke="#000080" stroke-width=".19"/>
<circle cx="147.5" cy="160" r=".37" fill="#000080"/>
<circle cx="147.5" cy="160" r=".37" fill="none" stroke="#000080" stroke-width=".17"/>
<path d="M82.3 105.9h11.2M106.5 122.7h1.9M173.6 145.1v1.8" fill="none" stroke="#000080" stroke-width=".19"/>
<circle cx="106.5" cy="122.7" r=".37" fill="#000080"/>
<circle cx="106.5" cy="122.7" r=".37" fill="none" stroke="#000080" stroke-width=".17"/>
<path d="M160.6 109.7h1.8v3.7M123.3 122.7v11.2M155 132v1.9" fill="none" stroke="#000080" stroke-width=".19"/>
<circle cx="162.4" cy="113.4" r=".37" fill="#000080"/>
<circle cx="162.4" cy="113.4" r=".37" fill="none" stroke="#000080" stroke-width=".17"/>
<path d="M121.4 100.4h1.9" fill="none" stroke="#000080" stroke-width=".19"/>
<circle cx="121.4" cy="100.4" r=".37" fill="#000080"/>
<circle cx="121.4" cy="100.4" r=".37" fill="none" stroke="#000080" stroke-width=".17"/>
<path d="M121.4 98.5h1.9" fill="none" stroke="#000080" stroke-width=".19"/>
<circle cx="121.4" cy="98.5" r=".37" fill="#000080"/>
<circle cx="121.4" cy="98.5" r=".37" fill="none" stroke="#000080" stroke-width=".17"/>
<path d="M117.7 122.7v1.9" fill="none" stroke="#000080" stroke-width=".19"/>
<circle cx="117.7" cy="122.7" r=".37" fill="#000080"/>
<circle cx="117.7" cy="122.7" r=".37" fill="none" stroke="#000080" stroke-width=".17"/>
<path d="M117.7 132v1.9M173.6 135.8h5.6v5.6h1.9M184.8 145.1v1.8" fill="none" stroke="#000080" stroke-width=".19"/>
<circle cx="173.6" cy="135.8" r=".37" fill="#000080"/>
<circle cx="173.6" cy="135.8" r=".37" fill="none" stroke="#000080" stroke-width=".17"/>
<path d="M140.1 180.5v1.9" fill="none" stroke="#000080" stroke-width=".19"/>
<circle cx="140.1" cy="182.4" r=".37" fill="#000080"/>
<circle cx="140.1" cy="182.4" r=".37" fill="none" stroke="#000080" stroke-width=".17"/>
<path d="M132.6 180.5v1.9" fill="none" stroke="#000080" stroke-width=".19"/>
<circle cx="132.6" cy="182.4" r=".37" fill="#000080"/>
<circle cx="132.6" cy="182.4" r=".37" fill="none" stroke="#000080" stroke-width=".17"/>
<path d="M125.2 180.5v1.9" fill="none" stroke="#000080" stroke-width=".19"/>
<circle cx="125.2" cy="182.4" r=".37" fill="#000080"/>
<circle cx="125.2" cy="182.4" r=".37" fill="none" stroke="#000080" stroke-width=".17"/>
<path d="M173.6 105.9v3.8" fill="none" stroke="#000080" stroke-width=".19"/>
<circle cx="173.6" cy="105.9" r=".37" fill="#000080"/>
<circle cx="173.6" cy="105.9" r=".37" fill="none" stroke="#000080" stroke-width=".17"/>
<path d="M112.1 105.9v3.8h1.9M121.4 109.7h1.9" fill="none" stroke="#000080" stroke-width=".19"/>
<circle cx="112.1" cy="105.9" r=".37" fill="#000080"/>
<circle cx="112.1" cy="105.9" r=".37" fill="none" stroke="#000080" stroke-width=".17"/>
<path d="M209 98.5h7.5M188.5 105.9h28M209 100.4h7.5M214.6 119h1.9" fill="none" stroke="#000080" stroke-width=".19"/>
<circle cx="214.6" cy="119" r=".37" fill="#000080"/>
<circle cx="214.6" cy="119" r=".37" fill="none" stroke="#000080" stroke-width=".17"/>
<path d="M250 96.6h3.8M250 111.5h1.9" fill="none" stroke="#000080" stroke-width=".19"/>
<circle cx="253.8" cy="96.6" r=".37" fill="#000080"/>
<circle cx="253.8" cy="96.6" r=".37" fill="none" stroke="#000080" stroke-width=".17"/>
<path d="M214.6 120.9v1.8" fill="none" stroke="#000080" stroke-width=".19"/>
<circle cx="214.6" cy="120.9" r=".37" fill="#000080"/>
<circle cx="214.6" cy="120.9" r=".37" fill="none" stroke="#000080" stroke-width=".17"/>
<path d="M214.6 94.8v1.8" fill="none" stroke="#000080" stroke-width=".19"/>
<circle cx="214.6" cy="96.6" r=".37" fill="#000080"/>
<circle cx="214.6" cy="96.6" r=".37" fill="none" stroke="#000080" stroke-width=".17"/>
<path d="M259.3 98.5v1.9h-9.3M184.8 117.1v1.9h-1.9" fill="none" stroke="#000080" stroke-width=".19"/>
<circle cx="184.8" cy="119" r=".37" fill="#000080"/>
<circle cx="184.8" cy="119" r=".37" fill="none" stroke="#000080" stroke-width=".17"/>
<path d="M255.6 137.6v1.9" fill="none" stroke="#000080" stroke-width=".19"/>
<circle cx="255.6" cy="137.6" r=".37" fill="#000080"/>
<circle cx="255.6" cy="137.6" r=".37" fill="none" stroke="#000080" stroke-width=".17"/>
<path d="M244.4 137.6h-5.6v1.9" fill="none" stroke="#000080" stroke-width=".19"/>
<circle cx="244.4" cy="137.6" r=".37" fill="#000080"/>
<circle cx="244.4" cy="137.6" r=".37" fill="none" stroke="#000080" stroke-width=".17"/>
<path d="M250 137.6h-5.6v1.9" fill="none" stroke="#000080" stroke-width=".19"/>
<circle cx="244.4" cy="137.6" r=".37" fill="#000080"/>
<circle cx="244.4" cy="137.6" r=".37" fill="none" stroke="#000080" stroke-width=".17"/>
<circle cx="250" cy="137.6" r=".37" fill="#000080"/>
<circle cx="250" cy="137.6" r=".37" fill="none" stroke="#000080" stroke-width=".17"/>
<path d="M153.1 113.4h9.3v3.7h-9.3M153.1 122.7h1.9v1.9M227.7 135.8v3.7" fill="none" stroke="#000080" stroke-width=".19"/>
<circle cx="162.4" cy="117.1" r=".37" fill="#000080"/>
<circle cx="162.4" cy="117.1" r=".37" fill="none" stroke="#000080" stroke-width=".17"/>
<circle cx="162.4" cy="113.4" r=".37" fill="#000080"/>
<circle cx="162.4" cy="113.4" r=".37" fill="none" stroke="#000080" stroke-width=".17"/>
<path d="M162.4 117.1v1.9" fill="none" stroke="#000080" stroke-width=".19"/>
<circle cx="162.4" cy="119" r=".37" fill="#000080"/>
<circle cx="162.4" cy="119" r=".37" fill="none" stroke="#000080" stroke-width=".17"/>
<circle cx="162.4" cy="117.1" r=".37" fill="#000080"/>
<circle cx="162.4" cy="117.1" r=".37" fill="none" stroke="#000080" stroke-width=".17"/>
<path d="M123.3 113.4h-5.6v9.3h-1.9" fill="none" stroke="#000080" stroke-width=".19"/>
<circle cx="117.7" cy="122.7" r=".37" fill="#000080"/>
<circle cx="117.7" cy="122.7" r=".37" fill="none" stroke="#000080" stroke-width=".17"/>
<path d="M117.7 180.5v1.9" fill="none" stroke="#000080" stroke-width=".19"/>
<circle cx="117.7" cy="182.4" r=".37" fill="#000080"/>
<circle cx="117.7" cy="182.4" r=".37" fill="none" stroke="#000080" stroke-width=".17"/>
<path d="M147.5 180.5v1.9" fill="none" stroke="#000080" stroke-width=".19"/>
<circle cx="147.5" cy="182.4" r=".37" fill="#000080"/>
<circle cx="147.5" cy="182.4" r=".37" fill="none" stroke="#000080" stroke-width=".17"/>
<path d="M58.1 31.4h5.6v11.2" fill="none" stroke="#000080" stroke-width=".19"/>
<circle cx="63.7" cy="38.9" r=".37" fill="#000080"/>
<circle cx="63.7" cy="38.9" r=".37" fill="none" stroke="#000080" stroke-width=".17"/>
<path d="M108.4 24v1.8M127 22.1h18.7" fill="none" stroke="#000080" stroke-width=".19"/>
<circle cx="108.4" cy="24" r=".37" fill="#000080"/>
<circle cx="108.4" cy="24" r=".37" fill="none" stroke="#000080" stroke-width=".17"/>
<path d="M188.5 24v1.8M188.5 31.4v3.7" fill="none" stroke="#000080" stroke-width=".19"/>
<circle cx="188.5" cy="24" r=".37" fill="#000080"/>
<circle cx="188.5" cy="24" r=".37" fill="none" stroke="#000080" stroke-width=".17"/>
<path d="M138.2 46.3h3.7" fill="none" stroke="#000080" stroke-width=".19"/>
<circle cx="141.9" cy="46.3" r=".37" fill="#000080"/>
<circle cx="141.9" cy="46.3" r=".37" fill="none" stroke="#000080" stroke-width=".17"/>
<circle cx="140.1" cy="46.3" r=".37" fill="#000080"/>
<circle cx="140.1" cy="46.3" r=".37" fill="none" stroke="#000080" stroke-width=".17"/>
<path d="M143.8 46.3h-1.9v1.9" fill="none" stroke="#000080" stroke-width=".19"/>
<circle cx="141.9" cy="46.3" r=".37" fill="#000080"/>
<circle cx="141.9" cy="46.3" r=".37" fill="none" stroke="#000080" stroke-width=".17"/>
<path d="M141.9 31.4v7.5h3.8" fill="none" stroke="#000080" stroke-width=".19"/>
<circle cx="141.9" cy="31.4" r=".37" fill="#000080"/>
<circle cx="141.9" cy="31.4" r=".37" fill="none" stroke="#000080" stroke-width=".17"/>
<path d="M141.9 29.5v1.9h3.8" fill="none" stroke="#000080" stroke-width=".19"/>
<circle cx="141.9" cy="31.4" r=".37" fill="#000080"/>
<circle cx="141.9" cy="31.4" r=".37" fill="none" stroke="#000080" stroke-width=".17"/>
<path d="M153.1 38.9h5.6M151.3 46.3h1.8" fill="none" stroke="#000080" stroke-width=".19"/>
<circle cx="158.7" cy="38.9" r=".37" fill="#000080"/>
<circle cx="158.7" cy="38.9" r=".37" fill="none" stroke="#000080" stroke-width=".17"/>
<path d="M153.1 31.4h5.6v11.2M141.9 55.6v1.9M158.7 50v7.5" fill="none" stroke="#000080" stroke-width=".19"/>
<circle cx="158.7" cy="38.9" r=".37" fill="#000080"/>
<circle cx="158.7" cy="38.9" r=".37" fill="none" stroke="#000080" stroke-width=".17"/>
<path d="M182.9 33.3v1.8M199.7 22.1h11.2M216.5 107.8h-7.5v26.1h-5.6M203.4 120.9v1.8M203.4 145.1v1.8" fill="none" stroke="#000080" stroke-width=".19"/>
<circle cx="209" cy="111.5" r=".37" fill="#000080"/>
<circle cx="209" cy="111.5" r=".37" fill="none" stroke="#000080" stroke-width=".17"/>
<circle cx="203.4" cy="133.9" r=".37" fill="#000080"/>
<circle cx="203.4" cy="133.9" r=".37" fill="none" stroke="#000080" stroke-width=".17"/>
<path d="M201.6 132h1.8" fill="none" stroke="#000080" stroke-width=".19"/>
<circle cx="203.4" cy="132" r=".37" fill="#000080"/>
<circle cx="203.4" cy="132" r=".37" fill="none" stroke="#000080" stroke-width=".17"/>
<path d="M203.4 135.8h-7.4v1.8" fill="none" stroke="#000080" stroke-width=".19"/>
<circle cx="203.4" cy="135.8" r=".37" fill="#000080"/>
<circle cx="203.4" cy="135.8" r=".37" fill="none" stroke="#000080" stroke-width=".17"/>
<path d="M30.1 22.1h20.5M162.4 120.9v14.9M196 145.1v1.8" fill="none" stroke="#000080" stroke-width=".19"/>
<circle cx="162.4" cy="120.9" r=".37" fill="#000080"/>
<circle cx="162.4" cy="120.9" r=".37" fill="none" stroke="#000080" stroke-width=".17"/>
<path d="M74.8 105.9h-7.4v1.9" fill="none" stroke="#000080" stroke-width=".19"/>
<circle cx="67.4" cy="105.9" r=".37" fill="#000080"/>
<circle cx="67.4" cy="105.9" r=".37" fill="none" stroke="#000080" stroke-width=".17"/>
<path d="M35.7 176.8v1.8M35.7 186.1v1.8" fill="none" stroke="#000080" stroke-width=".19"/>
<circle cx="35.7" cy="176.8" r=".37" fill="#000080"/>
<circle cx="35.7" cy="176.8" r=".37" fill="none" stroke="#000080" stroke-width=".17"/>
<path d="M173.6 122.7h-5.6v22.4h-89.4v-5.6h13" fill="none" stroke="#000080" stroke-width=".19"/>
<circle cx="173.6" cy="122.7" r=".37" fill="#000080"/>
<circle cx="173.6" cy="122.7" r=".37" fill="none" stroke="#000080" stroke-width=".17"/>
<circle cx="78.6" cy="139.5" r=".37" fill="#000080"/>
<circle cx="78.6" cy="139.5" r=".37" fill="none" stroke="#000080" stroke-width=".17"/>
<path d="M78.6 126.4v13.1" fill="none" stroke="#000080" stroke-width=".19"/>
<circle cx="78.6" cy="139.5" r=".37" fill="#000080"/>
<circle cx="78.6" cy="139.5" r=".37" fill="none" stroke="#000080" stroke-width=".17"/>
<path d="M153.1 119h9.3v1.9h-9.3" fill="none" stroke="#000080" stroke-width=".19"/>
<circle cx="162.4" cy="120.9" r=".37" fill="#000080"/>
<circle cx="162.4" cy="120.9" r=".37" fill="none" stroke="#000080" stroke-width=".17"/>
<circle cx="162.4" cy="119" r=".37" fill="#000080"/>
<circle cx="162.4" cy="119" r=".37" fill="none" stroke="#000080" stroke-width=".17"/>
<path d="M140.1 171.2v1.8" fill="none" stroke="#000080" stroke-width=".19"/>
<circle cx="140.1" cy="171.2" r=".37" fill="#000080"/>
<circle cx="140.1" cy="171.2" r=".37" fill="none" stroke="#000080" stroke-width=".17"/>
<path d="M155 160h7.4v1.9" fill="none" stroke="#000080" stroke-width=".19"/>
<circle cx="155" cy="160" r=".37" fill="#000080"/>
<circle cx="155" cy="160" r=".37" fill="none" stroke="#000080" stroke-width=".17"/>
<path d="M162.4 180.5v1.9h-7.4" fill="none" stroke="#000080" stroke-width=".19"/>
<circle cx="155" cy="182.4" r=".37" fill="#000080"/>
<circle cx="155" cy="182.4" r=".37" fill="none" stroke="#000080" stroke-width=".17"/>
<path d="M162.4 169.3v1.9h-7.4" fill="none" stroke="#000080" stroke-width=".19"/>
<circle cx="155" cy="171.2" r=".37" fill="#000080"/>
<circle cx="155" cy="171.2" r=".37" fill="none" stroke="#000080" stroke-width=".17"/>
<circle cx="162.4" cy="171.2" r=".37" fill="#000080"/>
<circle cx="162.4" cy="171.2" r=".37" fill="none" stroke="#000080" stroke-width=".17"/>
<path d="M162.4 171.2v1.8" fill="none" stroke="#000080" stroke-width=".19"/>
<circle cx="162.4" cy="171.2" r=".37" fill="#000080"/>
<circle cx="162.4" cy="171.2" r=".37" fill="none" stroke="#000080" stroke-width=".17"/>
<path d="M147.5 169.3v1.9" fill="none" stroke="#000080" stroke-width=".19"/>
<circle cx="147.5" cy="171.2" r=".37" fill="#000080"/>
<circle cx="147.5" cy="171.2" r=".37" fill="none" stroke="#000080" stroke-width=".17"/>
<path d="M147.5 171.2v1.8" fill="none" stroke="#000080" stroke-width=".19"/>
<circle cx="147.5" cy="171.2" r=".37" fill="#000080"/>
<circle cx="147.5" cy="171.2" r=".37" fill="none" stroke="#000080" stroke-width=".17"/>
<path d="M140.1 169.3v1.9" fill="none" stroke="#000080" stroke-width=".19"/>
<circle cx="140.1" cy="171.2" r=".37" fill="#000080"/>
<circle cx="140.1" cy="171.2" r=".37" fill="none" stroke="#000080" stroke-width=".17"/>
<path d="M132.6 169.3v1.9" fill="none" stroke="#000080" stroke-width=".19"/>
<circle cx="132.6" cy="171.2" r=".37" fill="#000080"/>
<circle cx="132.6" cy="171.2" r=".37" fill="none" stroke="#000080" stroke-width=".17"/>
<path d="M132.6 171.2v1.8" fill="none" stroke="#000080" stroke-width=".19"/>
<circle cx="132.6" cy="171.2" r=".37" fill="#000080"/>
<circle cx="132.6" cy="171.2" r=".37" fill="none" stroke="#000080" stroke-width=".17"/>
<path d="M125.2 171.2v1.8" fill="none" stroke="#000080" stroke-width=".19"/>
<circle cx="125.2" cy="171.2" r=".37" fill="#000080"/>
<circle cx="125.2" cy="171.2" r=".37" fill="none" stroke="#000080" stroke-width=".17"/>
<path d="M125.2 169.3v1.9" fill="none" stroke="#000080" stroke-width=".19"/>
<circle cx="125.2" cy="171.2" r=".37" fill="#000080"/>
<circle cx="125.2" cy="171.2" r=".37" fill="none" stroke="#000080" stroke-width=".17"/>
<path d="M117.7 171.2v1.8" fill="none" stroke="#000080" stroke-width=".19"/>
<circle cx="117.7" cy="171.2" r=".37" fill="#000080"/>
<circle cx="117.7" cy="171.2" r=".37" fill="none" stroke="#000080" stroke-width=".17"/>
<path d="M117.7 169.3v1.9" fill="none" stroke="#000080" stroke-width=".19"/>
<circle cx="117.7" cy="171.2" r=".37" fill="#000080"/>
<circle cx="117.7" cy="171.2" r=".37" fill="none" stroke="#000080" stroke-width=".17"/>
<path d="M100.9 105.9h22.4" fill="none" stroke="#000080" stroke-width=".19"/>
<circle cx="112.1" cy="105.9" r=".37" fill="#000080"/>
<circle cx="112.1" cy="105.9" r=".37" fill="none" stroke="#000080" stroke-width=".17"/>
<path d="M155 180.5v1.9h-42.9" fill="none" stroke="#000080" stroke-width=".19"/>
<circle cx="117.7" cy="182.4" r=".37" fill="#000080"/>
<circle cx="117.7" cy="182.4" r=".37" fill="none" stroke="#000080" stroke-width=".17"/>
<circle cx="125.2" cy="182.4" r=".37" fill="#000080"/>
<circle cx="125.2" cy="182.4" r=".37" fill="none" stroke="#000080" stroke-width=".17"/>
<circle cx="132.6" cy="182.4" r=".37" fill="#000080"/>
<circle cx="132.6" cy="182.4" r=".37" fill="none" stroke="#000080" stroke-width=".17"/>
<circle cx="140.1" cy="182.4" r=".37" fill="#000080"/>
<circle cx="140.1" cy="182.4" r=".37" fill="none" stroke="#000080" stroke-width=".17"/>
<circle cx="147.5" cy="182.4" r=".37" fill="#000080"/>
<circle cx="147.5" cy="182.4" r=".37" fill="none" stroke="#000080" stroke-width=".17"/>
<circle cx="155" cy="182.4" r=".37" fill="#000080"/>
<circle cx="155" cy="182.4" r=".37" fill="none" stroke="#000080" stroke-width=".17"/>
<path d="M112.1 160h13.1v1.9" fill="none" stroke="#000080" stroke-width=".19"/>
<circle cx="117.7" cy="160" r=".37" fill="#000080"/>
<circle cx="117.7" cy="160" r=".37" fill="none" stroke="#000080" stroke-width=".17"/>
<circle cx="125.2" cy="160" r=".37" fill="#000080"/>
<circle cx="125.2" cy="160" r=".37" fill="none" stroke="#000080" stroke-width=".17"/>
<path d="M114 171.2h41" fill="none" stroke="#000080" stroke-width=".19"/>
<circle cx="155" cy="171.2" r=".37" fill="#000080"/>
<circle cx="155" cy="171.2" r=".37" fill="none" stroke="#000080" stroke-width=".17"/>
<circle cx="147.5" cy="171.2" r=".37" fill="#000080"/>
<circle cx="147.5" cy="171.2" r=".37" fill="none" stroke="#000080" stroke-width=".17"/>
<circle cx="140.1" cy="171.2" r=".37" fill="#000080"/>
<circle cx="140.1" cy="171.2" r=".37" fill="none" stroke="#000080" stroke-width=".17"/>
<circle cx="132.6" cy="171.2" r=".37" fill="#000080"/>
<circle cx="132.6" cy="171.2" r=".37" fill="none" stroke="#000080" stroke-width=".17"/>
<circle cx="125.2" cy="171.2" r=".37" fill="#000080"/>
<circle cx="125.2" cy="171.2" r=".37" fill="none" stroke="#000080" stroke-width=".17"/>
<circle cx="117.7" cy="171.2" r=".37" fill="#000080"/>
<circle cx="117.7" cy="171.2" r=".37" fill="none" stroke="#000080" stroke-width=".17"/>
<path d="M121.4 94.8v7.4h1.9" fill="none" stroke="#000080" stroke-width=".19"/>
<circle cx="121.4" cy="100.4" r=".37" fill="#000080"/>
<circle cx="121.4" cy="100.4" r=".37" fill="none" stroke="#000080" stroke-width=".17"/>
<circle cx="121.4" cy="98.5" r=".37" fill="#000080"/>
<circle cx="121.4" cy="98.5" r=".37" fill="none" stroke="#000080" stroke-width=".17"/>
<path d="M125.2 160h29.8v1.9" fill="none" stroke="#000080" stroke-width=".19"/>
<circle cx="125.2" cy="160" r=".37" fill="#000080"/>
<circle cx="125.2" cy="160" r=".37" fill="none" stroke="#000080" stroke-width=".17"/>
<circle cx="132.6" cy="160" r=".37" fill="#000080"/>
<circle cx="132.6" cy="160" r=".37" fill="none" stroke="#000080" stroke-width=".17"/>
<circle cx="140.1" cy="160" r=".37" fill="#000080"/>
<circle cx="140.1" cy="160" r=".37" fill="none" stroke="#000080" stroke-width=".17"/>
<circle cx="147.5" cy="160" r=".37" fill="#000080"/>
<circle cx="147.5" cy="160" r=".37" fill="none" stroke="#000080" stroke-width=".17"/>
<circle cx="155" cy="160" r=".37" fill="#000080"/>
<circle cx="155" cy="160" r=".37" fill="none" stroke="#000080" stroke-width=".17"/>
<path d="M153.1 105.9h28" fill="none" stroke="#000080" stroke-width=".19"/>
<circle cx="173.6" cy="105.9" r=".37" fill="#000080"/>
<circle cx="173.6" cy="105.9" r=".37" fill="none" stroke="#000080" stroke-width=".17"/>
<circle cx="179.2" cy="105.9" r=".37" fill="#000080"/>
<circle cx="179.2" cy="105.9" r=".37" fill="none" stroke="#000080" stroke-width=".17"/>
<path d="M209 96.6h7.5" fill="none" stroke="#000080" stroke-width=".19"/>
<circle cx="210.9" cy="96.6" r=".37" fill="#000080"/>
<circle cx="210.9" cy="96.6" r=".37" fill="none" stroke="#000080" stroke-width=".17"/>
<circle cx="214.6" cy="96.6" r=".37" fill="#000080"/>
<circle cx="214.6" cy="96.6" r=".37" fill="none" stroke="#000080" stroke-width=".17"/>
<path d="M216.5 117.1h-1.9v3.8h1.9" fill="none" stroke="#000080" stroke-width=".19"/>
<circle cx="214.6" cy="119" r=".37" fill="#000080"/>
<circle cx="214.6" cy="119" r=".37" fill="none" stroke="#000080" stroke-width=".17"/>
<circle cx="214.6" cy="120.9" r=".37" fill="#000080"/>
<circle cx="214.6" cy="120.9" r=".37" fill="none" stroke="#000080" stroke-width=".17"/>
<path d="M253.8 94.8v3.7h-3.8" fill="none" stroke="#000080" stroke-width=".19"/>
<circle cx="253.8" cy="96.6" r=".37" fill="#000080"/>
<circle cx="253.8" cy="96.6" r=".37" fill="none" stroke="#000080" stroke-width=".17"/>
<path d="M155 169.3v3.7" fill="none" stroke="#000080" stroke-width=".19"/>
<circle cx="155" cy="171.2" r=".37" fill="#000080"/>
<circle cx="155" cy="171.2" r=".37" fill="none" stroke="#000080" stroke-width=".17"/>
<path d="M173.6 133.9v3.7" fill="none" stroke="#000080" stroke-width=".19"/>
<circle cx="173.6" cy="135.8" r=".37" fill="#000080"/>
<circle cx="173.6" cy="135.8" r=".37" fill="none" stroke="#000080" stroke-width=".17"/>
<path d="M173.6 117.1v9.3" fill="none" stroke="#000080" stroke-width=".19"/>
<circle cx="173.6" cy="119" r=".37" fill="#000080"/>
<circle cx="173.6" cy="119" r=".37" fill="none" stroke="#000080" stroke-width=".17"/>
<circle cx="173.6" cy="122.7" r=".37" fill="#000080"/>
<circle cx="173.6" cy="122.7" r=".37" fill="none" stroke="#000080" stroke-width=".17"/>
<path d="M203.4 133.9v3.7" fill="none" stroke="#000080" stroke-width=".19"/>
<circle cx="203.4" cy="135.8" r=".37" fill="#000080"/>
<circle cx="203.4" cy="135.8" r=".37" fill="none" stroke="#000080" stroke-width=".17"/>
<circle cx="203.4" cy="133.9" r=".37" fill="#000080"/>
<circle cx="203.4" cy="133.9" r=".37" fill="none" stroke="#000080" stroke-width=".17"/>
<path d="M203.4 130.2v3.7" fill="none" stroke="#000080" stroke-width=".19"/>
<circle cx="203.4" cy="133.9" r=".37" fill="#000080"/>
<circle cx="203.4" cy="133.9" r=".37" fill="none" stroke="#000080" stroke-width=".17"/>
<circle cx="203.4" cy="132" r=".37" fill="#000080"/>
<circle cx="203.4" cy="132" r=".37" fill="none" stroke="#000080" stroke-width=".17"/>
<path d="M261.2 135.8v1.8h-11.2v1.9" fill="none" stroke="#000080" stroke-width=".19"/>
<circle cx="250" cy="137.6" r=".37" fill="#000080"/>
<circle cx="250" cy="137.6" r=".37" fill="none" stroke="#000080" stroke-width=".17"/>
<circle cx="255.6" cy="137.6" r=".37" fill="#000080"/>
<circle cx="255.6" cy="137.6" r=".37" fill="none" stroke="#000080" stroke-width=".17"/>
<path d="M48.8 105.9h18.6" fill="none" stroke="#000080" stroke-width=".19"/>
<circle cx="67.4" cy="105.9" r=".37" fill="#000080"/>
<circle cx="67.4" cy="105.9" r=".37" fill="none" stroke="#000080" stroke-width=".17"/>
<path d="M179.2 104.1v1.8M250 105.9h26.1M250 107.8h20.5" fill="none" stroke="#000080" stroke-width=".19"/>
<circle cx="179.2" cy="105.9" r=".37" fill="#000080"/>
<circle cx="179.2" cy="105.9" r=".37" fill="none" stroke="#000080" stroke-width=".17"/>
<path d="M69.3 23.9v1.9M69.3 33.3v1.8M182.9 87.3h-3.7v9.3" fill="none" stroke="#000080" stroke-width=".19"/>
<circle cx="69.3" cy="23.9" r=".37" fill="#000080"/>
<circle cx="69.3" cy="23.9" r=".37" fill="none" stroke="#000080" stroke-width=".17"/>
<path d="M102.8 24v1.8M108.4 33.3v1.8" fill="none" stroke="#000080" stroke-width=".19"/>
<circle cx="102.8" cy="24" r=".37" fill="#000080"/>
<circle cx="102.8" cy="24" r=".37" fill="none" stroke="#000080" stroke-width=".17"/>
<path d="M97.2 24v3.7h-7.4" fill="none" stroke="#000080" stroke-width=".19"/>
<circle cx="97.2" cy="24" r=".37" fill="#000080"/>
<circle cx="97.2" cy="24" r=".37" fill="none" stroke="#000080" stroke-width=".17"/>
<path d="M95.3 24h24.3" fill="none" stroke="#000080" stroke-width=".19"/>
<circle cx="97.2" cy="24" r=".37" fill="#000080"/>
<circle cx="97.2" cy="24" r=".37" fill="none" stroke="#000080" stroke-width=".17"/>
<circle cx="102.8" cy="24" r=".37" fill="#000080"/>
<circle cx="102.8" cy="24" r=".37" fill="none" stroke="#000080" stroke-width=".17"/>
<circle cx="108.4" cy="24" r=".37" fill="#000080"/>
<circle cx="108.4" cy="24" r=".37" fill="none" stroke="#000080" stroke-width=".17"/>
<circle cx="114" cy="24" r=".37" fill="#000080"/>
<circle cx="114" cy="24" r=".37" fill="none" stroke="#000080" stroke-width=".17"/>
<path d="M114 24v1.8M114 33.3v1.8" fill="none" stroke="#000080" stroke-width=".19"/>
<circle cx="114" cy="24" r=".37" fill="#000080"/>
<circle cx="114" cy="24" r=".37" fill="none" stroke="#000080" stroke-width=".17"/>
<path d="M67.4 124.6v7.4" fill="none" stroke="#000080" stroke-width=".19"/>
<circle cx="67.4" cy="128.3" r=".37" fill="#000080"/>
<circle cx="67.4" cy="128.3" r=".37" fill="none" stroke="#000080" stroke-width=".17"/>
<circle cx="67.4" cy="124.6" r=".37" fill="#000080"/>
<circle cx="67.4" cy="124.6" r=".37" fill="none" stroke="#000080" stroke-width=".17"/>
<path d="M67.4 115.3v1.8" fill="none" stroke="#000080" stroke-width=".19"/>
<circle cx="67.4" cy="117.1" r=".37" fill="#000080"/>
<circle cx="67.4" cy="117.1" r=".37" fill="none" stroke="#000080" stroke-width=".17"/>
<path d="M78.6 119h-3.8v9.3h-7.4" fill="none" stroke="#000080" stroke-width=".19"/>
<circle cx="67.4" cy="128.3" r=".37" fill="#000080"/>
<circle cx="67.4" cy="128.3" r=".37" fill="none" stroke="#000080" stroke-width=".17"/>
<path d="M39.4 115.3v1.8h1.9M41.3 124.6h-1.9v1.8M33.8 176.8h7.5M48.8 176.8h1.8M56.2 180.5v7.4" fill="none" stroke="#000080" stroke-width=".19"/>
<circle cx="35.7" cy="176.8" r=".37" fill="#000080"/>
<circle cx="35.7" cy="176.8" r=".37" fill="none" stroke="#000080" stroke-width=".17"/>
<circle cx="37.6" cy="176.8" r=".37" fill="#000080"/>
<circle cx="37.6" cy="176.8" r=".37" fill="none" stroke="#000080" stroke-width=".17"/>
<path d="M56.2 160v1.9M56.2 169.3v3.7" fill="none" stroke="#000080" stroke-width=".19"/>
<circle cx="56.2" cy="171.2" r=".37" fill="#000080"/>
<circle cx="56.2" cy="171.2" r=".37" fill="none" stroke="#000080" stroke-width=".17"/>
<path d="M56.2 171.2h13.1" fill="none" stroke="#000080" stroke-width=".19"/>
<circle cx="56.2" cy="171.2" r=".37" fill="#000080"/>
<circle cx="56.2" cy="171.2" r=".37" fill="none" stroke="#000080" stroke-width=".17"/>
<path d="M58.1 20.2h61.5M153.1 20.2h1.9M153.1 24h11.2M162.4 20.2h9.4M188.5 24h3.8M30.1 120.9h11.2" fill="none" stroke="#000080" stroke-width=".19"/>
<circle cx="188.5" cy="24" r=".37" fill="#000080"/>
<circle cx="188.5" cy="24" r=".37" fill="none" stroke="#000080" stroke-width=".17"/>
<path d="M182.9 20.2v5.6" fill="none" stroke="#000080" stroke-width=".19"/>
<circle cx="182.9" cy="20.2" r=".37" fill="#000080"/>
<circle cx="182.9" cy="20.2" r=".37" fill="none" stroke="#000080" stroke-width=".17"/>
<path d="M179.2 20.2h13.1" fill="none" stroke="#000080" stroke-width=".19"/>
<circle cx="182.9" cy="20.2" r=".37" fill="#000080"/>
<circle cx="182.9" cy="20.2" r=".37" fill="none" stroke="#000080" stroke-width=".17"/>
<path d="M58.1 23.9h1.8M67.4 23.9h1.9" fill="none" stroke="#000080" stroke-width=".19"/>
<circle cx="69.3" cy="23.9" r=".37" fill="#000080"/>
<circle cx="69.3" cy="23.9" r=".37" fill="none" stroke="#000080" stroke-width=".17"/>
<path d="M69.3 23.9h7.4" fill="none" stroke="#000080" stroke-width=".19"/>
<circle cx="69.3" cy="23.9" r=".37" fill="#000080"/>
<circle cx="69.3" cy="23.9" r=".37" fill="none" stroke="#000080" stroke-width=".17"/>
<circle cx="74.8" cy="23.9" r=".37" fill="#000080"/>
<circle cx="74.8" cy="23.9" r=".37" fill="none" stroke="#000080" stroke-width=".17"/>
<path d="M171.8 24h16.7" fill="none" stroke="#000080" stroke-width=".19"/>
<circle cx="188.5" cy="24" r=".37" fill="#000080"/>
<circle cx="188.5" cy="24" r=".37" fill="none" stroke="#000080" stroke-width=".17"/>
<path d="M63.7 117.1h3.7" fill="none" stroke="#000080" stroke-width=".19"/>
<circle cx="67.4" cy="117.1" r=".37" fill="#000080"/>
<circle cx="67.4" cy="117.1" r=".37" fill="none" stroke="#000080" stroke-width=".17"/>
<path d="M63.7 124.6h3.7" fill="none" stroke="#000080" stroke-width=".19"/>
<circle cx="67.4" cy="124.6" r=".37" fill="#000080"/>
<circle cx="67.4" cy="124.6" r=".37" fill="none" stroke="#000080" stroke-width=".17"/>
<use href="#words"/>
</svg>
